VERSION 5.8 ;
BUSBITCHARS "[]" ;
DIVIDERCHAR "/" ;
UNITS
    DATABASE MICRONS 1000 ;
END UNITS

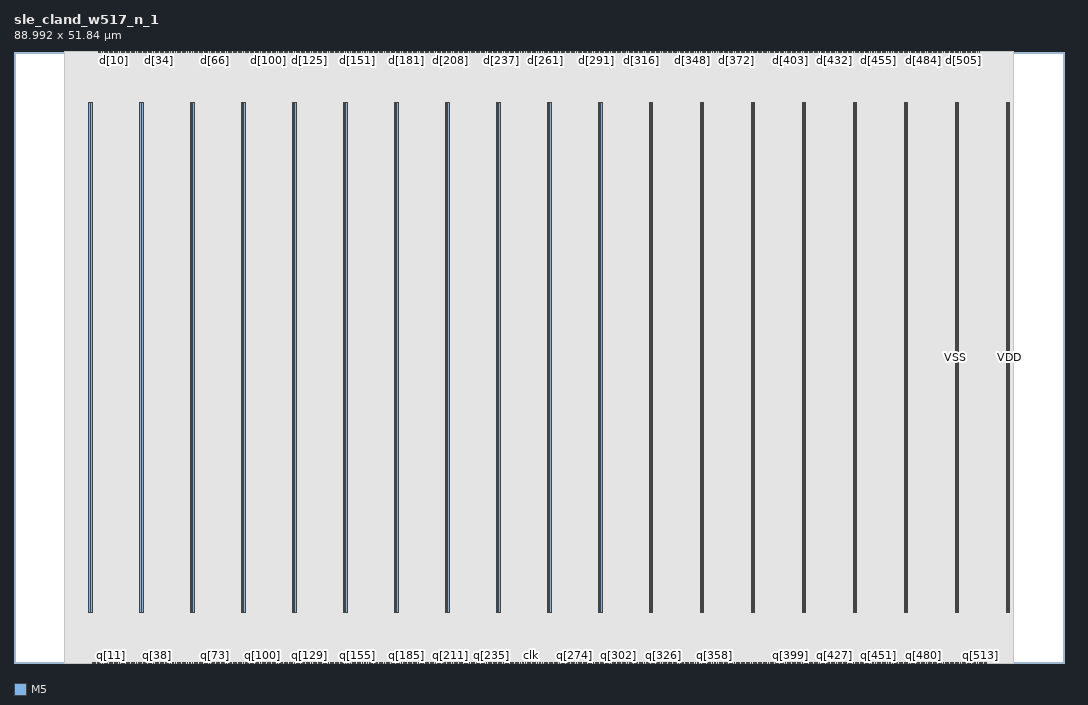
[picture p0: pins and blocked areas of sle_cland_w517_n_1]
MACRO sle_cland_w517_n_1
  FOREIGN sle_cland_w517_n_1 0 0 ;
  CLASS BLOCK ;
  SIZE 88.992 BY 51.84 ;
  PIN clk
    DIRECTION INPUT ;
    USE SIGNAL ;
    PORT
      LAYER M5 ;
        RECT  43.776 0 43.8 0.084 ;
    END
  END clk
  PIN d[0]
    DIRECTION INPUT ;
    USE SIGNAL ;
    PORT
      LAYER M5 ;
        RECT  7.2 51.756 7.224 51.84 ;
    END
  END d[0]
  PIN d[100]
    DIRECTION INPUT ;
    USE SIGNAL ;
    PORT
      LAYER M5 ;
        RECT  21.6 51.756 21.624 51.84 ;
    END
  END d[100]
  PIN d[101]
    DIRECTION INPUT ;
    USE SIGNAL ;
    PORT
      LAYER M5 ;
        RECT  21.888 51.756 21.912 51.84 ;
    END
  END d[101]
  PIN d[102]
    DIRECTION INPUT ;
    USE SIGNAL ;
    PORT
      LAYER M5 ;
        RECT  21.744 51.756 21.768 51.84 ;
    END
  END d[102]
  PIN d[103]
    DIRECTION INPUT ;
    USE SIGNAL ;
    PORT
      LAYER M5 ;
        RECT  22.176 51.756 22.2 51.84 ;
    END
  END d[103]
  PIN d[104]
    DIRECTION INPUT ;
    USE SIGNAL ;
    PORT
      LAYER M5 ;
        RECT  22.032 51.756 22.056 51.84 ;
    END
  END d[104]
  PIN d[105]
    DIRECTION INPUT ;
    USE SIGNAL ;
    PORT
      LAYER M5 ;
        RECT  22.464 51.756 22.488 51.84 ;
    END
  END d[105]
  PIN d[106]
    DIRECTION INPUT ;
    USE SIGNAL ;
    PORT
      LAYER M5 ;
        RECT  22.32 51.756 22.344 51.84 ;
    END
  END d[106]
  PIN d[107]
    DIRECTION INPUT ;
    USE SIGNAL ;
    PORT
      LAYER M5 ;
        RECT  22.752 51.756 22.776 51.84 ;
    END
  END d[107]
  PIN d[108]
    DIRECTION INPUT ;
    USE SIGNAL ;
    PORT
      LAYER M5 ;
        RECT  22.608 51.756 22.632 51.84 ;
    END
  END d[108]
  PIN d[109]
    DIRECTION INPUT ;
    USE SIGNAL ;
    PORT
      LAYER M5 ;
        RECT  23.04 51.756 23.064 51.84 ;
    END
  END d[109]
  PIN d[10]
    DIRECTION INPUT ;
    USE SIGNAL ;
    PORT
      LAYER M5 ;
        RECT  8.496 51.756 8.52 51.84 ;
    END
  END d[10]
  PIN d[110]
    DIRECTION INPUT ;
    USE SIGNAL ;
    PORT
      LAYER M5 ;
        RECT  22.896 51.756 22.92 51.84 ;
    END
  END d[110]
  PIN d[111]
    DIRECTION INPUT ;
    USE SIGNAL ;
    PORT
      LAYER M5 ;
        RECT  23.184 51.756 23.208 51.84 ;
    END
  END d[111]
  PIN d[112]
    DIRECTION INPUT ;
    USE SIGNAL ;
    PORT
      LAYER M5 ;
        RECT  23.616 51.756 23.64 51.84 ;
    END
  END d[112]
  PIN d[113]
    DIRECTION INPUT ;
    USE SIGNAL ;
    PORT
      LAYER M5 ;
        RECT  23.328 51.756 23.352 51.84 ;
    END
  END d[113]
  PIN d[114]
    DIRECTION INPUT ;
    USE SIGNAL ;
    PORT
      LAYER M5 ;
        RECT  23.904 51.756 23.928 51.84 ;
    END
  END d[114]
  PIN d[115]
    DIRECTION INPUT ;
    USE SIGNAL ;
    PORT
      LAYER M5 ;
        RECT  23.472 51.756 23.496 51.84 ;
    END
  END d[115]
  PIN d[116]
    DIRECTION INPUT ;
    USE SIGNAL ;
    PORT
      LAYER M5 ;
        RECT  24.048 51.756 24.072 51.84 ;
    END
  END d[116]
  PIN d[117]
    DIRECTION INPUT ;
    USE SIGNAL ;
    PORT
      LAYER M5 ;
        RECT  23.76 51.756 23.784 51.84 ;
    END
  END d[117]
  PIN d[118]
    DIRECTION INPUT ;
    USE SIGNAL ;
    PORT
      LAYER M5 ;
        RECT  24.336 51.756 24.36 51.84 ;
    END
  END d[118]
  PIN d[119]
    DIRECTION INPUT ;
    USE SIGNAL ;
    PORT
      LAYER M5 ;
        RECT  24.192 51.756 24.216 51.84 ;
    END
  END d[119]
  PIN d[11]
    DIRECTION INPUT ;
    USE SIGNAL ;
    PORT
      LAYER M5 ;
        RECT  8.784 51.756 8.808 51.84 ;
    END
  END d[11]
  PIN d[120]
    DIRECTION INPUT ;
    USE SIGNAL ;
    PORT
      LAYER M5 ;
        RECT  24.624 51.756 24.648 51.84 ;
    END
  END d[120]
  PIN d[121]
    DIRECTION INPUT ;
    USE SIGNAL ;
    PORT
      LAYER M5 ;
        RECT  24.48 51.756 24.504 51.84 ;
    END
  END d[121]
  PIN d[122]
    DIRECTION INPUT ;
    USE SIGNAL ;
    PORT
      LAYER M5 ;
        RECT  24.912 51.756 24.936 51.84 ;
    END
  END d[122]
  PIN d[123]
    DIRECTION INPUT ;
    USE SIGNAL ;
    PORT
      LAYER M5 ;
        RECT  24.768 51.756 24.792 51.84 ;
    END
  END d[123]
  PIN d[124]
    DIRECTION INPUT ;
    USE SIGNAL ;
    PORT
      LAYER M5 ;
        RECT  25.2 51.756 25.224 51.84 ;
    END
  END d[124]
  PIN d[125]
    DIRECTION INPUT ;
    USE SIGNAL ;
    PORT
      LAYER M5 ;
        RECT  25.056 51.756 25.08 51.84 ;
    END
  END d[125]
  PIN d[126]
    DIRECTION INPUT ;
    USE SIGNAL ;
    PORT
      LAYER M5 ;
        RECT  25.488 51.756 25.512 51.84 ;
    END
  END d[126]
  PIN d[127]
    DIRECTION INPUT ;
    USE SIGNAL ;
    PORT
      LAYER M5 ;
        RECT  25.344 51.756 25.368 51.84 ;
    END
  END d[127]
  PIN d[128]
    DIRECTION INPUT ;
    USE SIGNAL ;
    PORT
      LAYER M5 ;
        RECT  25.776 51.756 25.8 51.84 ;
    END
  END d[128]
  PIN d[129]
    DIRECTION INPUT ;
    USE SIGNAL ;
    PORT
      LAYER M5 ;
        RECT  25.632 51.756 25.656 51.84 ;
    END
  END d[129]
  PIN d[12]
    DIRECTION INPUT ;
    USE SIGNAL ;
    PORT
      LAYER M5 ;
        RECT  9.216 51.756 9.24 51.84 ;
    END
  END d[12]
  PIN d[130]
    DIRECTION INPUT ;
    USE SIGNAL ;
    PORT
      LAYER M5 ;
        RECT  25.92 51.756 25.944 51.84 ;
    END
  END d[130]
  PIN d[131]
    DIRECTION INPUT ;
    USE SIGNAL ;
    PORT
      LAYER M5 ;
        RECT  26.064 51.756 26.088 51.84 ;
    END
  END d[131]
  PIN d[132]
    DIRECTION INPUT ;
    USE SIGNAL ;
    PORT
      LAYER M5 ;
        RECT  26.208 51.756 26.232 51.84 ;
    END
  END d[132]
  PIN d[133]
    DIRECTION INPUT ;
    USE SIGNAL ;
    PORT
      LAYER M5 ;
        RECT  26.352 51.756 26.376 51.84 ;
    END
  END d[133]
  PIN d[134]
    DIRECTION INPUT ;
    USE SIGNAL ;
    PORT
      LAYER M5 ;
        RECT  26.496 51.756 26.52 51.84 ;
    END
  END d[134]
  PIN d[135]
    DIRECTION INPUT ;
    USE SIGNAL ;
    PORT
      LAYER M5 ;
        RECT  26.64 51.756 26.664 51.84 ;
    END
  END d[135]
  PIN d[136]
    DIRECTION INPUT ;
    USE SIGNAL ;
    PORT
      LAYER M5 ;
        RECT  26.784 51.756 26.808 51.84 ;
    END
  END d[136]
  PIN d[137]
    DIRECTION INPUT ;
    USE SIGNAL ;
    PORT
      LAYER M5 ;
        RECT  26.928 51.756 26.952 51.84 ;
    END
  END d[137]
  PIN d[138]
    DIRECTION INPUT ;
    USE SIGNAL ;
    PORT
      LAYER M5 ;
        RECT  27.072 51.756 27.096 51.84 ;
    END
  END d[138]
  PIN d[139]
    DIRECTION INPUT ;
    USE SIGNAL ;
    PORT
      LAYER M5 ;
        RECT  27.216 51.756 27.24 51.84 ;
    END
  END d[139]
  PIN d[13]
    DIRECTION INPUT ;
    USE SIGNAL ;
    PORT
      LAYER M5 ;
        RECT  8.928 51.756 8.952 51.84 ;
    END
  END d[13]
  PIN d[140]
    DIRECTION INPUT ;
    USE SIGNAL ;
    PORT
      LAYER M5 ;
        RECT  27.36 51.756 27.384 51.84 ;
    END
  END d[140]
  PIN d[141]
    DIRECTION INPUT ;
    USE SIGNAL ;
    PORT
      LAYER M5 ;
        RECT  27.504 51.756 27.528 51.84 ;
    END
  END d[141]
  PIN d[142]
    DIRECTION INPUT ;
    USE SIGNAL ;
    PORT
      LAYER M5 ;
        RECT  27.648 51.756 27.672 51.84 ;
    END
  END d[142]
  PIN d[143]
    DIRECTION INPUT ;
    USE SIGNAL ;
    PORT
      LAYER M5 ;
        RECT  27.792 51.756 27.816 51.84 ;
    END
  END d[143]
  PIN d[144]
    DIRECTION INPUT ;
    USE SIGNAL ;
    PORT
      LAYER M5 ;
        RECT  27.936 51.756 27.96 51.84 ;
    END
  END d[144]
  PIN d[145]
    DIRECTION INPUT ;
    USE SIGNAL ;
    PORT
      LAYER M5 ;
        RECT  28.08 51.756 28.104 51.84 ;
    END
  END d[145]
  PIN d[146]
    DIRECTION INPUT ;
    USE SIGNAL ;
    PORT
      LAYER M5 ;
        RECT  28.224 51.756 28.248 51.84 ;
    END
  END d[146]
  PIN d[147]
    DIRECTION INPUT ;
    USE SIGNAL ;
    PORT
      LAYER M5 ;
        RECT  28.512 51.756 28.536 51.84 ;
    END
  END d[147]
  PIN d[148]
    DIRECTION INPUT ;
    USE SIGNAL ;
    PORT
      LAYER M5 ;
        RECT  28.368 51.756 28.392 51.84 ;
    END
  END d[148]
  PIN d[149]
    DIRECTION INPUT ;
    USE SIGNAL ;
    PORT
      LAYER M5 ;
        RECT  28.656 51.756 28.68 51.84 ;
    END
  END d[149]
  PIN d[14]
    DIRECTION INPUT ;
    USE SIGNAL ;
    PORT
      LAYER M5 ;
        RECT  9.504 51.756 9.528 51.84 ;
    END
  END d[14]
  PIN d[150]
    DIRECTION INPUT ;
    USE SIGNAL ;
    PORT
      LAYER M5 ;
        RECT  28.8 51.756 28.824 51.84 ;
    END
  END d[150]
  PIN d[151]
    DIRECTION INPUT ;
    USE SIGNAL ;
    PORT
      LAYER M5 ;
        RECT  29.088 51.756 29.112 51.84 ;
    END
  END d[151]
  PIN d[152]
    DIRECTION INPUT ;
    USE SIGNAL ;
    PORT
      LAYER M5 ;
        RECT  28.944 51.756 28.968 51.84 ;
    END
  END d[152]
  PIN d[153]
    DIRECTION INPUT ;
    USE SIGNAL ;
    PORT
      LAYER M5 ;
        RECT  29.376 51.756 29.4 51.84 ;
    END
  END d[153]
  PIN d[154]
    DIRECTION INPUT ;
    USE SIGNAL ;
    PORT
      LAYER M5 ;
        RECT  29.232 51.756 29.256 51.84 ;
    END
  END d[154]
  PIN d[155]
    DIRECTION INPUT ;
    USE SIGNAL ;
    PORT
      LAYER M5 ;
        RECT  29.664 51.756 29.688 51.84 ;
    END
  END d[155]
  PIN d[156]
    DIRECTION INPUT ;
    USE SIGNAL ;
    PORT
      LAYER M5 ;
        RECT  29.52 51.756 29.544 51.84 ;
    END
  END d[156]
  PIN d[157]
    DIRECTION INPUT ;
    USE SIGNAL ;
    PORT
      LAYER M5 ;
        RECT  29.952 51.756 29.976 51.84 ;
    END
  END d[157]
  PIN d[158]
    DIRECTION INPUT ;
    USE SIGNAL ;
    PORT
      LAYER M5 ;
        RECT  29.808 51.756 29.832 51.84 ;
    END
  END d[158]
  PIN d[159]
    DIRECTION INPUT ;
    USE SIGNAL ;
    PORT
      LAYER M5 ;
        RECT  30.24 51.756 30.264 51.84 ;
    END
  END d[159]
  PIN d[15]
    DIRECTION INPUT ;
    USE SIGNAL ;
    PORT
      LAYER M5 ;
        RECT  9.072 51.756 9.096 51.84 ;
    END
  END d[15]
  PIN d[160]
    DIRECTION INPUT ;
    USE SIGNAL ;
    PORT
      LAYER M5 ;
        RECT  30.096 51.756 30.12 51.84 ;
    END
  END d[160]
  PIN d[161]
    DIRECTION INPUT ;
    USE SIGNAL ;
    PORT
      LAYER M5 ;
        RECT  30.384 51.756 30.408 51.84 ;
    END
  END d[161]
  PIN d[162]
    DIRECTION INPUT ;
    USE SIGNAL ;
    PORT
      LAYER M5 ;
        RECT  30.672 51.756 30.696 51.84 ;
    END
  END d[162]
  PIN d[163]
    DIRECTION INPUT ;
    USE SIGNAL ;
    PORT
      LAYER M5 ;
        RECT  30.528 51.756 30.552 51.84 ;
    END
  END d[163]
  PIN d[164]
    DIRECTION INPUT ;
    USE SIGNAL ;
    PORT
      LAYER M5 ;
        RECT  30.96 51.756 30.984 51.84 ;
    END
  END d[164]
  PIN d[165]
    DIRECTION INPUT ;
    USE SIGNAL ;
    PORT
      LAYER M5 ;
        RECT  30.816 51.756 30.84 51.84 ;
    END
  END d[165]
  PIN d[166]
    DIRECTION INPUT ;
    USE SIGNAL ;
    PORT
      LAYER M5 ;
        RECT  31.248 51.756 31.272 51.84 ;
    END
  END d[166]
  PIN d[167]
    DIRECTION INPUT ;
    USE SIGNAL ;
    PORT
      LAYER M5 ;
        RECT  31.104 51.756 31.128 51.84 ;
    END
  END d[167]
  PIN d[168]
    DIRECTION INPUT ;
    USE SIGNAL ;
    PORT
      LAYER M5 ;
        RECT  31.536 51.756 31.56 51.84 ;
    END
  END d[168]
  PIN d[169]
    DIRECTION INPUT ;
    USE SIGNAL ;
    PORT
      LAYER M5 ;
        RECT  31.392 51.756 31.416 51.84 ;
    END
  END d[169]
  PIN d[16]
    DIRECTION INPUT ;
    USE SIGNAL ;
    PORT
      LAYER M5 ;
        RECT  9.792 51.756 9.816 51.84 ;
    END
  END d[16]
  PIN d[170]
    DIRECTION INPUT ;
    USE SIGNAL ;
    PORT
      LAYER M5 ;
        RECT  31.824 51.756 31.848 51.84 ;
    END
  END d[170]
  PIN d[171]
    DIRECTION INPUT ;
    USE SIGNAL ;
    PORT
      LAYER M5 ;
        RECT  31.68 51.756 31.704 51.84 ;
    END
  END d[171]
  PIN d[172]
    DIRECTION INPUT ;
    USE SIGNAL ;
    PORT
      LAYER M5 ;
        RECT  32.112 51.756 32.136 51.84 ;
    END
  END d[172]
  PIN d[173]
    DIRECTION INPUT ;
    USE SIGNAL ;
    PORT
      LAYER M5 ;
        RECT  31.968 51.756 31.992 51.84 ;
    END
  END d[173]
  PIN d[174]
    DIRECTION INPUT ;
    USE SIGNAL ;
    PORT
      LAYER M5 ;
        RECT  32.256 51.756 32.28 51.84 ;
    END
  END d[174]
  PIN d[175]
    DIRECTION INPUT ;
    USE SIGNAL ;
    PORT
      LAYER M5 ;
        RECT  32.4 51.756 32.424 51.84 ;
    END
  END d[175]
  PIN d[176]
    DIRECTION INPUT ;
    USE SIGNAL ;
    PORT
      LAYER M5 ;
        RECT  32.688 51.756 32.712 51.84 ;
    END
  END d[176]
  PIN d[177]
    DIRECTION INPUT ;
    USE SIGNAL ;
    PORT
      LAYER M5 ;
        RECT  32.544 51.756 32.568 51.84 ;
    END
  END d[177]
  PIN d[178]
    DIRECTION INPUT ;
    USE SIGNAL ;
    PORT
      LAYER M5 ;
        RECT  32.976 51.756 33 51.84 ;
    END
  END d[178]
  PIN d[179]
    DIRECTION INPUT ;
    USE SIGNAL ;
    PORT
      LAYER M5 ;
        RECT  32.832 51.756 32.856 51.84 ;
    END
  END d[179]
  PIN d[17]
    DIRECTION INPUT ;
    USE SIGNAL ;
    PORT
      LAYER M5 ;
        RECT  9.36 51.756 9.384 51.84 ;
    END
  END d[17]
  PIN d[180]
    DIRECTION INPUT ;
    USE SIGNAL ;
    PORT
      LAYER M5 ;
        RECT  33.12 51.756 33.144 51.84 ;
    END
  END d[180]
  PIN d[181]
    DIRECTION INPUT ;
    USE SIGNAL ;
    PORT
      LAYER M5 ;
        RECT  33.264 51.756 33.288 51.84 ;
    END
  END d[181]
  PIN d[182]
    DIRECTION INPUT ;
    USE SIGNAL ;
    PORT
      LAYER M5 ;
        RECT  33.408 51.756 33.432 51.84 ;
    END
  END d[182]
  PIN d[183]
    DIRECTION INPUT ;
    USE SIGNAL ;
    PORT
      LAYER M5 ;
        RECT  33.552 51.756 33.576 51.84 ;
    END
  END d[183]
  PIN d[184]
    DIRECTION INPUT ;
    USE SIGNAL ;
    PORT
      LAYER M5 ;
        RECT  33.696 51.756 33.72 51.84 ;
    END
  END d[184]
  PIN d[185]
    DIRECTION INPUT ;
    USE SIGNAL ;
    PORT
      LAYER M5 ;
        RECT  33.84 51.756 33.864 51.84 ;
    END
  END d[185]
  PIN d[186]
    DIRECTION INPUT ;
    USE SIGNAL ;
    PORT
      LAYER M5 ;
        RECT  33.984 51.756 34.008 51.84 ;
    END
  END d[186]
  PIN d[187]
    DIRECTION INPUT ;
    USE SIGNAL ;
    PORT
      LAYER M5 ;
        RECT  34.128 51.756 34.152 51.84 ;
    END
  END d[187]
  PIN d[188]
    DIRECTION INPUT ;
    USE SIGNAL ;
    PORT
      LAYER M5 ;
        RECT  34.272 51.756 34.296 51.84 ;
    END
  END d[188]
  PIN d[189]
    DIRECTION INPUT ;
    USE SIGNAL ;
    PORT
      LAYER M5 ;
        RECT  34.416 51.756 34.44 51.84 ;
    END
  END d[189]
  PIN d[18]
    DIRECTION INPUT ;
    USE SIGNAL ;
    PORT
      LAYER M5 ;
        RECT  10.08 51.756 10.104 51.84 ;
    END
  END d[18]
  PIN d[190]
    DIRECTION INPUT ;
    USE SIGNAL ;
    PORT
      LAYER M5 ;
        RECT  34.56 51.756 34.584 51.84 ;
    END
  END d[190]
  PIN d[191]
    DIRECTION INPUT ;
    USE SIGNAL ;
    PORT
      LAYER M5 ;
        RECT  34.704 51.756 34.728 51.84 ;
    END
  END d[191]
  PIN d[192]
    DIRECTION INPUT ;
    USE SIGNAL ;
    PORT
      LAYER M5 ;
        RECT  34.848 51.756 34.872 51.84 ;
    END
  END d[192]
  PIN d[193]
    DIRECTION INPUT ;
    USE SIGNAL ;
    PORT
      LAYER M5 ;
        RECT  35.136 51.756 35.16 51.84 ;
    END
  END d[193]
  PIN d[194]
    DIRECTION INPUT ;
    USE SIGNAL ;
    PORT
      LAYER M5 ;
        RECT  34.992 51.756 35.016 51.84 ;
    END
  END d[194]
  PIN d[195]
    DIRECTION INPUT ;
    USE SIGNAL ;
    PORT
      LAYER M5 ;
        RECT  35.424 51.756 35.448 51.84 ;
    END
  END d[195]
  PIN d[196]
    DIRECTION INPUT ;
    USE SIGNAL ;
    PORT
      LAYER M5 ;
        RECT  35.28 51.756 35.304 51.84 ;
    END
  END d[196]
  PIN d[197]
    DIRECTION INPUT ;
    USE SIGNAL ;
    PORT
      LAYER M5 ;
        RECT  35.712 51.756 35.736 51.84 ;
    END
  END d[197]
  PIN d[198]
    DIRECTION INPUT ;
    USE SIGNAL ;
    PORT
      LAYER M5 ;
        RECT  35.568 51.756 35.592 51.84 ;
    END
  END d[198]
  PIN d[199]
    DIRECTION INPUT ;
    USE SIGNAL ;
    PORT
      LAYER M5 ;
        RECT  35.856 51.756 35.88 51.84 ;
    END
  END d[199]
  PIN d[19]
    DIRECTION INPUT ;
    USE SIGNAL ;
    PORT
      LAYER M5 ;
        RECT  9.648 51.756 9.672 51.84 ;
    END
  END d[19]
  PIN d[1]
    DIRECTION INPUT ;
    USE SIGNAL ;
    PORT
      LAYER M5 ;
        RECT  7.344 51.756 7.368 51.84 ;
    END
  END d[1]
  PIN d[200]
    DIRECTION INPUT ;
    USE SIGNAL ;
    PORT
      LAYER M5 ;
        RECT  36 51.756 36.024 51.84 ;
    END
  END d[200]
  PIN d[201]
    DIRECTION INPUT ;
    USE SIGNAL ;
    PORT
      LAYER M5 ;
        RECT  36.288 51.756 36.312 51.84 ;
    END
  END d[201]
  PIN d[202]
    DIRECTION INPUT ;
    USE SIGNAL ;
    PORT
      LAYER M5 ;
        RECT  36.144 51.756 36.168 51.84 ;
    END
  END d[202]
  PIN d[203]
    DIRECTION INPUT ;
    USE SIGNAL ;
    PORT
      LAYER M5 ;
        RECT  36.576 51.756 36.6 51.84 ;
    END
  END d[203]
  PIN d[204]
    DIRECTION INPUT ;
    USE SIGNAL ;
    PORT
      LAYER M5 ;
        RECT  36.432 51.756 36.456 51.84 ;
    END
  END d[204]
  PIN d[205]
    DIRECTION INPUT ;
    USE SIGNAL ;
    PORT
      LAYER M5 ;
        RECT  36.864 51.756 36.888 51.84 ;
    END
  END d[205]
  PIN d[206]
    DIRECTION INPUT ;
    USE SIGNAL ;
    PORT
      LAYER M5 ;
        RECT  36.72 51.756 36.744 51.84 ;
    END
  END d[206]
  PIN d[207]
    DIRECTION INPUT ;
    USE SIGNAL ;
    PORT
      LAYER M5 ;
        RECT  37.152 51.756 37.176 51.84 ;
    END
  END d[207]
  PIN d[208]
    DIRECTION INPUT ;
    USE SIGNAL ;
    PORT
      LAYER M5 ;
        RECT  37.008 51.756 37.032 51.84 ;
    END
  END d[208]
  PIN d[209]
    DIRECTION INPUT ;
    USE SIGNAL ;
    PORT
      LAYER M5 ;
        RECT  37.44 51.756 37.464 51.84 ;
    END
  END d[209]
  PIN d[20]
    DIRECTION INPUT ;
    USE SIGNAL ;
    PORT
      LAYER M5 ;
        RECT  10.368 51.756 10.392 51.84 ;
    END
  END d[20]
  PIN d[210]
    DIRECTION INPUT ;
    USE SIGNAL ;
    PORT
      LAYER M5 ;
        RECT  37.296 51.756 37.32 51.84 ;
    END
  END d[210]
  PIN d[211]
    DIRECTION INPUT ;
    USE SIGNAL ;
    PORT
      LAYER M5 ;
        RECT  37.584 51.756 37.608 51.84 ;
    END
  END d[211]
  PIN d[212]
    DIRECTION INPUT ;
    USE SIGNAL ;
    PORT
      LAYER M5 ;
        RECT  37.872 51.756 37.896 51.84 ;
    END
  END d[212]
  PIN d[213]
    DIRECTION INPUT ;
    USE SIGNAL ;
    PORT
      LAYER M5 ;
        RECT  37.728 51.756 37.752 51.84 ;
    END
  END d[213]
  PIN d[214]
    DIRECTION INPUT ;
    USE SIGNAL ;
    PORT
      LAYER M5 ;
        RECT  38.16 51.756 38.184 51.84 ;
    END
  END d[214]
  PIN d[215]
    DIRECTION INPUT ;
    USE SIGNAL ;
    PORT
      LAYER M5 ;
        RECT  38.016 51.756 38.04 51.84 ;
    END
  END d[215]
  PIN d[216]
    DIRECTION INPUT ;
    USE SIGNAL ;
    PORT
      LAYER M5 ;
        RECT  38.448 51.756 38.472 51.84 ;
    END
  END d[216]
  PIN d[217]
    DIRECTION INPUT ;
    USE SIGNAL ;
    PORT
      LAYER M5 ;
        RECT  38.304 51.756 38.328 51.84 ;
    END
  END d[217]
  PIN d[218]
    DIRECTION INPUT ;
    USE SIGNAL ;
    PORT
      LAYER M5 ;
        RECT  38.736 51.756 38.76 51.84 ;
    END
  END d[218]
  PIN d[219]
    DIRECTION INPUT ;
    USE SIGNAL ;
    PORT
      LAYER M5 ;
        RECT  38.592 51.756 38.616 51.84 ;
    END
  END d[219]
  PIN d[21]
    DIRECTION INPUT ;
    USE SIGNAL ;
    PORT
      LAYER M5 ;
        RECT  9.936 51.756 9.96 51.84 ;
    END
  END d[21]
  PIN d[220]
    DIRECTION INPUT ;
    USE SIGNAL ;
    PORT
      LAYER M5 ;
        RECT  39.024 51.756 39.048 51.84 ;
    END
  END d[220]
  PIN d[221]
    DIRECTION INPUT ;
    USE SIGNAL ;
    PORT
      LAYER M5 ;
        RECT  38.88 51.756 38.904 51.84 ;
    END
  END d[221]
  PIN d[222]
    DIRECTION INPUT ;
    USE SIGNAL ;
    PORT
      LAYER M5 ;
        RECT  39.312 51.756 39.336 51.84 ;
    END
  END d[222]
  PIN d[223]
    DIRECTION INPUT ;
    USE SIGNAL ;
    PORT
      LAYER M5 ;
        RECT  39.168 51.756 39.192 51.84 ;
    END
  END d[223]
  PIN d[224]
    DIRECTION INPUT ;
    USE SIGNAL ;
    PORT
      LAYER M5 ;
        RECT  39.456 51.756 39.48 51.84 ;
    END
  END d[224]
  PIN d[225]
    DIRECTION INPUT ;
    USE SIGNAL ;
    PORT
      LAYER M5 ;
        RECT  39.6 51.756 39.624 51.84 ;
    END
  END d[225]
  PIN d[226]
    DIRECTION INPUT ;
    USE SIGNAL ;
    PORT
      LAYER M5 ;
        RECT  39.744 51.756 39.768 51.84 ;
    END
  END d[226]
  PIN d[227]
    DIRECTION INPUT ;
    USE SIGNAL ;
    PORT
      LAYER M5 ;
        RECT  39.888 51.756 39.912 51.84 ;
    END
  END d[227]
  PIN d[228]
    DIRECTION INPUT ;
    USE SIGNAL ;
    PORT
      LAYER M5 ;
        RECT  40.032 51.756 40.056 51.84 ;
    END
  END d[228]
  PIN d[229]
    DIRECTION INPUT ;
    USE SIGNAL ;
    PORT
      LAYER M5 ;
        RECT  40.176 51.756 40.2 51.84 ;
    END
  END d[229]
  PIN d[22]
    DIRECTION INPUT ;
    USE SIGNAL ;
    PORT
      LAYER M5 ;
        RECT  10.512 51.756 10.536 51.84 ;
    END
  END d[22]
  PIN d[230]
    DIRECTION INPUT ;
    USE SIGNAL ;
    PORT
      LAYER M5 ;
        RECT  40.32 51.756 40.344 51.84 ;
    END
  END d[230]
  PIN d[231]
    DIRECTION INPUT ;
    USE SIGNAL ;
    PORT
      LAYER M5 ;
        RECT  40.464 51.756 40.488 51.84 ;
    END
  END d[231]
  PIN d[232]
    DIRECTION INPUT ;
    USE SIGNAL ;
    PORT
      LAYER M5 ;
        RECT  40.608 51.756 40.632 51.84 ;
    END
  END d[232]
  PIN d[233]
    DIRECTION INPUT ;
    USE SIGNAL ;
    PORT
      LAYER M5 ;
        RECT  40.752 51.756 40.776 51.84 ;
    END
  END d[233]
  PIN d[234]
    DIRECTION INPUT ;
    USE SIGNAL ;
    PORT
      LAYER M5 ;
        RECT  40.896 51.756 40.92 51.84 ;
    END
  END d[234]
  PIN d[235]
    DIRECTION INPUT ;
    USE SIGNAL ;
    PORT
      LAYER M5 ;
        RECT  41.04 51.756 41.064 51.84 ;
    END
  END d[235]
  PIN d[236]
    DIRECTION INPUT ;
    USE SIGNAL ;
    PORT
      LAYER M5 ;
        RECT  41.184 51.756 41.208 51.84 ;
    END
  END d[236]
  PIN d[237]
    DIRECTION INPUT ;
    USE SIGNAL ;
    PORT
      LAYER M5 ;
        RECT  41.328 51.756 41.352 51.84 ;
    END
  END d[237]
  PIN d[238]
    DIRECTION INPUT ;
    USE SIGNAL ;
    PORT
      LAYER M5 ;
        RECT  41.472 51.756 41.496 51.84 ;
    END
  END d[238]
  PIN d[239]
    DIRECTION INPUT ;
    USE SIGNAL ;
    PORT
      LAYER M5 ;
        RECT  41.616 51.756 41.64 51.84 ;
    END
  END d[239]
  PIN d[23]
    DIRECTION INPUT ;
    USE SIGNAL ;
    PORT
      LAYER M5 ;
        RECT  10.224 51.756 10.248 51.84 ;
    END
  END d[23]
  PIN d[240]
    DIRECTION INPUT ;
    USE SIGNAL ;
    PORT
      LAYER M5 ;
        RECT  41.76 51.756 41.784 51.84 ;
    END
  END d[240]
  PIN d[241]
    DIRECTION INPUT ;
    USE SIGNAL ;
    PORT
      LAYER M5 ;
        RECT  42.048 51.756 42.072 51.84 ;
    END
  END d[241]
  PIN d[242]
    DIRECTION INPUT ;
    USE SIGNAL ;
    PORT
      LAYER M5 ;
        RECT  41.904 51.756 41.928 51.84 ;
    END
  END d[242]
  PIN d[243]
    DIRECTION INPUT ;
    USE SIGNAL ;
    PORT
      LAYER M5 ;
        RECT  42.336 51.756 42.36 51.84 ;
    END
  END d[243]
  PIN d[244]
    DIRECTION INPUT ;
    USE SIGNAL ;
    PORT
      LAYER M5 ;
        RECT  42.192 51.756 42.216 51.84 ;
    END
  END d[244]
  PIN d[245]
    DIRECTION INPUT ;
    USE SIGNAL ;
    PORT
      LAYER M5 ;
        RECT  42.624 51.756 42.648 51.84 ;
    END
  END d[245]
  PIN d[246]
    DIRECTION INPUT ;
    USE SIGNAL ;
    PORT
      LAYER M5 ;
        RECT  42.48 51.756 42.504 51.84 ;
    END
  END d[246]
  PIN d[247]
    DIRECTION INPUT ;
    USE SIGNAL ;
    PORT
      LAYER M5 ;
        RECT  42.912 51.756 42.936 51.84 ;
    END
  END d[247]
  PIN d[248]
    DIRECTION INPUT ;
    USE SIGNAL ;
    PORT
      LAYER M5 ;
        RECT  42.768 51.756 42.792 51.84 ;
    END
  END d[248]
  PIN d[249]
    DIRECTION INPUT ;
    USE SIGNAL ;
    PORT
      LAYER M5 ;
        RECT  43.344 51.756 43.368 51.84 ;
    END
  END d[249]
  PIN d[24]
    DIRECTION INPUT ;
    USE SIGNAL ;
    PORT
      LAYER M5 ;
        RECT  10.8 51.756 10.824 51.84 ;
    END
  END d[24]
  PIN d[250]
    DIRECTION INPUT ;
    USE SIGNAL ;
    PORT
      LAYER M5 ;
        RECT  43.056 51.756 43.08 51.84 ;
    END
  END d[250]
  PIN d[251]
    DIRECTION INPUT ;
    USE SIGNAL ;
    PORT
      LAYER M5 ;
        RECT  43.488 51.756 43.512 51.84 ;
    END
  END d[251]
  PIN d[252]
    DIRECTION INPUT ;
    USE SIGNAL ;
    PORT
      LAYER M5 ;
        RECT  43.2 51.756 43.224 51.84 ;
    END
  END d[252]
  PIN d[253]
    DIRECTION INPUT ;
    USE SIGNAL ;
    PORT
      LAYER M5 ;
        RECT  43.776 51.756 43.8 51.84 ;
    END
  END d[253]
  PIN d[254]
    DIRECTION INPUT ;
    USE SIGNAL ;
    PORT
      LAYER M5 ;
        RECT  43.632 51.756 43.656 51.84 ;
    END
  END d[254]
  PIN d[255]
    DIRECTION INPUT ;
    USE SIGNAL ;
    PORT
      LAYER M5 ;
        RECT  44.064 51.756 44.088 51.84 ;
    END
  END d[255]
  PIN d[256]
    DIRECTION INPUT ;
    USE SIGNAL ;
    PORT
      LAYER M5 ;
        RECT  43.92 51.756 43.944 51.84 ;
    END
  END d[256]
  PIN d[257]
    DIRECTION INPUT ;
    USE SIGNAL ;
    PORT
      LAYER M5 ;
        RECT  44.64 51.756 44.664 51.84 ;
    END
  END d[257]
  PIN d[258]
    DIRECTION INPUT ;
    USE SIGNAL ;
    PORT
      LAYER M5 ;
        RECT  44.208 51.756 44.232 51.84 ;
    END
  END d[258]
  PIN d[259]
    DIRECTION INPUT ;
    USE SIGNAL ;
    PORT
      LAYER M5 ;
        RECT  44.928 51.756 44.952 51.84 ;
    END
  END d[259]
  PIN d[25]
    DIRECTION INPUT ;
    USE SIGNAL ;
    PORT
      LAYER M5 ;
        RECT  10.656 51.756 10.68 51.84 ;
    END
  END d[25]
  PIN d[260]
    DIRECTION INPUT ;
    USE SIGNAL ;
    PORT
      LAYER M5 ;
        RECT  44.784 51.756 44.808 51.84 ;
    END
  END d[260]
  PIN d[261]
    DIRECTION INPUT ;
    USE SIGNAL ;
    PORT
      LAYER M5 ;
        RECT  45.072 51.756 45.096 51.84 ;
    END
  END d[261]
  PIN d[262]
    DIRECTION INPUT ;
    USE SIGNAL ;
    PORT
      LAYER M5 ;
        RECT  45.36 51.756 45.384 51.84 ;
    END
  END d[262]
  PIN d[263]
    DIRECTION INPUT ;
    USE SIGNAL ;
    PORT
      LAYER M5 ;
        RECT  45.216 51.756 45.24 51.84 ;
    END
  END d[263]
  PIN d[264]
    DIRECTION INPUT ;
    USE SIGNAL ;
    PORT
      LAYER M5 ;
        RECT  45.648 51.756 45.672 51.84 ;
    END
  END d[264]
  PIN d[265]
    DIRECTION INPUT ;
    USE SIGNAL ;
    PORT
      LAYER M5 ;
        RECT  45.504 51.756 45.528 51.84 ;
    END
  END d[265]
  PIN d[266]
    DIRECTION INPUT ;
    USE SIGNAL ;
    PORT
      LAYER M5 ;
        RECT  45.936 51.756 45.96 51.84 ;
    END
  END d[266]
  PIN d[267]
    DIRECTION INPUT ;
    USE SIGNAL ;
    PORT
      LAYER M5 ;
        RECT  45.792 51.756 45.816 51.84 ;
    END
  END d[267]
  PIN d[268]
    DIRECTION INPUT ;
    USE SIGNAL ;
    PORT
      LAYER M5 ;
        RECT  46.224 51.756 46.248 51.84 ;
    END
  END d[268]
  PIN d[269]
    DIRECTION INPUT ;
    USE SIGNAL ;
    PORT
      LAYER M5 ;
        RECT  46.08 51.756 46.104 51.84 ;
    END
  END d[269]
  PIN d[26]
    DIRECTION INPUT ;
    USE SIGNAL ;
    PORT
      LAYER M5 ;
        RECT  11.088 51.756 11.112 51.84 ;
    END
  END d[26]
  PIN d[270]
    DIRECTION INPUT ;
    USE SIGNAL ;
    PORT
      LAYER M5 ;
        RECT  46.512 51.756 46.536 51.84 ;
    END
  END d[270]
  PIN d[271]
    DIRECTION INPUT ;
    USE SIGNAL ;
    PORT
      LAYER M5 ;
        RECT  46.368 51.756 46.392 51.84 ;
    END
  END d[271]
  PIN d[272]
    DIRECTION INPUT ;
    USE SIGNAL ;
    PORT
      LAYER M5 ;
        RECT  46.8 51.756 46.824 51.84 ;
    END
  END d[272]
  PIN d[273]
    DIRECTION INPUT ;
    USE SIGNAL ;
    PORT
      LAYER M5 ;
        RECT  46.656 51.756 46.68 51.84 ;
    END
  END d[273]
  PIN d[274]
    DIRECTION INPUT ;
    USE SIGNAL ;
    PORT
      LAYER M5 ;
        RECT  46.944 51.756 46.968 51.84 ;
    END
  END d[274]
  PIN d[275]
    DIRECTION INPUT ;
    USE SIGNAL ;
    PORT
      LAYER M5 ;
        RECT  47.088 51.756 47.112 51.84 ;
    END
  END d[275]
  PIN d[276]
    DIRECTION INPUT ;
    USE SIGNAL ;
    PORT
      LAYER M5 ;
        RECT  47.232 51.756 47.256 51.84 ;
    END
  END d[276]
  PIN d[277]
    DIRECTION INPUT ;
    USE SIGNAL ;
    PORT
      LAYER M5 ;
        RECT  47.376 51.756 47.4 51.84 ;
    END
  END d[277]
  PIN d[278]
    DIRECTION INPUT ;
    USE SIGNAL ;
    PORT
      LAYER M5 ;
        RECT  47.52 51.756 47.544 51.84 ;
    END
  END d[278]
  PIN d[279]
    DIRECTION INPUT ;
    USE SIGNAL ;
    PORT
      LAYER M5 ;
        RECT  47.664 51.756 47.688 51.84 ;
    END
  END d[279]
  PIN d[27]
    DIRECTION INPUT ;
    USE SIGNAL ;
    PORT
      LAYER M5 ;
        RECT  10.944 51.756 10.968 51.84 ;
    END
  END d[27]
  PIN d[280]
    DIRECTION INPUT ;
    USE SIGNAL ;
    PORT
      LAYER M5 ;
        RECT  47.808 51.756 47.832 51.84 ;
    END
  END d[280]
  PIN d[281]
    DIRECTION INPUT ;
    USE SIGNAL ;
    PORT
      LAYER M5 ;
        RECT  47.952 51.756 47.976 51.84 ;
    END
  END d[281]
  PIN d[282]
    DIRECTION INPUT ;
    USE SIGNAL ;
    PORT
      LAYER M5 ;
        RECT  48.096 51.756 48.12 51.84 ;
    END
  END d[282]
  PIN d[283]
    DIRECTION INPUT ;
    USE SIGNAL ;
    PORT
      LAYER M5 ;
        RECT  48.24 51.756 48.264 51.84 ;
    END
  END d[283]
  PIN d[284]
    DIRECTION INPUT ;
    USE SIGNAL ;
    PORT
      LAYER M5 ;
        RECT  48.384 51.756 48.408 51.84 ;
    END
  END d[284]
  PIN d[285]
    DIRECTION INPUT ;
    USE SIGNAL ;
    PORT
      LAYER M5 ;
        RECT  48.528 51.756 48.552 51.84 ;
    END
  END d[285]
  PIN d[286]
    DIRECTION INPUT ;
    USE SIGNAL ;
    PORT
      LAYER M5 ;
        RECT  48.672 51.756 48.696 51.84 ;
    END
  END d[286]
  PIN d[287]
    DIRECTION INPUT ;
    USE SIGNAL ;
    PORT
      LAYER M5 ;
        RECT  48.816 51.756 48.84 51.84 ;
    END
  END d[287]
  PIN d[288]
    DIRECTION INPUT ;
    USE SIGNAL ;
    PORT
      LAYER M5 ;
        RECT  48.96 51.756 48.984 51.84 ;
    END
  END d[288]
  PIN d[289]
    DIRECTION INPUT ;
    USE SIGNAL ;
    PORT
      LAYER M5 ;
        RECT  49.104 51.756 49.128 51.84 ;
    END
  END d[289]
  PIN d[28]
    DIRECTION INPUT ;
    USE SIGNAL ;
    PORT
      LAYER M5 ;
        RECT  11.376 51.756 11.4 51.84 ;
    END
  END d[28]
  PIN d[290]
    DIRECTION INPUT ;
    USE SIGNAL ;
    PORT
      LAYER M5 ;
        RECT  49.248 51.756 49.272 51.84 ;
    END
  END d[290]
  PIN d[291]
    DIRECTION INPUT ;
    USE SIGNAL ;
    PORT
      LAYER M5 ;
        RECT  49.392 51.756 49.416 51.84 ;
    END
  END d[291]
  PIN d[292]
    DIRECTION INPUT ;
    USE SIGNAL ;
    PORT
      LAYER M5 ;
        RECT  49.536 51.756 49.56 51.84 ;
    END
  END d[292]
  PIN d[293]
    DIRECTION INPUT ;
    USE SIGNAL ;
    PORT
      LAYER M5 ;
        RECT  49.824 51.756 49.848 51.84 ;
    END
  END d[293]
  PIN d[294]
    DIRECTION INPUT ;
    USE SIGNAL ;
    PORT
      LAYER M5 ;
        RECT  49.68 51.756 49.704 51.84 ;
    END
  END d[294]
  PIN d[295]
    DIRECTION INPUT ;
    USE SIGNAL ;
    PORT
      LAYER M5 ;
        RECT  50.112 51.756 50.136 51.84 ;
    END
  END d[295]
  PIN d[296]
    DIRECTION INPUT ;
    USE SIGNAL ;
    PORT
      LAYER M5 ;
        RECT  49.968 51.756 49.992 51.84 ;
    END
  END d[296]
  PIN d[297]
    DIRECTION INPUT ;
    USE SIGNAL ;
    PORT
      LAYER M5 ;
        RECT  50.4 51.756 50.424 51.84 ;
    END
  END d[297]
  PIN d[298]
    DIRECTION INPUT ;
    USE SIGNAL ;
    PORT
      LAYER M5 ;
        RECT  50.256 51.756 50.28 51.84 ;
    END
  END d[298]
  PIN d[299]
    DIRECTION INPUT ;
    USE SIGNAL ;
    PORT
      LAYER M5 ;
        RECT  50.832 51.756 50.856 51.84 ;
    END
  END d[299]
  PIN d[29]
    DIRECTION INPUT ;
    USE SIGNAL ;
    PORT
      LAYER M5 ;
        RECT  11.232 51.756 11.256 51.84 ;
    END
  END d[29]
  PIN d[2]
    DIRECTION INPUT ;
    USE SIGNAL ;
    PORT
      LAYER M5 ;
        RECT  7.488 51.756 7.512 51.84 ;
    END
  END d[2]
  PIN d[300]
    DIRECTION INPUT ;
    USE SIGNAL ;
    PORT
      LAYER M5 ;
        RECT  50.544 51.756 50.568 51.84 ;
    END
  END d[300]
  PIN d[301]
    DIRECTION INPUT ;
    USE SIGNAL ;
    PORT
      LAYER M5 ;
        RECT  50.976 51.756 51 51.84 ;
    END
  END d[301]
  PIN d[302]
    DIRECTION INPUT ;
    USE SIGNAL ;
    PORT
      LAYER M5 ;
        RECT  50.688 51.756 50.712 51.84 ;
    END
  END d[302]
  PIN d[303]
    DIRECTION INPUT ;
    USE SIGNAL ;
    PORT
      LAYER M5 ;
        RECT  51.264 51.756 51.288 51.84 ;
    END
  END d[303]
  PIN d[304]
    DIRECTION INPUT ;
    USE SIGNAL ;
    PORT
      LAYER M5 ;
        RECT  51.12 51.756 51.144 51.84 ;
    END
  END d[304]
  PIN d[305]
    DIRECTION INPUT ;
    USE SIGNAL ;
    PORT
      LAYER M5 ;
        RECT  51.696 51.756 51.72 51.84 ;
    END
  END d[305]
  PIN d[306]
    DIRECTION INPUT ;
    USE SIGNAL ;
    PORT
      LAYER M5 ;
        RECT  51.408 51.756 51.432 51.84 ;
    END
  END d[306]
  PIN d[307]
    DIRECTION INPUT ;
    USE SIGNAL ;
    PORT
      LAYER M5 ;
        RECT  51.984 51.756 52.008 51.84 ;
    END
  END d[307]
  PIN d[308]
    DIRECTION INPUT ;
    USE SIGNAL ;
    PORT
      LAYER M5 ;
        RECT  51.552 51.756 51.576 51.84 ;
    END
  END d[308]
  PIN d[309]
    DIRECTION INPUT ;
    USE SIGNAL ;
    PORT
      LAYER M5 ;
        RECT  52.272 51.756 52.296 51.84 ;
    END
  END d[309]
  PIN d[30]
    DIRECTION INPUT ;
    USE SIGNAL ;
    PORT
      LAYER M5 ;
        RECT  11.664 51.756 11.688 51.84 ;
    END
  END d[30]
  PIN d[310]
    DIRECTION INPUT ;
    USE SIGNAL ;
    PORT
      LAYER M5 ;
        RECT  51.84 51.756 51.864 51.84 ;
    END
  END d[310]
  PIN d[311]
    DIRECTION INPUT ;
    USE SIGNAL ;
    PORT
      LAYER M5 ;
        RECT  52.416 51.756 52.44 51.84 ;
    END
  END d[311]
  PIN d[312]
    DIRECTION INPUT ;
    USE SIGNAL ;
    PORT
      LAYER M5 ;
        RECT  52.128 51.756 52.152 51.84 ;
    END
  END d[312]
  PIN d[313]
    DIRECTION INPUT ;
    USE SIGNAL ;
    PORT
      LAYER M5 ;
        RECT  52.56 51.756 52.584 51.84 ;
    END
  END d[313]
  PIN d[314]
    DIRECTION INPUT ;
    USE SIGNAL ;
    PORT
      LAYER M5 ;
        RECT  52.848 51.756 52.872 51.84 ;
    END
  END d[314]
  PIN d[315]
    DIRECTION INPUT ;
    USE SIGNAL ;
    PORT
      LAYER M5 ;
        RECT  52.704 51.756 52.728 51.84 ;
    END
  END d[315]
  PIN d[316]
    DIRECTION INPUT ;
    USE SIGNAL ;
    PORT
      LAYER M5 ;
        RECT  53.136 51.756 53.16 51.84 ;
    END
  END d[316]
  PIN d[317]
    DIRECTION INPUT ;
    USE SIGNAL ;
    PORT
      LAYER M5 ;
        RECT  52.992 51.756 53.016 51.84 ;
    END
  END d[317]
  PIN d[318]
    DIRECTION INPUT ;
    USE SIGNAL ;
    PORT
      LAYER M5 ;
        RECT  53.424 51.756 53.448 51.84 ;
    END
  END d[318]
  PIN d[319]
    DIRECTION INPUT ;
    USE SIGNAL ;
    PORT
      LAYER M5 ;
        RECT  53.28 51.756 53.304 51.84 ;
    END
  END d[319]
  PIN d[31]
    DIRECTION INPUT ;
    USE SIGNAL ;
    PORT
      LAYER M5 ;
        RECT  11.52 51.756 11.544 51.84 ;
    END
  END d[31]
  PIN d[320]
    DIRECTION INPUT ;
    USE SIGNAL ;
    PORT
      LAYER M5 ;
        RECT  53.712 51.756 53.736 51.84 ;
    END
  END d[320]
  PIN d[321]
    DIRECTION INPUT ;
    USE SIGNAL ;
    PORT
      LAYER M5 ;
        RECT  53.568 51.756 53.592 51.84 ;
    END
  END d[321]
  PIN d[322]
    DIRECTION INPUT ;
    USE SIGNAL ;
    PORT
      LAYER M5 ;
        RECT  54 51.756 54.024 51.84 ;
    END
  END d[322]
  PIN d[323]
    DIRECTION INPUT ;
    USE SIGNAL ;
    PORT
      LAYER M5 ;
        RECT  53.856 51.756 53.88 51.84 ;
    END
  END d[323]
  PIN d[324]
    DIRECTION INPUT ;
    USE SIGNAL ;
    PORT
      LAYER M5 ;
        RECT  54.144 51.756 54.168 51.84 ;
    END
  END d[324]
  PIN d[325]
    DIRECTION INPUT ;
    USE SIGNAL ;
    PORT
      LAYER M5 ;
        RECT  54.288 51.756 54.312 51.84 ;
    END
  END d[325]
  PIN d[326]
    DIRECTION INPUT ;
    USE SIGNAL ;
    PORT
      LAYER M5 ;
        RECT  54.432 51.756 54.456 51.84 ;
    END
  END d[326]
  PIN d[327]
    DIRECTION INPUT ;
    USE SIGNAL ;
    PORT
      LAYER M5 ;
        RECT  54.576 51.756 54.6 51.84 ;
    END
  END d[327]
  PIN d[328]
    DIRECTION INPUT ;
    USE SIGNAL ;
    PORT
      LAYER M5 ;
        RECT  54.72 51.756 54.744 51.84 ;
    END
  END d[328]
  PIN d[329]
    DIRECTION INPUT ;
    USE SIGNAL ;
    PORT
      LAYER M5 ;
        RECT  54.864 51.756 54.888 51.84 ;
    END
  END d[329]
  PIN d[32]
    DIRECTION INPUT ;
    USE SIGNAL ;
    PORT
      LAYER M5 ;
        RECT  11.952 51.756 11.976 51.84 ;
    END
  END d[32]
  PIN d[330]
    DIRECTION INPUT ;
    USE SIGNAL ;
    PORT
      LAYER M5 ;
        RECT  55.008 51.756 55.032 51.84 ;
    END
  END d[330]
  PIN d[331]
    DIRECTION INPUT ;
    USE SIGNAL ;
    PORT
      LAYER M5 ;
        RECT  55.152 51.756 55.176 51.84 ;
    END
  END d[331]
  PIN d[332]
    DIRECTION INPUT ;
    USE SIGNAL ;
    PORT
      LAYER M5 ;
        RECT  55.296 51.756 55.32 51.84 ;
    END
  END d[332]
  PIN d[333]
    DIRECTION INPUT ;
    USE SIGNAL ;
    PORT
      LAYER M5 ;
        RECT  55.44 51.756 55.464 51.84 ;
    END
  END d[333]
  PIN d[334]
    DIRECTION INPUT ;
    USE SIGNAL ;
    PORT
      LAYER M5 ;
        RECT  55.584 51.756 55.608 51.84 ;
    END
  END d[334]
  PIN d[335]
    DIRECTION INPUT ;
    USE SIGNAL ;
    PORT
      LAYER M5 ;
        RECT  55.872 51.756 55.896 51.84 ;
    END
  END d[335]
  PIN d[336]
    DIRECTION INPUT ;
    USE SIGNAL ;
    PORT
      LAYER M5 ;
        RECT  55.728 51.756 55.752 51.84 ;
    END
  END d[336]
  PIN d[337]
    DIRECTION INPUT ;
    USE SIGNAL ;
    PORT
      LAYER M5 ;
        RECT  56.16 51.756 56.184 51.84 ;
    END
  END d[337]
  PIN d[338]
    DIRECTION INPUT ;
    USE SIGNAL ;
    PORT
      LAYER M5 ;
        RECT  56.016 51.756 56.04 51.84 ;
    END
  END d[338]
  PIN d[339]
    DIRECTION INPUT ;
    USE SIGNAL ;
    PORT
      LAYER M5 ;
        RECT  56.448 51.756 56.472 51.84 ;
    END
  END d[339]
  PIN d[33]
    DIRECTION INPUT ;
    USE SIGNAL ;
    PORT
      LAYER M5 ;
        RECT  11.808 51.756 11.832 51.84 ;
    END
  END d[33]
  PIN d[340]
    DIRECTION INPUT ;
    USE SIGNAL ;
    PORT
      LAYER M5 ;
        RECT  56.304 51.756 56.328 51.84 ;
    END
  END d[340]
  PIN d[341]
    DIRECTION INPUT ;
    USE SIGNAL ;
    PORT
      LAYER M5 ;
        RECT  56.736 51.756 56.76 51.84 ;
    END
  END d[341]
  PIN d[342]
    DIRECTION INPUT ;
    USE SIGNAL ;
    PORT
      LAYER M5 ;
        RECT  56.592 51.756 56.616 51.84 ;
    END
  END d[342]
  PIN d[343]
    DIRECTION INPUT ;
    USE SIGNAL ;
    PORT
      LAYER M5 ;
        RECT  57.024 51.756 57.048 51.84 ;
    END
  END d[343]
  PIN d[344]
    DIRECTION INPUT ;
    USE SIGNAL ;
    PORT
      LAYER M5 ;
        RECT  56.88 51.756 56.904 51.84 ;
    END
  END d[344]
  PIN d[345]
    DIRECTION INPUT ;
    USE SIGNAL ;
    PORT
      LAYER M5 ;
        RECT  57.312 51.756 57.336 51.84 ;
    END
  END d[345]
  PIN d[346]
    DIRECTION INPUT ;
    USE SIGNAL ;
    PORT
      LAYER M5 ;
        RECT  57.168 51.756 57.192 51.84 ;
    END
  END d[346]
  PIN d[347]
    DIRECTION INPUT ;
    USE SIGNAL ;
    PORT
      LAYER M5 ;
        RECT  57.6 51.756 57.624 51.84 ;
    END
  END d[347]
  PIN d[348]
    DIRECTION INPUT ;
    USE SIGNAL ;
    PORT
      LAYER M5 ;
        RECT  57.456 51.756 57.48 51.84 ;
    END
  END d[348]
  PIN d[349]
    DIRECTION INPUT ;
    USE SIGNAL ;
    PORT
      LAYER M5 ;
        RECT  58.032 51.756 58.056 51.84 ;
    END
  END d[349]
  PIN d[34]
    DIRECTION INPUT ;
    USE SIGNAL ;
    PORT
      LAYER M5 ;
        RECT  12.24 51.756 12.264 51.84 ;
    END
  END d[34]
  PIN d[350]
    DIRECTION INPUT ;
    USE SIGNAL ;
    PORT
      LAYER M5 ;
        RECT  57.744 51.756 57.768 51.84 ;
    END
  END d[350]
  PIN d[351]
    DIRECTION INPUT ;
    USE SIGNAL ;
    PORT
      LAYER M5 ;
        RECT  58.176 51.756 58.2 51.84 ;
    END
  END d[351]
  PIN d[352]
    DIRECTION INPUT ;
    USE SIGNAL ;
    PORT
      LAYER M5 ;
        RECT  57.888 51.756 57.912 51.84 ;
    END
  END d[352]
  PIN d[353]
    DIRECTION INPUT ;
    USE SIGNAL ;
    PORT
      LAYER M5 ;
        RECT  58.608 51.756 58.632 51.84 ;
    END
  END d[353]
  PIN d[354]
    DIRECTION INPUT ;
    USE SIGNAL ;
    PORT
      LAYER M5 ;
        RECT  58.32 51.756 58.344 51.84 ;
    END
  END d[354]
  PIN d[355]
    DIRECTION INPUT ;
    USE SIGNAL ;
    PORT
      LAYER M5 ;
        RECT  58.896 51.756 58.92 51.84 ;
    END
  END d[355]
  PIN d[356]
    DIRECTION INPUT ;
    USE SIGNAL ;
    PORT
      LAYER M5 ;
        RECT  58.464 51.756 58.488 51.84 ;
    END
  END d[356]
  PIN d[357]
    DIRECTION INPUT ;
    USE SIGNAL ;
    PORT
      LAYER M5 ;
        RECT  59.184 51.756 59.208 51.84 ;
    END
  END d[357]
  PIN d[358]
    DIRECTION INPUT ;
    USE SIGNAL ;
    PORT
      LAYER M5 ;
        RECT  58.752 51.756 58.776 51.84 ;
    END
  END d[358]
  PIN d[359]
    DIRECTION INPUT ;
    USE SIGNAL ;
    PORT
      LAYER M5 ;
        RECT  59.472 51.756 59.496 51.84 ;
    END
  END d[359]
  PIN d[35]
    DIRECTION INPUT ;
    USE SIGNAL ;
    PORT
      LAYER M5 ;
        RECT  12.096 51.756 12.12 51.84 ;
    END
  END d[35]
  PIN d[360]
    DIRECTION INPUT ;
    USE SIGNAL ;
    PORT
      LAYER M5 ;
        RECT  59.04 51.756 59.064 51.84 ;
    END
  END d[360]
  PIN d[361]
    DIRECTION INPUT ;
    USE SIGNAL ;
    PORT
      LAYER M5 ;
        RECT  59.616 51.756 59.64 51.84 ;
    END
  END d[361]
  PIN d[362]
    DIRECTION INPUT ;
    USE SIGNAL ;
    PORT
      LAYER M5 ;
        RECT  59.328 51.756 59.352 51.84 ;
    END
  END d[362]
  PIN d[363]
    DIRECTION INPUT ;
    USE SIGNAL ;
    PORT
      LAYER M5 ;
        RECT  59.76 51.756 59.784 51.84 ;
    END
  END d[363]
  PIN d[364]
    DIRECTION INPUT ;
    USE SIGNAL ;
    PORT
      LAYER M5 ;
        RECT  60.048 51.756 60.072 51.84 ;
    END
  END d[364]
  PIN d[365]
    DIRECTION INPUT ;
    USE SIGNAL ;
    PORT
      LAYER M5 ;
        RECT  59.904 51.756 59.928 51.84 ;
    END
  END d[365]
  PIN d[366]
    DIRECTION INPUT ;
    USE SIGNAL ;
    PORT
      LAYER M5 ;
        RECT  60.336 51.756 60.36 51.84 ;
    END
  END d[366]
  PIN d[367]
    DIRECTION INPUT ;
    USE SIGNAL ;
    PORT
      LAYER M5 ;
        RECT  60.192 51.756 60.216 51.84 ;
    END
  END d[367]
  PIN d[368]
    DIRECTION INPUT ;
    USE SIGNAL ;
    PORT
      LAYER M5 ;
        RECT  60.624 51.756 60.648 51.84 ;
    END
  END d[368]
  PIN d[369]
    DIRECTION INPUT ;
    USE SIGNAL ;
    PORT
      LAYER M5 ;
        RECT  60.48 51.756 60.504 51.84 ;
    END
  END d[369]
  PIN d[36]
    DIRECTION INPUT ;
    USE SIGNAL ;
    PORT
      LAYER M5 ;
        RECT  12.528 51.756 12.552 51.84 ;
    END
  END d[36]
  PIN d[370]
    DIRECTION INPUT ;
    USE SIGNAL ;
    PORT
      LAYER M5 ;
        RECT  60.768 51.756 60.792 51.84 ;
    END
  END d[370]
  PIN d[371]
    DIRECTION INPUT ;
    USE SIGNAL ;
    PORT
      LAYER M5 ;
        RECT  60.912 51.756 60.936 51.84 ;
    END
  END d[371]
  PIN d[372]
    DIRECTION INPUT ;
    USE SIGNAL ;
    PORT
      LAYER M5 ;
        RECT  61.2 51.756 61.224 51.84 ;
    END
  END d[372]
  PIN d[373]
    DIRECTION INPUT ;
    USE SIGNAL ;
    PORT
      LAYER M5 ;
        RECT  61.056 51.756 61.08 51.84 ;
    END
  END d[373]
  PIN d[374]
    DIRECTION INPUT ;
    USE SIGNAL ;
    PORT
      LAYER M5 ;
        RECT  61.344 51.756 61.368 51.84 ;
    END
  END d[374]
  PIN d[375]
    DIRECTION INPUT ;
    USE SIGNAL ;
    PORT
      LAYER M5 ;
        RECT  61.488 51.756 61.512 51.84 ;
    END
  END d[375]
  PIN d[376]
    DIRECTION INPUT ;
    USE SIGNAL ;
    PORT
      LAYER M5 ;
        RECT  61.632 51.756 61.656 51.84 ;
    END
  END d[376]
  PIN d[377]
    DIRECTION INPUT ;
    USE SIGNAL ;
    PORT
      LAYER M5 ;
        RECT  61.776 51.756 61.8 51.84 ;
    END
  END d[377]
  PIN d[378]
    DIRECTION INPUT ;
    USE SIGNAL ;
    PORT
      LAYER M5 ;
        RECT  61.92 51.756 61.944 51.84 ;
    END
  END d[378]
  PIN d[379]
    DIRECTION INPUT ;
    USE SIGNAL ;
    PORT
      LAYER M5 ;
        RECT  62.064 51.756 62.088 51.84 ;
    END
  END d[379]
  PIN d[37]
    DIRECTION INPUT ;
    USE SIGNAL ;
    PORT
      LAYER M5 ;
        RECT  12.384 51.756 12.408 51.84 ;
    END
  END d[37]
  PIN d[380]
    DIRECTION INPUT ;
    USE SIGNAL ;
    PORT
      LAYER M5 ;
        RECT  62.208 51.756 62.232 51.84 ;
    END
  END d[380]
  PIN d[381]
    DIRECTION INPUT ;
    USE SIGNAL ;
    PORT
      LAYER M5 ;
        RECT  62.352 51.756 62.376 51.84 ;
    END
  END d[381]
  PIN d[382]
    DIRECTION INPUT ;
    USE SIGNAL ;
    PORT
      LAYER M5 ;
        RECT  62.496 51.756 62.52 51.84 ;
    END
  END d[382]
  PIN d[383]
    DIRECTION INPUT ;
    USE SIGNAL ;
    PORT
      LAYER M5 ;
        RECT  62.64 51.756 62.664 51.84 ;
    END
  END d[383]
  PIN d[384]
    DIRECTION INPUT ;
    USE SIGNAL ;
    PORT
      LAYER M5 ;
        RECT  62.784 51.756 62.808 51.84 ;
    END
  END d[384]
  PIN d[385]
    DIRECTION INPUT ;
    USE SIGNAL ;
    PORT
      LAYER M5 ;
        RECT  63.072 51.756 63.096 51.84 ;
    END
  END d[385]
  PIN d[386]
    DIRECTION INPUT ;
    USE SIGNAL ;
    PORT
      LAYER M5 ;
        RECT  62.928 51.756 62.952 51.84 ;
    END
  END d[386]
  PIN d[387]
    DIRECTION INPUT ;
    USE SIGNAL ;
    PORT
      LAYER M5 ;
        RECT  63.36 51.756 63.384 51.84 ;
    END
  END d[387]
  PIN d[388]
    DIRECTION INPUT ;
    USE SIGNAL ;
    PORT
      LAYER M5 ;
        RECT  63.216 51.756 63.24 51.84 ;
    END
  END d[388]
  PIN d[389]
    DIRECTION INPUT ;
    USE SIGNAL ;
    PORT
      LAYER M5 ;
        RECT  63.648 51.756 63.672 51.84 ;
    END
  END d[389]
  PIN d[38]
    DIRECTION INPUT ;
    USE SIGNAL ;
    PORT
      LAYER M5 ;
        RECT  12.672 51.756 12.696 51.84 ;
    END
  END d[38]
  PIN d[390]
    DIRECTION INPUT ;
    USE SIGNAL ;
    PORT
      LAYER M5 ;
        RECT  63.504 51.756 63.528 51.84 ;
    END
  END d[390]
  PIN d[391]
    DIRECTION INPUT ;
    USE SIGNAL ;
    PORT
      LAYER M5 ;
        RECT  63.936 51.756 63.96 51.84 ;
    END
  END d[391]
  PIN d[392]
    DIRECTION INPUT ;
    USE SIGNAL ;
    PORT
      LAYER M5 ;
        RECT  63.792 51.756 63.816 51.84 ;
    END
  END d[392]
  PIN d[393]
    DIRECTION INPUT ;
    USE SIGNAL ;
    PORT
      LAYER M5 ;
        RECT  64.224 51.756 64.248 51.84 ;
    END
  END d[393]
  PIN d[394]
    DIRECTION INPUT ;
    USE SIGNAL ;
    PORT
      LAYER M5 ;
        RECT  64.08 51.756 64.104 51.84 ;
    END
  END d[394]
  PIN d[395]
    DIRECTION INPUT ;
    USE SIGNAL ;
    PORT
      LAYER M5 ;
        RECT  64.512 51.756 64.536 51.84 ;
    END
  END d[395]
  PIN d[396]
    DIRECTION INPUT ;
    USE SIGNAL ;
    PORT
      LAYER M5 ;
        RECT  64.368 51.756 64.392 51.84 ;
    END
  END d[396]
  PIN d[397]
    DIRECTION INPUT ;
    USE SIGNAL ;
    PORT
      LAYER M5 ;
        RECT  64.8 51.756 64.824 51.84 ;
    END
  END d[397]
  PIN d[398]
    DIRECTION INPUT ;
    USE SIGNAL ;
    PORT
      LAYER M5 ;
        RECT  64.656 51.756 64.68 51.84 ;
    END
  END d[398]
  PIN d[399]
    DIRECTION INPUT ;
    USE SIGNAL ;
    PORT
      LAYER M5 ;
        RECT  65.232 51.756 65.256 51.84 ;
    END
  END d[399]
  PIN d[39]
    DIRECTION INPUT ;
    USE SIGNAL ;
    PORT
      LAYER M5 ;
        RECT  12.816 51.756 12.84 51.84 ;
    END
  END d[39]
  PIN d[3]
    DIRECTION INPUT ;
    USE SIGNAL ;
    PORT
      LAYER M5 ;
        RECT  7.632 51.756 7.656 51.84 ;
    END
  END d[3]
  PIN d[400]
    DIRECTION INPUT ;
    USE SIGNAL ;
    PORT
      LAYER M5 ;
        RECT  64.944 51.756 64.968 51.84 ;
    END
  END d[400]
  PIN d[401]
    DIRECTION INPUT ;
    USE SIGNAL ;
    PORT
      LAYER M5 ;
        RECT  65.52 51.756 65.544 51.84 ;
    END
  END d[401]
  PIN d[402]
    DIRECTION INPUT ;
    USE SIGNAL ;
    PORT
      LAYER M5 ;
        RECT  65.088 51.756 65.112 51.84 ;
    END
  END d[402]
  PIN d[403]
    DIRECTION INPUT ;
    USE SIGNAL ;
    PORT
      LAYER M5 ;
        RECT  65.808 51.756 65.832 51.84 ;
    END
  END d[403]
  PIN d[404]
    DIRECTION INPUT ;
    USE SIGNAL ;
    PORT
      LAYER M5 ;
        RECT  65.376 51.756 65.4 51.84 ;
    END
  END d[404]
  PIN d[405]
    DIRECTION INPUT ;
    USE SIGNAL ;
    PORT
      LAYER M5 ;
        RECT  66.096 51.756 66.12 51.84 ;
    END
  END d[405]
  PIN d[406]
    DIRECTION INPUT ;
    USE SIGNAL ;
    PORT
      LAYER M5 ;
        RECT  65.664 51.756 65.688 51.84 ;
    END
  END d[406]
  PIN d[407]
    DIRECTION INPUT ;
    USE SIGNAL ;
    PORT
      LAYER M5 ;
        RECT  66.384 51.756 66.408 51.84 ;
    END
  END d[407]
  PIN d[408]
    DIRECTION INPUT ;
    USE SIGNAL ;
    PORT
      LAYER M5 ;
        RECT  65.952 51.756 65.976 51.84 ;
    END
  END d[408]
  PIN d[409]
    DIRECTION INPUT ;
    USE SIGNAL ;
    PORT
      LAYER M5 ;
        RECT  66.672 51.756 66.696 51.84 ;
    END
  END d[409]
  PIN d[40]
    DIRECTION INPUT ;
    USE SIGNAL ;
    PORT
      LAYER M5 ;
        RECT  12.96 51.756 12.984 51.84 ;
    END
  END d[40]
  PIN d[410]
    DIRECTION INPUT ;
    USE SIGNAL ;
    PORT
      LAYER M5 ;
        RECT  66.24 51.756 66.264 51.84 ;
    END
  END d[410]
  PIN d[411]
    DIRECTION INPUT ;
    USE SIGNAL ;
    PORT
      LAYER M5 ;
        RECT  66.816 51.756 66.84 51.84 ;
    END
  END d[411]
  PIN d[412]
    DIRECTION INPUT ;
    USE SIGNAL ;
    PORT
      LAYER M5 ;
        RECT  66.528 51.756 66.552 51.84 ;
    END
  END d[412]
  PIN d[413]
    DIRECTION INPUT ;
    USE SIGNAL ;
    PORT
      LAYER M5 ;
        RECT  66.96 51.756 66.984 51.84 ;
    END
  END d[413]
  PIN d[414]
    DIRECTION INPUT ;
    USE SIGNAL ;
    PORT
      LAYER M5 ;
        RECT  67.104 51.756 67.128 51.84 ;
    END
  END d[414]
  PIN d[415]
    DIRECTION INPUT ;
    USE SIGNAL ;
    PORT
      LAYER M5 ;
        RECT  67.248 51.756 67.272 51.84 ;
    END
  END d[415]
  PIN d[416]
    DIRECTION INPUT ;
    USE SIGNAL ;
    PORT
      LAYER M5 ;
        RECT  67.392 51.756 67.416 51.84 ;
    END
  END d[416]
  PIN d[417]
    DIRECTION INPUT ;
    USE SIGNAL ;
    PORT
      LAYER M5 ;
        RECT  67.536 51.756 67.56 51.84 ;
    END
  END d[417]
  PIN d[418]
    DIRECTION INPUT ;
    USE SIGNAL ;
    PORT
      LAYER M5 ;
        RECT  67.68 51.756 67.704 51.84 ;
    END
  END d[418]
  PIN d[419]
    DIRECTION INPUT ;
    USE SIGNAL ;
    PORT
      LAYER M5 ;
        RECT  67.824 51.756 67.848 51.84 ;
    END
  END d[419]
  PIN d[41]
    DIRECTION INPUT ;
    USE SIGNAL ;
    PORT
      LAYER M5 ;
        RECT  13.104 51.756 13.128 51.84 ;
    END
  END d[41]
  PIN d[420]
    DIRECTION INPUT ;
    USE SIGNAL ;
    PORT
      LAYER M5 ;
        RECT  67.968 51.756 67.992 51.84 ;
    END
  END d[420]
  PIN d[421]
    DIRECTION INPUT ;
    USE SIGNAL ;
    PORT
      LAYER M5 ;
        RECT  68.112 51.756 68.136 51.84 ;
    END
  END d[421]
  PIN d[422]
    DIRECTION INPUT ;
    USE SIGNAL ;
    PORT
      LAYER M5 ;
        RECT  68.256 51.756 68.28 51.84 ;
    END
  END d[422]
  PIN d[423]
    DIRECTION INPUT ;
    USE SIGNAL ;
    PORT
      LAYER M5 ;
        RECT  68.4 51.756 68.424 51.84 ;
    END
  END d[423]
  PIN d[424]
    DIRECTION INPUT ;
    USE SIGNAL ;
    PORT
      LAYER M5 ;
        RECT  68.544 51.756 68.568 51.84 ;
    END
  END d[424]
  PIN d[425]
    DIRECTION INPUT ;
    USE SIGNAL ;
    PORT
      LAYER M5 ;
        RECT  68.688 51.756 68.712 51.84 ;
    END
  END d[425]
  PIN d[426]
    DIRECTION INPUT ;
    USE SIGNAL ;
    PORT
      LAYER M5 ;
        RECT  68.832 51.756 68.856 51.84 ;
    END
  END d[426]
  PIN d[427]
    DIRECTION INPUT ;
    USE SIGNAL ;
    PORT
      LAYER M5 ;
        RECT  68.976 51.756 69 51.84 ;
    END
  END d[427]
  PIN d[428]
    DIRECTION INPUT ;
    USE SIGNAL ;
    PORT
      LAYER M5 ;
        RECT  69.12 51.756 69.144 51.84 ;
    END
  END d[428]
  PIN d[429]
    DIRECTION INPUT ;
    USE SIGNAL ;
    PORT
      LAYER M5 ;
        RECT  69.408 51.756 69.432 51.84 ;
    END
  END d[429]
  PIN d[42]
    DIRECTION INPUT ;
    USE SIGNAL ;
    PORT
      LAYER M5 ;
        RECT  13.248 51.756 13.272 51.84 ;
    END
  END d[42]
  PIN d[430]
    DIRECTION INPUT ;
    USE SIGNAL ;
    PORT
      LAYER M5 ;
        RECT  69.264 51.756 69.288 51.84 ;
    END
  END d[430]
  PIN d[431]
    DIRECTION INPUT ;
    USE SIGNAL ;
    PORT
      LAYER M5 ;
        RECT  69.696 51.756 69.72 51.84 ;
    END
  END d[431]
  PIN d[432]
    DIRECTION INPUT ;
    USE SIGNAL ;
    PORT
      LAYER M5 ;
        RECT  69.552 51.756 69.576 51.84 ;
    END
  END d[432]
  PIN d[433]
    DIRECTION INPUT ;
    USE SIGNAL ;
    PORT
      LAYER M5 ;
        RECT  69.984 51.756 70.008 51.84 ;
    END
  END d[433]
  PIN d[434]
    DIRECTION INPUT ;
    USE SIGNAL ;
    PORT
      LAYER M5 ;
        RECT  69.84 51.756 69.864 51.84 ;
    END
  END d[434]
  PIN d[435]
    DIRECTION INPUT ;
    USE SIGNAL ;
    PORT
      LAYER M5 ;
        RECT  70.272 51.756 70.296 51.84 ;
    END
  END d[435]
  PIN d[436]
    DIRECTION INPUT ;
    USE SIGNAL ;
    PORT
      LAYER M5 ;
        RECT  70.128 51.756 70.152 51.84 ;
    END
  END d[436]
  PIN d[437]
    DIRECTION INPUT ;
    USE SIGNAL ;
    PORT
      LAYER M5 ;
        RECT  70.56 51.756 70.584 51.84 ;
    END
  END d[437]
  PIN d[438]
    DIRECTION INPUT ;
    USE SIGNAL ;
    PORT
      LAYER M5 ;
        RECT  70.416 51.756 70.44 51.84 ;
    END
  END d[438]
  PIN d[439]
    DIRECTION INPUT ;
    USE SIGNAL ;
    PORT
      LAYER M5 ;
        RECT  70.848 51.756 70.872 51.84 ;
    END
  END d[439]
  PIN d[43]
    DIRECTION INPUT ;
    USE SIGNAL ;
    PORT
      LAYER M5 ;
        RECT  13.392 51.756 13.416 51.84 ;
    END
  END d[43]
  PIN d[440]
    DIRECTION INPUT ;
    USE SIGNAL ;
    PORT
      LAYER M5 ;
        RECT  70.704 51.756 70.728 51.84 ;
    END
  END d[440]
  PIN d[441]
    DIRECTION INPUT ;
    USE SIGNAL ;
    PORT
      LAYER M5 ;
        RECT  71.136 51.756 71.16 51.84 ;
    END
  END d[441]
  PIN d[442]
    DIRECTION INPUT ;
    USE SIGNAL ;
    PORT
      LAYER M5 ;
        RECT  70.992 51.756 71.016 51.84 ;
    END
  END d[442]
  PIN d[443]
    DIRECTION INPUT ;
    USE SIGNAL ;
    PORT
      LAYER M5 ;
        RECT  71.424 51.756 71.448 51.84 ;
    END
  END d[443]
  PIN d[444]
    DIRECTION INPUT ;
    USE SIGNAL ;
    PORT
      LAYER M5 ;
        RECT  71.28 51.756 71.304 51.84 ;
    END
  END d[444]
  PIN d[445]
    DIRECTION INPUT ;
    USE SIGNAL ;
    PORT
      LAYER M5 ;
        RECT  71.856 51.756 71.88 51.84 ;
    END
  END d[445]
  PIN d[446]
    DIRECTION INPUT ;
    USE SIGNAL ;
    PORT
      LAYER M5 ;
        RECT  71.568 51.756 71.592 51.84 ;
    END
  END d[446]
  PIN d[447]
    DIRECTION INPUT ;
    USE SIGNAL ;
    PORT
      LAYER M5 ;
        RECT  72.144 51.756 72.168 51.84 ;
    END
  END d[447]
  PIN d[448]
    DIRECTION INPUT ;
    USE SIGNAL ;
    PORT
      LAYER M5 ;
        RECT  71.712 51.756 71.736 51.84 ;
    END
  END d[448]
  PIN d[449]
    DIRECTION INPUT ;
    USE SIGNAL ;
    PORT
      LAYER M5 ;
        RECT  72.432 51.756 72.456 51.84 ;
    END
  END d[449]
  PIN d[44]
    DIRECTION INPUT ;
    USE SIGNAL ;
    PORT
      LAYER M5 ;
        RECT  13.536 51.756 13.56 51.84 ;
    END
  END d[44]
  PIN d[450]
    DIRECTION INPUT ;
    USE SIGNAL ;
    PORT
      LAYER M5 ;
        RECT  72 51.756 72.024 51.84 ;
    END
  END d[450]
  PIN d[451]
    DIRECTION INPUT ;
    USE SIGNAL ;
    PORT
      LAYER M5 ;
        RECT  72.72 51.756 72.744 51.84 ;
    END
  END d[451]
  PIN d[452]
    DIRECTION INPUT ;
    USE SIGNAL ;
    PORT
      LAYER M5 ;
        RECT  72.288 51.756 72.312 51.84 ;
    END
  END d[452]
  PIN d[453]
    DIRECTION INPUT ;
    USE SIGNAL ;
    PORT
      LAYER M5 ;
        RECT  73.008 51.756 73.032 51.84 ;
    END
  END d[453]
  PIN d[454]
    DIRECTION INPUT ;
    USE SIGNAL ;
    PORT
      LAYER M5 ;
        RECT  72.576 51.756 72.6 51.84 ;
    END
  END d[454]
  PIN d[455]
    DIRECTION INPUT ;
    USE SIGNAL ;
    PORT
      LAYER M5 ;
        RECT  73.296 51.756 73.32 51.84 ;
    END
  END d[455]
  PIN d[456]
    DIRECTION INPUT ;
    USE SIGNAL ;
    PORT
      LAYER M5 ;
        RECT  72.864 51.756 72.888 51.84 ;
    END
  END d[456]
  PIN d[457]
    DIRECTION INPUT ;
    USE SIGNAL ;
    PORT
      LAYER M5 ;
        RECT  73.584 51.756 73.608 51.84 ;
    END
  END d[457]
  PIN d[458]
    DIRECTION INPUT ;
    USE SIGNAL ;
    PORT
      LAYER M5 ;
        RECT  73.152 51.756 73.176 51.84 ;
    END
  END d[458]
  PIN d[459]
    DIRECTION INPUT ;
    USE SIGNAL ;
    PORT
      LAYER M5 ;
        RECT  73.872 51.756 73.896 51.84 ;
    END
  END d[459]
  PIN d[45]
    DIRECTION INPUT ;
    USE SIGNAL ;
    PORT
      LAYER M5 ;
        RECT  13.68 51.756 13.704 51.84 ;
    END
  END d[45]
  PIN d[460]
    DIRECTION INPUT ;
    USE SIGNAL ;
    PORT
      LAYER M5 ;
        RECT  73.44 51.756 73.464 51.84 ;
    END
  END d[460]
  PIN d[461]
    DIRECTION INPUT ;
    USE SIGNAL ;
    PORT
      LAYER M5 ;
        RECT  74.016 51.756 74.04 51.84 ;
    END
  END d[461]
  PIN d[462]
    DIRECTION INPUT ;
    USE SIGNAL ;
    PORT
      LAYER M5 ;
        RECT  73.728 51.756 73.752 51.84 ;
    END
  END d[462]
  PIN d[463]
    DIRECTION INPUT ;
    USE SIGNAL ;
    PORT
      LAYER M5 ;
        RECT  74.16 51.756 74.184 51.84 ;
    END
  END d[463]
  PIN d[464]
    DIRECTION INPUT ;
    USE SIGNAL ;
    PORT
      LAYER M5 ;
        RECT  74.304 51.756 74.328 51.84 ;
    END
  END d[464]
  PIN d[465]
    DIRECTION INPUT ;
    USE SIGNAL ;
    PORT
      LAYER M5 ;
        RECT  74.448 51.756 74.472 51.84 ;
    END
  END d[465]
  PIN d[466]
    DIRECTION INPUT ;
    USE SIGNAL ;
    PORT
      LAYER M5 ;
        RECT  74.592 51.756 74.616 51.84 ;
    END
  END d[466]
  PIN d[467]
    DIRECTION INPUT ;
    USE SIGNAL ;
    PORT
      LAYER M5 ;
        RECT  74.736 51.756 74.76 51.84 ;
    END
  END d[467]
  PIN d[468]
    DIRECTION INPUT ;
    USE SIGNAL ;
    PORT
      LAYER M5 ;
        RECT  74.88 51.756 74.904 51.84 ;
    END
  END d[468]
  PIN d[469]
    DIRECTION INPUT ;
    USE SIGNAL ;
    PORT
      LAYER M5 ;
        RECT  75.024 51.756 75.048 51.84 ;
    END
  END d[469]
  PIN d[46]
    DIRECTION INPUT ;
    USE SIGNAL ;
    PORT
      LAYER M5 ;
        RECT  13.824 51.756 13.848 51.84 ;
    END
  END d[46]
  PIN d[470]
    DIRECTION INPUT ;
    USE SIGNAL ;
    PORT
      LAYER M5 ;
        RECT  75.168 51.756 75.192 51.84 ;
    END
  END d[470]
  PIN d[471]
    DIRECTION INPUT ;
    USE SIGNAL ;
    PORT
      LAYER M5 ;
        RECT  75.312 51.756 75.336 51.84 ;
    END
  END d[471]
  PIN d[472]
    DIRECTION INPUT ;
    USE SIGNAL ;
    PORT
      LAYER M5 ;
        RECT  75.456 51.756 75.48 51.84 ;
    END
  END d[472]
  PIN d[473]
    DIRECTION INPUT ;
    USE SIGNAL ;
    PORT
      LAYER M5 ;
        RECT  75.6 51.756 75.624 51.84 ;
    END
  END d[473]
  PIN d[474]
    DIRECTION INPUT ;
    USE SIGNAL ;
    PORT
      LAYER M5 ;
        RECT  75.744 51.756 75.768 51.84 ;
    END
  END d[474]
  PIN d[475]
    DIRECTION INPUT ;
    USE SIGNAL ;
    PORT
      LAYER M5 ;
        RECT  75.888 51.756 75.912 51.84 ;
    END
  END d[475]
  PIN d[476]
    DIRECTION INPUT ;
    USE SIGNAL ;
    PORT
      LAYER M5 ;
        RECT  76.032 51.756 76.056 51.84 ;
    END
  END d[476]
  PIN d[477]
    DIRECTION INPUT ;
    USE SIGNAL ;
    PORT
      LAYER M5 ;
        RECT  76.32 51.756 76.344 51.84 ;
    END
  END d[477]
  PIN d[478]
    DIRECTION INPUT ;
    USE SIGNAL ;
    PORT
      LAYER M5 ;
        RECT  76.176 51.756 76.2 51.84 ;
    END
  END d[478]
  PIN d[479]
    DIRECTION INPUT ;
    USE SIGNAL ;
    PORT
      LAYER M5 ;
        RECT  76.608 51.756 76.632 51.84 ;
    END
  END d[479]
  PIN d[47]
    DIRECTION INPUT ;
    USE SIGNAL ;
    PORT
      LAYER M5 ;
        RECT  13.968 51.756 13.992 51.84 ;
    END
  END d[47]
  PIN d[480]
    DIRECTION INPUT ;
    USE SIGNAL ;
    PORT
      LAYER M5 ;
        RECT  76.464 51.756 76.488 51.84 ;
    END
  END d[480]
  PIN d[481]
    DIRECTION INPUT ;
    USE SIGNAL ;
    PORT
      LAYER M5 ;
        RECT  76.896 51.756 76.92 51.84 ;
    END
  END d[481]
  PIN d[482]
    DIRECTION INPUT ;
    USE SIGNAL ;
    PORT
      LAYER M5 ;
        RECT  76.752 51.756 76.776 51.84 ;
    END
  END d[482]
  PIN d[483]
    DIRECTION INPUT ;
    USE SIGNAL ;
    PORT
      LAYER M5 ;
        RECT  77.184 51.756 77.208 51.84 ;
    END
  END d[483]
  PIN d[484]
    DIRECTION INPUT ;
    USE SIGNAL ;
    PORT
      LAYER M5 ;
        RECT  77.04 51.756 77.064 51.84 ;
    END
  END d[484]
  PIN d[485]
    DIRECTION INPUT ;
    USE SIGNAL ;
    PORT
      LAYER M5 ;
        RECT  77.472 51.756 77.496 51.84 ;
    END
  END d[485]
  PIN d[486]
    DIRECTION INPUT ;
    USE SIGNAL ;
    PORT
      LAYER M5 ;
        RECT  77.328 51.756 77.352 51.84 ;
    END
  END d[486]
  PIN d[487]
    DIRECTION INPUT ;
    USE SIGNAL ;
    PORT
      LAYER M5 ;
        RECT  77.76 51.756 77.784 51.84 ;
    END
  END d[487]
  PIN d[488]
    DIRECTION INPUT ;
    USE SIGNAL ;
    PORT
      LAYER M5 ;
        RECT  77.616 51.756 77.64 51.84 ;
    END
  END d[488]
  PIN d[489]
    DIRECTION INPUT ;
    USE SIGNAL ;
    PORT
      LAYER M5 ;
        RECT  78.048 51.756 78.072 51.84 ;
    END
  END d[489]
  PIN d[48]
    DIRECTION INPUT ;
    USE SIGNAL ;
    PORT
      LAYER M5 ;
        RECT  14.112 51.756 14.136 51.84 ;
    END
  END d[48]
  PIN d[490]
    DIRECTION INPUT ;
    USE SIGNAL ;
    PORT
      LAYER M5 ;
        RECT  77.904 51.756 77.928 51.84 ;
    END
  END d[490]
  PIN d[491]
    DIRECTION INPUT ;
    USE SIGNAL ;
    PORT
      LAYER M5 ;
        RECT  78.336 51.756 78.36 51.84 ;
    END
  END d[491]
  PIN d[492]
    DIRECTION INPUT ;
    USE SIGNAL ;
    PORT
      LAYER M5 ;
        RECT  78.192 51.756 78.216 51.84 ;
    END
  END d[492]
  PIN d[493]
    DIRECTION INPUT ;
    USE SIGNAL ;
    PORT
      LAYER M5 ;
        RECT  78.768 51.756 78.792 51.84 ;
    END
  END d[493]
  PIN d[494]
    DIRECTION INPUT ;
    USE SIGNAL ;
    PORT
      LAYER M5 ;
        RECT  78.48 51.756 78.504 51.84 ;
    END
  END d[494]
  PIN d[495]
    DIRECTION INPUT ;
    USE SIGNAL ;
    PORT
      LAYER M5 ;
        RECT  79.056 51.756 79.08 51.84 ;
    END
  END d[495]
  PIN d[496]
    DIRECTION INPUT ;
    USE SIGNAL ;
    PORT
      LAYER M5 ;
        RECT  78.624 51.756 78.648 51.84 ;
    END
  END d[496]
  PIN d[497]
    DIRECTION INPUT ;
    USE SIGNAL ;
    PORT
      LAYER M5 ;
        RECT  79.344 51.756 79.368 51.84 ;
    END
  END d[497]
  PIN d[498]
    DIRECTION INPUT ;
    USE SIGNAL ;
    PORT
      LAYER M5 ;
        RECT  78.912 51.756 78.936 51.84 ;
    END
  END d[498]
  PIN d[499]
    DIRECTION INPUT ;
    USE SIGNAL ;
    PORT
      LAYER M5 ;
        RECT  79.776 51.756 79.8 51.84 ;
    END
  END d[499]
  PIN d[49]
    DIRECTION INPUT ;
    USE SIGNAL ;
    PORT
      LAYER M5 ;
        RECT  14.256 51.756 14.28 51.84 ;
    END
  END d[49]
  PIN d[4]
    DIRECTION INPUT ;
    USE SIGNAL ;
    PORT
      LAYER M5 ;
        RECT  7.776 51.756 7.8 51.84 ;
    END
  END d[4]
  PIN d[500]
    DIRECTION INPUT ;
    USE SIGNAL ;
    PORT
      LAYER M5 ;
        RECT  79.2 51.756 79.224 51.84 ;
    END
  END d[500]
  PIN d[501]
    DIRECTION INPUT ;
    USE SIGNAL ;
    PORT
      LAYER M5 ;
        RECT  79.92 51.756 79.944 51.84 ;
    END
  END d[501]
  PIN d[502]
    DIRECTION INPUT ;
    USE SIGNAL ;
    PORT
      LAYER M5 ;
        RECT  79.488 51.756 79.512 51.84 ;
    END
  END d[502]
  PIN d[503]
    DIRECTION INPUT ;
    USE SIGNAL ;
    PORT
      LAYER M5 ;
        RECT  80.208 51.756 80.232 51.84 ;
    END
  END d[503]
  PIN d[504]
    DIRECTION INPUT ;
    USE SIGNAL ;
    PORT
      LAYER M5 ;
        RECT  79.632 51.756 79.656 51.84 ;
    END
  END d[504]
  PIN d[505]
    DIRECTION INPUT ;
    USE SIGNAL ;
    PORT
      LAYER M5 ;
        RECT  80.496 51.756 80.52 51.84 ;
    END
  END d[505]
  PIN d[506]
    DIRECTION INPUT ;
    USE SIGNAL ;
    PORT
      LAYER M5 ;
        RECT  80.064 51.756 80.088 51.84 ;
    END
  END d[506]
  PIN d[507]
    DIRECTION INPUT ;
    USE SIGNAL ;
    PORT
      LAYER M5 ;
        RECT  80.928 51.756 80.952 51.84 ;
    END
  END d[507]
  PIN d[508]
    DIRECTION INPUT ;
    USE SIGNAL ;
    PORT
      LAYER M5 ;
        RECT  80.352 51.756 80.376 51.84 ;
    END
  END d[508]
  PIN d[509]
    DIRECTION INPUT ;
    USE SIGNAL ;
    PORT
      LAYER M5 ;
        RECT  81.072 51.756 81.096 51.84 ;
    END
  END d[509]
  PIN d[50]
    DIRECTION INPUT ;
    USE SIGNAL ;
    PORT
      LAYER M5 ;
        RECT  14.4 51.756 14.424 51.84 ;
    END
  END d[50]
  PIN d[510]
    DIRECTION INPUT ;
    USE SIGNAL ;
    PORT
      LAYER M5 ;
        RECT  80.64 51.756 80.664 51.84 ;
    END
  END d[510]
  PIN d[511]
    DIRECTION INPUT ;
    USE SIGNAL ;
    PORT
      LAYER M5 ;
        RECT  81.216 51.756 81.24 51.84 ;
    END
  END d[511]
  PIN d[512]
    DIRECTION INPUT ;
    USE SIGNAL ;
    PORT
      LAYER M5 ;
        RECT  80.784 51.756 80.808 51.84 ;
    END
  END d[512]
  PIN d[513]
    DIRECTION INPUT ;
    USE SIGNAL ;
    PORT
      LAYER M5 ;
        RECT  81.36 51.756 81.384 51.84 ;
    END
  END d[513]
  PIN d[514]
    DIRECTION INPUT ;
    USE SIGNAL ;
    PORT
      LAYER M5 ;
        RECT  81.504 51.756 81.528 51.84 ;
    END
  END d[514]
  PIN d[515]
    DIRECTION INPUT ;
    USE SIGNAL ;
    PORT
      LAYER M5 ;
        RECT  81.648 51.756 81.672 51.84 ;
    END
  END d[515]
  PIN d[516]
    DIRECTION INPUT ;
    USE SIGNAL ;
    PORT
      LAYER M5 ;
        RECT  81.792 51.756 81.816 51.84 ;
    END
  END d[516]
  PIN d[51]
    DIRECTION INPUT ;
    USE SIGNAL ;
    PORT
      LAYER M5 ;
        RECT  14.544 51.756 14.568 51.84 ;
    END
  END d[51]
  PIN d[52]
    DIRECTION INPUT ;
    USE SIGNAL ;
    PORT
      LAYER M5 ;
        RECT  14.688 51.756 14.712 51.84 ;
    END
  END d[52]
  PIN d[53]
    DIRECTION INPUT ;
    USE SIGNAL ;
    PORT
      LAYER M5 ;
        RECT  14.976 51.756 15 51.84 ;
    END
  END d[53]
  PIN d[54]
    DIRECTION INPUT ;
    USE SIGNAL ;
    PORT
      LAYER M5 ;
        RECT  14.832 51.756 14.856 51.84 ;
    END
  END d[54]
  PIN d[55]
    DIRECTION INPUT ;
    USE SIGNAL ;
    PORT
      LAYER M5 ;
        RECT  15.264 51.756 15.288 51.84 ;
    END
  END d[55]
  PIN d[56]
    DIRECTION INPUT ;
    USE SIGNAL ;
    PORT
      LAYER M5 ;
        RECT  15.12 51.756 15.144 51.84 ;
    END
  END d[56]
  PIN d[57]
    DIRECTION INPUT ;
    USE SIGNAL ;
    PORT
      LAYER M5 ;
        RECT  15.552 51.756 15.576 51.84 ;
    END
  END d[57]
  PIN d[58]
    DIRECTION INPUT ;
    USE SIGNAL ;
    PORT
      LAYER M5 ;
        RECT  15.408 51.756 15.432 51.84 ;
    END
  END d[58]
  PIN d[59]
    DIRECTION INPUT ;
    USE SIGNAL ;
    PORT
      LAYER M5 ;
        RECT  15.84 51.756 15.864 51.84 ;
    END
  END d[59]
  PIN d[5]
    DIRECTION INPUT ;
    USE SIGNAL ;
    PORT
      LAYER M5 ;
        RECT  7.92 51.756 7.944 51.84 ;
    END
  END d[5]
  PIN d[60]
    DIRECTION INPUT ;
    USE SIGNAL ;
    PORT
      LAYER M5 ;
        RECT  15.696 51.756 15.72 51.84 ;
    END
  END d[60]
  PIN d[61]
    DIRECTION INPUT ;
    USE SIGNAL ;
    PORT
      LAYER M5 ;
        RECT  15.984 51.756 16.008 51.84 ;
    END
  END d[61]
  PIN d[62]
    DIRECTION INPUT ;
    USE SIGNAL ;
    PORT
      LAYER M5 ;
        RECT  16.416 51.756 16.44 51.84 ;
    END
  END d[62]
  PIN d[63]
    DIRECTION INPUT ;
    USE SIGNAL ;
    PORT
      LAYER M5 ;
        RECT  16.128 51.756 16.152 51.84 ;
    END
  END d[63]
  PIN d[64]
    DIRECTION INPUT ;
    USE SIGNAL ;
    PORT
      LAYER M5 ;
        RECT  16.704 51.756 16.728 51.84 ;
    END
  END d[64]
  PIN d[65]
    DIRECTION INPUT ;
    USE SIGNAL ;
    PORT
      LAYER M5 ;
        RECT  16.272 51.756 16.296 51.84 ;
    END
  END d[65]
  PIN d[66]
    DIRECTION INPUT ;
    USE SIGNAL ;
    PORT
      LAYER M5 ;
        RECT  16.992 51.756 17.016 51.84 ;
    END
  END d[66]
  PIN d[67]
    DIRECTION INPUT ;
    USE SIGNAL ;
    PORT
      LAYER M5 ;
        RECT  16.56 51.756 16.584 51.84 ;
    END
  END d[67]
  PIN d[68]
    DIRECTION INPUT ;
    USE SIGNAL ;
    PORT
      LAYER M5 ;
        RECT  17.136 51.756 17.16 51.84 ;
    END
  END d[68]
  PIN d[69]
    DIRECTION INPUT ;
    USE SIGNAL ;
    PORT
      LAYER M5 ;
        RECT  16.848 51.756 16.872 51.84 ;
    END
  END d[69]
  PIN d[6]
    DIRECTION INPUT ;
    USE SIGNAL ;
    PORT
      LAYER M5 ;
        RECT  8.064 51.756 8.088 51.84 ;
    END
  END d[6]
  PIN d[70]
    DIRECTION INPUT ;
    USE SIGNAL ;
    PORT
      LAYER M5 ;
        RECT  17.424 51.756 17.448 51.84 ;
    END
  END d[70]
  PIN d[71]
    DIRECTION INPUT ;
    USE SIGNAL ;
    PORT
      LAYER M5 ;
        RECT  17.28 51.756 17.304 51.84 ;
    END
  END d[71]
  PIN d[72]
    DIRECTION INPUT ;
    USE SIGNAL ;
    PORT
      LAYER M5 ;
        RECT  17.712 51.756 17.736 51.84 ;
    END
  END d[72]
  PIN d[73]
    DIRECTION INPUT ;
    USE SIGNAL ;
    PORT
      LAYER M5 ;
        RECT  17.568 51.756 17.592 51.84 ;
    END
  END d[73]
  PIN d[74]
    DIRECTION INPUT ;
    USE SIGNAL ;
    PORT
      LAYER M5 ;
        RECT  18 51.756 18.024 51.84 ;
    END
  END d[74]
  PIN d[75]
    DIRECTION INPUT ;
    USE SIGNAL ;
    PORT
      LAYER M5 ;
        RECT  17.856 51.756 17.88 51.84 ;
    END
  END d[75]
  PIN d[76]
    DIRECTION INPUT ;
    USE SIGNAL ;
    PORT
      LAYER M5 ;
        RECT  18.288 51.756 18.312 51.84 ;
    END
  END d[76]
  PIN d[77]
    DIRECTION INPUT ;
    USE SIGNAL ;
    PORT
      LAYER M5 ;
        RECT  18.144 51.756 18.168 51.84 ;
    END
  END d[77]
  PIN d[78]
    DIRECTION INPUT ;
    USE SIGNAL ;
    PORT
      LAYER M5 ;
        RECT  18.576 51.756 18.6 51.84 ;
    END
  END d[78]
  PIN d[79]
    DIRECTION INPUT ;
    USE SIGNAL ;
    PORT
      LAYER M5 ;
        RECT  18.432 51.756 18.456 51.84 ;
    END
  END d[79]
  PIN d[7]
    DIRECTION INPUT ;
    USE SIGNAL ;
    PORT
      LAYER M5 ;
        RECT  8.208 51.756 8.232 51.84 ;
    END
  END d[7]
  PIN d[80]
    DIRECTION INPUT ;
    USE SIGNAL ;
    PORT
      LAYER M5 ;
        RECT  18.864 51.756 18.888 51.84 ;
    END
  END d[80]
  PIN d[81]
    DIRECTION INPUT ;
    USE SIGNAL ;
    PORT
      LAYER M5 ;
        RECT  18.72 51.756 18.744 51.84 ;
    END
  END d[81]
  PIN d[82]
    DIRECTION INPUT ;
    USE SIGNAL ;
    PORT
      LAYER M5 ;
        RECT  19.152 51.756 19.176 51.84 ;
    END
  END d[82]
  PIN d[83]
    DIRECTION INPUT ;
    USE SIGNAL ;
    PORT
      LAYER M5 ;
        RECT  19.008 51.756 19.032 51.84 ;
    END
  END d[83]
  PIN d[84]
    DIRECTION INPUT ;
    USE SIGNAL ;
    PORT
      LAYER M5 ;
        RECT  19.44 51.756 19.464 51.84 ;
    END
  END d[84]
  PIN d[85]
    DIRECTION INPUT ;
    USE SIGNAL ;
    PORT
      LAYER M5 ;
        RECT  19.296 51.756 19.32 51.84 ;
    END
  END d[85]
  PIN d[86]
    DIRECTION INPUT ;
    USE SIGNAL ;
    PORT
      LAYER M5 ;
        RECT  19.728 51.756 19.752 51.84 ;
    END
  END d[86]
  PIN d[87]
    DIRECTION INPUT ;
    USE SIGNAL ;
    PORT
      LAYER M5 ;
        RECT  19.584 51.756 19.608 51.84 ;
    END
  END d[87]
  PIN d[88]
    DIRECTION INPUT ;
    USE SIGNAL ;
    PORT
      LAYER M5 ;
        RECT  19.872 51.756 19.896 51.84 ;
    END
  END d[88]
  PIN d[89]
    DIRECTION INPUT ;
    USE SIGNAL ;
    PORT
      LAYER M5 ;
        RECT  20.016 51.756 20.04 51.84 ;
    END
  END d[89]
  PIN d[8]
    DIRECTION INPUT ;
    USE SIGNAL ;
    PORT
      LAYER M5 ;
        RECT  8.352 51.756 8.376 51.84 ;
    END
  END d[8]
  PIN d[90]
    DIRECTION INPUT ;
    USE SIGNAL ;
    PORT
      LAYER M5 ;
        RECT  20.16 51.756 20.184 51.84 ;
    END
  END d[90]
  PIN d[91]
    DIRECTION INPUT ;
    USE SIGNAL ;
    PORT
      LAYER M5 ;
        RECT  20.304 51.756 20.328 51.84 ;
    END
  END d[91]
  PIN d[92]
    DIRECTION INPUT ;
    USE SIGNAL ;
    PORT
      LAYER M5 ;
        RECT  20.448 51.756 20.472 51.84 ;
    END
  END d[92]
  PIN d[93]
    DIRECTION INPUT ;
    USE SIGNAL ;
    PORT
      LAYER M5 ;
        RECT  20.592 51.756 20.616 51.84 ;
    END
  END d[93]
  PIN d[94]
    DIRECTION INPUT ;
    USE SIGNAL ;
    PORT
      LAYER M5 ;
        RECT  20.736 51.756 20.76 51.84 ;
    END
  END d[94]
  PIN d[95]
    DIRECTION INPUT ;
    USE SIGNAL ;
    PORT
      LAYER M5 ;
        RECT  20.88 51.756 20.904 51.84 ;
    END
  END d[95]
  PIN d[96]
    DIRECTION INPUT ;
    USE SIGNAL ;
    PORT
      LAYER M5 ;
        RECT  21.024 51.756 21.048 51.84 ;
    END
  END d[96]
  PIN d[97]
    DIRECTION INPUT ;
    USE SIGNAL ;
    PORT
      LAYER M5 ;
        RECT  21.168 51.756 21.192 51.84 ;
    END
  END d[97]
  PIN d[98]
    DIRECTION INPUT ;
    USE SIGNAL ;
    PORT
      LAYER M5 ;
        RECT  21.312 51.756 21.336 51.84 ;
    END
  END d[98]
  PIN d[99]
    DIRECTION INPUT ;
    USE SIGNAL ;
    PORT
      LAYER M5 ;
        RECT  21.456 51.756 21.48 51.84 ;
    END
  END d[99]
  PIN d[9]
    DIRECTION INPUT ;
    USE SIGNAL ;
    PORT
      LAYER M5 ;
        RECT  8.64 51.756 8.664 51.84 ;
    END
  END d[9]
  PIN fault
    DIRECTION OUTPUT ;
    USE SIGNAL ;
    PORT
      LAYER M5 ;
        RECT  44.208 0 44.232 0.084 ;
    END
  END fault
  PIN fclk
    DIRECTION INPUT ;
    USE SIGNAL ;
    PORT
      LAYER M5 ;
        RECT  44.352 51.756 44.376 51.84 ;
    END
  END fclk
  PIN q[0]
    DIRECTION OUTPUT ;
    USE SIGNAL ;
    PORT
      LAYER M5 ;
        RECT  6.624 0 6.648 0.084 ;
    END
  END q[0]
  PIN q[100]
    DIRECTION OUTPUT ;
    USE SIGNAL ;
    PORT
      LAYER M5 ;
        RECT  21.024 0 21.048 0.084 ;
    END
  END q[100]
  PIN q[101]
    DIRECTION OUTPUT ;
    USE SIGNAL ;
    PORT
      LAYER M5 ;
        RECT  21.312 0 21.336 0.084 ;
    END
  END q[101]
  PIN q[102]
    DIRECTION OUTPUT ;
    USE SIGNAL ;
    PORT
      LAYER M5 ;
        RECT  21.168 0 21.192 0.084 ;
    END
  END q[102]
  PIN q[103]
    DIRECTION OUTPUT ;
    USE SIGNAL ;
    PORT
      LAYER M5 ;
        RECT  21.6 0 21.624 0.084 ;
    END
  END q[103]
  PIN q[104]
    DIRECTION OUTPUT ;
    USE SIGNAL ;
    PORT
      LAYER M5 ;
        RECT  21.456 0 21.48 0.084 ;
    END
  END q[104]
  PIN q[105]
    DIRECTION OUTPUT ;
    USE SIGNAL ;
    PORT
      LAYER M5 ;
        RECT  21.888 0 21.912 0.084 ;
    END
  END q[105]
  PIN q[106]
    DIRECTION OUTPUT ;
    USE SIGNAL ;
    PORT
      LAYER M5 ;
        RECT  21.744 0 21.768 0.084 ;
    END
  END q[106]
  PIN q[107]
    DIRECTION OUTPUT ;
    USE SIGNAL ;
    PORT
      LAYER M5 ;
        RECT  22.176 0 22.2 0.084 ;
    END
  END q[107]
  PIN q[108]
    DIRECTION OUTPUT ;
    USE SIGNAL ;
    PORT
      LAYER M5 ;
        RECT  22.032 0 22.056 0.084 ;
    END
  END q[108]
  PIN q[109]
    DIRECTION OUTPUT ;
    USE SIGNAL ;
    PORT
      LAYER M5 ;
        RECT  22.464 0 22.488 0.084 ;
    END
  END q[109]
  PIN q[10]
    DIRECTION OUTPUT ;
    USE SIGNAL ;
    PORT
      LAYER M5 ;
        RECT  7.92 0 7.944 0.084 ;
    END
  END q[10]
  PIN q[110]
    DIRECTION OUTPUT ;
    USE SIGNAL ;
    PORT
      LAYER M5 ;
        RECT  22.32 0 22.344 0.084 ;
    END
  END q[110]
  PIN q[111]
    DIRECTION OUTPUT ;
    USE SIGNAL ;
    PORT
      LAYER M5 ;
        RECT  22.608 0 22.632 0.084 ;
    END
  END q[111]
  PIN q[112]
    DIRECTION OUTPUT ;
    USE SIGNAL ;
    PORT
      LAYER M5 ;
        RECT  23.04 0 23.064 0.084 ;
    END
  END q[112]
  PIN q[113]
    DIRECTION OUTPUT ;
    USE SIGNAL ;
    PORT
      LAYER M5 ;
        RECT  22.752 0 22.776 0.084 ;
    END
  END q[113]
  PIN q[114]
    DIRECTION OUTPUT ;
    USE SIGNAL ;
    PORT
      LAYER M5 ;
        RECT  23.328 0 23.352 0.084 ;
    END
  END q[114]
  PIN q[115]
    DIRECTION OUTPUT ;
    USE SIGNAL ;
    PORT
      LAYER M5 ;
        RECT  22.896 0 22.92 0.084 ;
    END
  END q[115]
  PIN q[116]
    DIRECTION OUTPUT ;
    USE SIGNAL ;
    PORT
      LAYER M5 ;
        RECT  23.472 0 23.496 0.084 ;
    END
  END q[116]
  PIN q[117]
    DIRECTION OUTPUT ;
    USE SIGNAL ;
    PORT
      LAYER M5 ;
        RECT  23.184 0 23.208 0.084 ;
    END
  END q[117]
  PIN q[118]
    DIRECTION OUTPUT ;
    USE SIGNAL ;
    PORT
      LAYER M5 ;
        RECT  23.76 0 23.784 0.084 ;
    END
  END q[118]
  PIN q[119]
    DIRECTION OUTPUT ;
    USE SIGNAL ;
    PORT
      LAYER M5 ;
        RECT  23.616 0 23.64 0.084 ;
    END
  END q[119]
  PIN q[11]
    DIRECTION OUTPUT ;
    USE SIGNAL ;
    PORT
      LAYER M5 ;
        RECT  8.208 0 8.232 0.084 ;
    END
  END q[11]
  PIN q[120]
    DIRECTION OUTPUT ;
    USE SIGNAL ;
    PORT
      LAYER M5 ;
        RECT  24.048 0 24.072 0.084 ;
    END
  END q[120]
  PIN q[121]
    DIRECTION OUTPUT ;
    USE SIGNAL ;
    PORT
      LAYER M5 ;
        RECT  23.904 0 23.928 0.084 ;
    END
  END q[121]
  PIN q[122]
    DIRECTION OUTPUT ;
    USE SIGNAL ;
    PORT
      LAYER M5 ;
        RECT  24.336 0 24.36 0.084 ;
    END
  END q[122]
  PIN q[123]
    DIRECTION OUTPUT ;
    USE SIGNAL ;
    PORT
      LAYER M5 ;
        RECT  24.192 0 24.216 0.084 ;
    END
  END q[123]
  PIN q[124]
    DIRECTION OUTPUT ;
    USE SIGNAL ;
    PORT
      LAYER M5 ;
        RECT  24.624 0 24.648 0.084 ;
    END
  END q[124]
  PIN q[125]
    DIRECTION OUTPUT ;
    USE SIGNAL ;
    PORT
      LAYER M5 ;
        RECT  24.48 0 24.504 0.084 ;
    END
  END q[125]
  PIN q[126]
    DIRECTION OUTPUT ;
    USE SIGNAL ;
    PORT
      LAYER M5 ;
        RECT  24.912 0 24.936 0.084 ;
    END
  END q[126]
  PIN q[127]
    DIRECTION OUTPUT ;
    USE SIGNAL ;
    PORT
      LAYER M5 ;
        RECT  24.768 0 24.792 0.084 ;
    END
  END q[127]
  PIN q[128]
    DIRECTION OUTPUT ;
    USE SIGNAL ;
    PORT
      LAYER M5 ;
        RECT  25.2 0 25.224 0.084 ;
    END
  END q[128]
  PIN q[129]
    DIRECTION OUTPUT ;
    USE SIGNAL ;
    PORT
      LAYER M5 ;
        RECT  25.056 0 25.08 0.084 ;
    END
  END q[129]
  PIN q[12]
    DIRECTION OUTPUT ;
    USE SIGNAL ;
    PORT
      LAYER M5 ;
        RECT  8.64 0 8.664 0.084 ;
    END
  END q[12]
  PIN q[130]
    DIRECTION OUTPUT ;
    USE SIGNAL ;
    PORT
      LAYER M5 ;
        RECT  25.344 0 25.368 0.084 ;
    END
  END q[130]
  PIN q[131]
    DIRECTION OUTPUT ;
    USE SIGNAL ;
    PORT
      LAYER M5 ;
        RECT  25.488 0 25.512 0.084 ;
    END
  END q[131]
  PIN q[132]
    DIRECTION OUTPUT ;
    USE SIGNAL ;
    PORT
      LAYER M5 ;
        RECT  25.632 0 25.656 0.084 ;
    END
  END q[132]
  PIN q[133]
    DIRECTION OUTPUT ;
    USE SIGNAL ;
    PORT
      LAYER M5 ;
        RECT  25.776 0 25.8 0.084 ;
    END
  END q[133]
  PIN q[134]
    DIRECTION OUTPUT ;
    USE SIGNAL ;
    PORT
      LAYER M5 ;
        RECT  25.92 0 25.944 0.084 ;
    END
  END q[134]
  PIN q[135]
    DIRECTION OUTPUT ;
    USE SIGNAL ;
    PORT
      LAYER M5 ;
        RECT  26.064 0 26.088 0.084 ;
    END
  END q[135]
  PIN q[136]
    DIRECTION OUTPUT ;
    USE SIGNAL ;
    PORT
      LAYER M5 ;
        RECT  26.208 0 26.232 0.084 ;
    END
  END q[136]
  PIN q[137]
    DIRECTION OUTPUT ;
    USE SIGNAL ;
    PORT
      LAYER M5 ;
        RECT  26.352 0 26.376 0.084 ;
    END
  END q[137]
  PIN q[138]
    DIRECTION OUTPUT ;
    USE SIGNAL ;
    PORT
      LAYER M5 ;
        RECT  26.496 0 26.52 0.084 ;
    END
  END q[138]
  PIN q[139]
    DIRECTION OUTPUT ;
    USE SIGNAL ;
    PORT
      LAYER M5 ;
        RECT  26.64 0 26.664 0.084 ;
    END
  END q[139]
  PIN q[13]
    DIRECTION OUTPUT ;
    USE SIGNAL ;
    PORT
      LAYER M5 ;
        RECT  8.352 0 8.376 0.084 ;
    END
  END q[13]
  PIN q[140]
    DIRECTION OUTPUT ;
    USE SIGNAL ;
    PORT
      LAYER M5 ;
        RECT  26.784 0 26.808 0.084 ;
    END
  END q[140]
  PIN q[141]
    DIRECTION OUTPUT ;
    USE SIGNAL ;
    PORT
      LAYER M5 ;
        RECT  26.928 0 26.952 0.084 ;
    END
  END q[141]
  PIN q[142]
    DIRECTION OUTPUT ;
    USE SIGNAL ;
    PORT
      LAYER M5 ;
        RECT  27.072 0 27.096 0.084 ;
    END
  END q[142]
  PIN q[143]
    DIRECTION OUTPUT ;
    USE SIGNAL ;
    PORT
      LAYER M5 ;
        RECT  27.216 0 27.24 0.084 ;
    END
  END q[143]
  PIN q[144]
    DIRECTION OUTPUT ;
    USE SIGNAL ;
    PORT
      LAYER M5 ;
        RECT  27.36 0 27.384 0.084 ;
    END
  END q[144]
  PIN q[145]
    DIRECTION OUTPUT ;
    USE SIGNAL ;
    PORT
      LAYER M5 ;
        RECT  27.504 0 27.528 0.084 ;
    END
  END q[145]
  PIN q[146]
    DIRECTION OUTPUT ;
    USE SIGNAL ;
    PORT
      LAYER M5 ;
        RECT  27.648 0 27.672 0.084 ;
    END
  END q[146]
  PIN q[147]
    DIRECTION OUTPUT ;
    USE SIGNAL ;
    PORT
      LAYER M5 ;
        RECT  27.936 0 27.96 0.084 ;
    END
  END q[147]
  PIN q[148]
    DIRECTION OUTPUT ;
    USE SIGNAL ;
    PORT
      LAYER M5 ;
        RECT  27.792 0 27.816 0.084 ;
    END
  END q[148]
  PIN q[149]
    DIRECTION OUTPUT ;
    USE SIGNAL ;
    PORT
      LAYER M5 ;
        RECT  28.08 0 28.104 0.084 ;
    END
  END q[149]
  PIN q[14]
    DIRECTION OUTPUT ;
    USE SIGNAL ;
    PORT
      LAYER M5 ;
        RECT  8.928 0 8.952 0.084 ;
    END
  END q[14]
  PIN q[150]
    DIRECTION OUTPUT ;
    USE SIGNAL ;
    PORT
      LAYER M5 ;
        RECT  28.224 0 28.248 0.084 ;
    END
  END q[150]
  PIN q[151]
    DIRECTION OUTPUT ;
    USE SIGNAL ;
    PORT
      LAYER M5 ;
        RECT  28.512 0 28.536 0.084 ;
    END
  END q[151]
  PIN q[152]
    DIRECTION OUTPUT ;
    USE SIGNAL ;
    PORT
      LAYER M5 ;
        RECT  28.368 0 28.392 0.084 ;
    END
  END q[152]
  PIN q[153]
    DIRECTION OUTPUT ;
    USE SIGNAL ;
    PORT
      LAYER M5 ;
        RECT  28.8 0 28.824 0.084 ;
    END
  END q[153]
  PIN q[154]
    DIRECTION OUTPUT ;
    USE SIGNAL ;
    PORT
      LAYER M5 ;
        RECT  28.656 0 28.68 0.084 ;
    END
  END q[154]
  PIN q[155]
    DIRECTION OUTPUT ;
    USE SIGNAL ;
    PORT
      LAYER M5 ;
        RECT  29.088 0 29.112 0.084 ;
    END
  END q[155]
  PIN q[156]
    DIRECTION OUTPUT ;
    USE SIGNAL ;
    PORT
      LAYER M5 ;
        RECT  28.944 0 28.968 0.084 ;
    END
  END q[156]
  PIN q[157]
    DIRECTION OUTPUT ;
    USE SIGNAL ;
    PORT
      LAYER M5 ;
        RECT  29.376 0 29.4 0.084 ;
    END
  END q[157]
  PIN q[158]
    DIRECTION OUTPUT ;
    USE SIGNAL ;
    PORT
      LAYER M5 ;
        RECT  29.232 0 29.256 0.084 ;
    END
  END q[158]
  PIN q[159]
    DIRECTION OUTPUT ;
    USE SIGNAL ;
    PORT
      LAYER M5 ;
        RECT  29.664 0 29.688 0.084 ;
    END
  END q[159]
  PIN q[15]
    DIRECTION OUTPUT ;
    USE SIGNAL ;
    PORT
      LAYER M5 ;
        RECT  8.496 0 8.52 0.084 ;
    END
  END q[15]
  PIN q[160]
    DIRECTION OUTPUT ;
    USE SIGNAL ;
    PORT
      LAYER M5 ;
        RECT  29.52 0 29.544 0.084 ;
    END
  END q[160]
  PIN q[161]
    DIRECTION OUTPUT ;
    USE SIGNAL ;
    PORT
      LAYER M5 ;
        RECT  29.808 0 29.832 0.084 ;
    END
  END q[161]
  PIN q[162]
    DIRECTION OUTPUT ;
    USE SIGNAL ;
    PORT
      LAYER M5 ;
        RECT  30.096 0 30.12 0.084 ;
    END
  END q[162]
  PIN q[163]
    DIRECTION OUTPUT ;
    USE SIGNAL ;
    PORT
      LAYER M5 ;
        RECT  29.952 0 29.976 0.084 ;
    END
  END q[163]
  PIN q[164]
    DIRECTION OUTPUT ;
    USE SIGNAL ;
    PORT
      LAYER M5 ;
        RECT  30.384 0 30.408 0.084 ;
    END
  END q[164]
  PIN q[165]
    DIRECTION OUTPUT ;
    USE SIGNAL ;
    PORT
      LAYER M5 ;
        RECT  30.24 0 30.264 0.084 ;
    END
  END q[165]
  PIN q[166]
    DIRECTION OUTPUT ;
    USE SIGNAL ;
    PORT
      LAYER M5 ;
        RECT  30.672 0 30.696 0.084 ;
    END
  END q[166]
  PIN q[167]
    DIRECTION OUTPUT ;
    USE SIGNAL ;
    PORT
      LAYER M5 ;
        RECT  30.528 0 30.552 0.084 ;
    END
  END q[167]
  PIN q[168]
    DIRECTION OUTPUT ;
    USE SIGNAL ;
    PORT
      LAYER M5 ;
        RECT  30.96 0 30.984 0.084 ;
    END
  END q[168]
  PIN q[169]
    DIRECTION OUTPUT ;
    USE SIGNAL ;
    PORT
      LAYER M5 ;
        RECT  30.816 0 30.84 0.084 ;
    END
  END q[169]
  PIN q[16]
    DIRECTION OUTPUT ;
    USE SIGNAL ;
    PORT
      LAYER M5 ;
        RECT  9.216 0 9.24 0.084 ;
    END
  END q[16]
  PIN q[170]
    DIRECTION OUTPUT ;
    USE SIGNAL ;
    PORT
      LAYER M5 ;
        RECT  31.248 0 31.272 0.084 ;
    END
  END q[170]
  PIN q[171]
    DIRECTION OUTPUT ;
    USE SIGNAL ;
    PORT
      LAYER M5 ;
        RECT  31.104 0 31.128 0.084 ;
    END
  END q[171]
  PIN q[172]
    DIRECTION OUTPUT ;
    USE SIGNAL ;
    PORT
      LAYER M5 ;
        RECT  31.536 0 31.56 0.084 ;
    END
  END q[172]
  PIN q[173]
    DIRECTION OUTPUT ;
    USE SIGNAL ;
    PORT
      LAYER M5 ;
        RECT  31.392 0 31.416 0.084 ;
    END
  END q[173]
  PIN q[174]
    DIRECTION OUTPUT ;
    USE SIGNAL ;
    PORT
      LAYER M5 ;
        RECT  31.68 0 31.704 0.084 ;
    END
  END q[174]
  PIN q[175]
    DIRECTION OUTPUT ;
    USE SIGNAL ;
    PORT
      LAYER M5 ;
        RECT  31.824 0 31.848 0.084 ;
    END
  END q[175]
  PIN q[176]
    DIRECTION OUTPUT ;
    USE SIGNAL ;
    PORT
      LAYER M5 ;
        RECT  32.112 0 32.136 0.084 ;
    END
  END q[176]
  PIN q[177]
    DIRECTION OUTPUT ;
    USE SIGNAL ;
    PORT
      LAYER M5 ;
        RECT  31.968 0 31.992 0.084 ;
    END
  END q[177]
  PIN q[178]
    DIRECTION OUTPUT ;
    USE SIGNAL ;
    PORT
      LAYER M5 ;
        RECT  32.4 0 32.424 0.084 ;
    END
  END q[178]
  PIN q[179]
    DIRECTION OUTPUT ;
    USE SIGNAL ;
    PORT
      LAYER M5 ;
        RECT  32.256 0 32.28 0.084 ;
    END
  END q[179]
  PIN q[17]
    DIRECTION OUTPUT ;
    USE SIGNAL ;
    PORT
      LAYER M5 ;
        RECT  8.784 0 8.808 0.084 ;
    END
  END q[17]
  PIN q[180]
    DIRECTION OUTPUT ;
    USE SIGNAL ;
    PORT
      LAYER M5 ;
        RECT  32.544 0 32.568 0.084 ;
    END
  END q[180]
  PIN q[181]
    DIRECTION OUTPUT ;
    USE SIGNAL ;
    PORT
      LAYER M5 ;
        RECT  32.688 0 32.712 0.084 ;
    END
  END q[181]
  PIN q[182]
    DIRECTION OUTPUT ;
    USE SIGNAL ;
    PORT
      LAYER M5 ;
        RECT  32.832 0 32.856 0.084 ;
    END
  END q[182]
  PIN q[183]
    DIRECTION OUTPUT ;
    USE SIGNAL ;
    PORT
      LAYER M5 ;
        RECT  32.976 0 33 0.084 ;
    END
  END q[183]
  PIN q[184]
    DIRECTION OUTPUT ;
    USE SIGNAL ;
    PORT
      LAYER M5 ;
        RECT  33.12 0 33.144 0.084 ;
    END
  END q[184]
  PIN q[185]
    DIRECTION OUTPUT ;
    USE SIGNAL ;
    PORT
      LAYER M5 ;
        RECT  33.264 0 33.288 0.084 ;
    END
  END q[185]
  PIN q[186]
    DIRECTION OUTPUT ;
    USE SIGNAL ;
    PORT
      LAYER M5 ;
        RECT  33.408 0 33.432 0.084 ;
    END
  END q[186]
  PIN q[187]
    DIRECTION OUTPUT ;
    USE SIGNAL ;
    PORT
      LAYER M5 ;
        RECT  33.552 0 33.576 0.084 ;
    END
  END q[187]
  PIN q[188]
    DIRECTION OUTPUT ;
    USE SIGNAL ;
    PORT
      LAYER M5 ;
        RECT  33.696 0 33.72 0.084 ;
    END
  END q[188]
  PIN q[189]
    DIRECTION OUTPUT ;
    USE SIGNAL ;
    PORT
      LAYER M5 ;
        RECT  33.84 0 33.864 0.084 ;
    END
  END q[189]
  PIN q[18]
    DIRECTION OUTPUT ;
    USE SIGNAL ;
    PORT
      LAYER M5 ;
        RECT  9.504 0 9.528 0.084 ;
    END
  END q[18]
  PIN q[190]
    DIRECTION OUTPUT ;
    USE SIGNAL ;
    PORT
      LAYER M5 ;
        RECT  33.984 0 34.008 0.084 ;
    END
  END q[190]
  PIN q[191]
    DIRECTION OUTPUT ;
    USE SIGNAL ;
    PORT
      LAYER M5 ;
        RECT  34.128 0 34.152 0.084 ;
    END
  END q[191]
  PIN q[192]
    DIRECTION OUTPUT ;
    USE SIGNAL ;
    PORT
      LAYER M5 ;
        RECT  34.272 0 34.296 0.084 ;
    END
  END q[192]
  PIN q[193]
    DIRECTION OUTPUT ;
    USE SIGNAL ;
    PORT
      LAYER M5 ;
        RECT  34.56 0 34.584 0.084 ;
    END
  END q[193]
  PIN q[194]
    DIRECTION OUTPUT ;
    USE SIGNAL ;
    PORT
      LAYER M5 ;
        RECT  34.416 0 34.44 0.084 ;
    END
  END q[194]
  PIN q[195]
    DIRECTION OUTPUT ;
    USE SIGNAL ;
    PORT
      LAYER M5 ;
        RECT  34.848 0 34.872 0.084 ;
    END
  END q[195]
  PIN q[196]
    DIRECTION OUTPUT ;
    USE SIGNAL ;
    PORT
      LAYER M5 ;
        RECT  34.704 0 34.728 0.084 ;
    END
  END q[196]
  PIN q[197]
    DIRECTION OUTPUT ;
    USE SIGNAL ;
    PORT
      LAYER M5 ;
        RECT  35.136 0 35.16 0.084 ;
    END
  END q[197]
  PIN q[198]
    DIRECTION OUTPUT ;
    USE SIGNAL ;
    PORT
      LAYER M5 ;
        RECT  34.992 0 35.016 0.084 ;
    END
  END q[198]
  PIN q[199]
    DIRECTION OUTPUT ;
    USE SIGNAL ;
    PORT
      LAYER M5 ;
        RECT  35.28 0 35.304 0.084 ;
    END
  END q[199]
  PIN q[19]
    DIRECTION OUTPUT ;
    USE SIGNAL ;
    PORT
      LAYER M5 ;
        RECT  9.072 0 9.096 0.084 ;
    END
  END q[19]
  PIN q[1]
    DIRECTION OUTPUT ;
    USE SIGNAL ;
    PORT
      LAYER M5 ;
        RECT  6.768 0 6.792 0.084 ;
    END
  END q[1]
  PIN q[200]
    DIRECTION OUTPUT ;
    USE SIGNAL ;
    PORT
      LAYER M5 ;
        RECT  35.424 0 35.448 0.084 ;
    END
  END q[200]
  PIN q[201]
    DIRECTION OUTPUT ;
    USE SIGNAL ;
    PORT
      LAYER M5 ;
        RECT  35.712 0 35.736 0.084 ;
    END
  END q[201]
  PIN q[202]
    DIRECTION OUTPUT ;
    USE SIGNAL ;
    PORT
      LAYER M5 ;
        RECT  35.568 0 35.592 0.084 ;
    END
  END q[202]
  PIN q[203]
    DIRECTION OUTPUT ;
    USE SIGNAL ;
    PORT
      LAYER M5 ;
        RECT  36 0 36.024 0.084 ;
    END
  END q[203]
  PIN q[204]
    DIRECTION OUTPUT ;
    USE SIGNAL ;
    PORT
      LAYER M5 ;
        RECT  35.856 0 35.88 0.084 ;
    END
  END q[204]
  PIN q[205]
    DIRECTION OUTPUT ;
    USE SIGNAL ;
    PORT
      LAYER M5 ;
        RECT  36.288 0 36.312 0.084 ;
    END
  END q[205]
  PIN q[206]
    DIRECTION OUTPUT ;
    USE SIGNAL ;
    PORT
      LAYER M5 ;
        RECT  36.144 0 36.168 0.084 ;
    END
  END q[206]
  PIN q[207]
    DIRECTION OUTPUT ;
    USE SIGNAL ;
    PORT
      LAYER M5 ;
        RECT  36.576 0 36.6 0.084 ;
    END
  END q[207]
  PIN q[208]
    DIRECTION OUTPUT ;
    USE SIGNAL ;
    PORT
      LAYER M5 ;
        RECT  36.432 0 36.456 0.084 ;
    END
  END q[208]
  PIN q[209]
    DIRECTION OUTPUT ;
    USE SIGNAL ;
    PORT
      LAYER M5 ;
        RECT  36.864 0 36.888 0.084 ;
    END
  END q[209]
  PIN q[20]
    DIRECTION OUTPUT ;
    USE SIGNAL ;
    PORT
      LAYER M5 ;
        RECT  9.792 0 9.816 0.084 ;
    END
  END q[20]
  PIN q[210]
    DIRECTION OUTPUT ;
    USE SIGNAL ;
    PORT
      LAYER M5 ;
        RECT  36.72 0 36.744 0.084 ;
    END
  END q[210]
  PIN q[211]
    DIRECTION OUTPUT ;
    USE SIGNAL ;
    PORT
      LAYER M5 ;
        RECT  37.008 0 37.032 0.084 ;
    END
  END q[211]
  PIN q[212]
    DIRECTION OUTPUT ;
    USE SIGNAL ;
    PORT
      LAYER M5 ;
        RECT  37.296 0 37.32 0.084 ;
    END
  END q[212]
  PIN q[213]
    DIRECTION OUTPUT ;
    USE SIGNAL ;
    PORT
      LAYER M5 ;
        RECT  37.152 0 37.176 0.084 ;
    END
  END q[213]
  PIN q[214]
    DIRECTION OUTPUT ;
    USE SIGNAL ;
    PORT
      LAYER M5 ;
        RECT  37.584 0 37.608 0.084 ;
    END
  END q[214]
  PIN q[215]
    DIRECTION OUTPUT ;
    USE SIGNAL ;
    PORT
      LAYER M5 ;
        RECT  37.44 0 37.464 0.084 ;
    END
  END q[215]
  PIN q[216]
    DIRECTION OUTPUT ;
    USE SIGNAL ;
    PORT
      LAYER M5 ;
        RECT  37.872 0 37.896 0.084 ;
    END
  END q[216]
  PIN q[217]
    DIRECTION OUTPUT ;
    USE SIGNAL ;
    PORT
      LAYER M5 ;
        RECT  37.728 0 37.752 0.084 ;
    END
  END q[217]
  PIN q[218]
    DIRECTION OUTPUT ;
    USE SIGNAL ;
    PORT
      LAYER M5 ;
        RECT  38.16 0 38.184 0.084 ;
    END
  END q[218]
  PIN q[219]
    DIRECTION OUTPUT ;
    USE SIGNAL ;
    PORT
      LAYER M5 ;
        RECT  38.016 0 38.04 0.084 ;
    END
  END q[219]
  PIN q[21]
    DIRECTION OUTPUT ;
    USE SIGNAL ;
    PORT
      LAYER M5 ;
        RECT  9.36 0 9.384 0.084 ;
    END
  END q[21]
  PIN q[220]
    DIRECTION OUTPUT ;
    USE SIGNAL ;
    PORT
      LAYER M5 ;
        RECT  38.448 0 38.472 0.084 ;
    END
  END q[220]
  PIN q[221]
    DIRECTION OUTPUT ;
    USE SIGNAL ;
    PORT
      LAYER M5 ;
        RECT  38.304 0 38.328 0.084 ;
    END
  END q[221]
  PIN q[222]
    DIRECTION OUTPUT ;
    USE SIGNAL ;
    PORT
      LAYER M5 ;
        RECT  38.736 0 38.76 0.084 ;
    END
  END q[222]
  PIN q[223]
    DIRECTION OUTPUT ;
    USE SIGNAL ;
    PORT
      LAYER M5 ;
        RECT  38.592 0 38.616 0.084 ;
    END
  END q[223]
  PIN q[224]
    DIRECTION OUTPUT ;
    USE SIGNAL ;
    PORT
      LAYER M5 ;
        RECT  38.88 0 38.904 0.084 ;
    END
  END q[224]
  PIN q[225]
    DIRECTION OUTPUT ;
    USE SIGNAL ;
    PORT
      LAYER M5 ;
        RECT  39.024 0 39.048 0.084 ;
    END
  END q[225]
  PIN q[226]
    DIRECTION OUTPUT ;
    USE SIGNAL ;
    PORT
      LAYER M5 ;
        RECT  39.168 0 39.192 0.084 ;
    END
  END q[226]
  PIN q[227]
    DIRECTION OUTPUT ;
    USE SIGNAL ;
    PORT
      LAYER M5 ;
        RECT  39.312 0 39.336 0.084 ;
    END
  END q[227]
  PIN q[228]
    DIRECTION OUTPUT ;
    USE SIGNAL ;
    PORT
      LAYER M5 ;
        RECT  39.456 0 39.48 0.084 ;
    END
  END q[228]
  PIN q[229]
    DIRECTION OUTPUT ;
    USE SIGNAL ;
    PORT
      LAYER M5 ;
        RECT  39.6 0 39.624 0.084 ;
    END
  END q[229]
  PIN q[22]
    DIRECTION OUTPUT ;
    USE SIGNAL ;
    PORT
      LAYER M5 ;
        RECT  9.936 0 9.96 0.084 ;
    END
  END q[22]
  PIN q[230]
    DIRECTION OUTPUT ;
    USE SIGNAL ;
    PORT
      LAYER M5 ;
        RECT  39.744 0 39.768 0.084 ;
    END
  END q[230]
  PIN q[231]
    DIRECTION OUTPUT ;
    USE SIGNAL ;
    PORT
      LAYER M5 ;
        RECT  39.888 0 39.912 0.084 ;
    END
  END q[231]
  PIN q[232]
    DIRECTION OUTPUT ;
    USE SIGNAL ;
    PORT
      LAYER M5 ;
        RECT  40.032 0 40.056 0.084 ;
    END
  END q[232]
  PIN q[233]
    DIRECTION OUTPUT ;
    USE SIGNAL ;
    PORT
      LAYER M5 ;
        RECT  40.176 0 40.2 0.084 ;
    END
  END q[233]
  PIN q[234]
    DIRECTION OUTPUT ;
    USE SIGNAL ;
    PORT
      LAYER M5 ;
        RECT  40.32 0 40.344 0.084 ;
    END
  END q[234]
  PIN q[235]
    DIRECTION OUTPUT ;
    USE SIGNAL ;
    PORT
      LAYER M5 ;
        RECT  40.464 0 40.488 0.084 ;
    END
  END q[235]
  PIN q[236]
    DIRECTION OUTPUT ;
    USE SIGNAL ;
    PORT
      LAYER M5 ;
        RECT  40.608 0 40.632 0.084 ;
    END
  END q[236]
  PIN q[237]
    DIRECTION OUTPUT ;
    USE SIGNAL ;
    PORT
      LAYER M5 ;
        RECT  40.752 0 40.776 0.084 ;
    END
  END q[237]
  PIN q[238]
    DIRECTION OUTPUT ;
    USE SIGNAL ;
    PORT
      LAYER M5 ;
        RECT  40.896 0 40.92 0.084 ;
    END
  END q[238]
  PIN q[239]
    DIRECTION OUTPUT ;
    USE SIGNAL ;
    PORT
      LAYER M5 ;
        RECT  41.04 0 41.064 0.084 ;
    END
  END q[239]
  PIN q[23]
    DIRECTION OUTPUT ;
    USE SIGNAL ;
    PORT
      LAYER M5 ;
        RECT  9.648 0 9.672 0.084 ;
    END
  END q[23]
  PIN q[240]
    DIRECTION OUTPUT ;
    USE SIGNAL ;
    PORT
      LAYER M5 ;
        RECT  41.184 0 41.208 0.084 ;
    END
  END q[240]
  PIN q[241]
    DIRECTION OUTPUT ;
    USE SIGNAL ;
    PORT
      LAYER M5 ;
        RECT  41.472 0 41.496 0.084 ;
    END
  END q[241]
  PIN q[242]
    DIRECTION OUTPUT ;
    USE SIGNAL ;
    PORT
      LAYER M5 ;
        RECT  41.328 0 41.352 0.084 ;
    END
  END q[242]
  PIN q[243]
    DIRECTION OUTPUT ;
    USE SIGNAL ;
    PORT
      LAYER M5 ;
        RECT  41.76 0 41.784 0.084 ;
    END
  END q[243]
  PIN q[244]
    DIRECTION OUTPUT ;
    USE SIGNAL ;
    PORT
      LAYER M5 ;
        RECT  41.616 0 41.64 0.084 ;
    END
  END q[244]
  PIN q[245]
    DIRECTION OUTPUT ;
    USE SIGNAL ;
    PORT
      LAYER M5 ;
        RECT  42.048 0 42.072 0.084 ;
    END
  END q[245]
  PIN q[246]
    DIRECTION OUTPUT ;
    USE SIGNAL ;
    PORT
      LAYER M5 ;
        RECT  41.904 0 41.928 0.084 ;
    END
  END q[246]
  PIN q[247]
    DIRECTION OUTPUT ;
    USE SIGNAL ;
    PORT
      LAYER M5 ;
        RECT  42.336 0 42.36 0.084 ;
    END
  END q[247]
  PIN q[248]
    DIRECTION OUTPUT ;
    USE SIGNAL ;
    PORT
      LAYER M5 ;
        RECT  42.192 0 42.216 0.084 ;
    END
  END q[248]
  PIN q[249]
    DIRECTION OUTPUT ;
    USE SIGNAL ;
    PORT
      LAYER M5 ;
        RECT  42.768 0 42.792 0.084 ;
    END
  END q[249]
  PIN q[24]
    DIRECTION OUTPUT ;
    USE SIGNAL ;
    PORT
      LAYER M5 ;
        RECT  10.224 0 10.248 0.084 ;
    END
  END q[24]
  PIN q[250]
    DIRECTION OUTPUT ;
    USE SIGNAL ;
    PORT
      LAYER M5 ;
        RECT  42.48 0 42.504 0.084 ;
    END
  END q[250]
  PIN q[251]
    DIRECTION OUTPUT ;
    USE SIGNAL ;
    PORT
      LAYER M5 ;
        RECT  42.912 0 42.936 0.084 ;
    END
  END q[251]
  PIN q[252]
    DIRECTION OUTPUT ;
    USE SIGNAL ;
    PORT
      LAYER M5 ;
        RECT  42.624 0 42.648 0.084 ;
    END
  END q[252]
  PIN q[253]
    DIRECTION OUTPUT ;
    USE SIGNAL ;
    PORT
      LAYER M5 ;
        RECT  43.2 0 43.224 0.084 ;
    END
  END q[253]
  PIN q[254]
    DIRECTION OUTPUT ;
    USE SIGNAL ;
    PORT
      LAYER M5 ;
        RECT  43.056 0 43.08 0.084 ;
    END
  END q[254]
  PIN q[255]
    DIRECTION OUTPUT ;
    USE SIGNAL ;
    PORT
      LAYER M5 ;
        RECT  43.488 0 43.512 0.084 ;
    END
  END q[255]
  PIN q[256]
    DIRECTION OUTPUT ;
    USE SIGNAL ;
    PORT
      LAYER M5 ;
        RECT  43.344 0 43.368 0.084 ;
    END
  END q[256]
  PIN q[257]
    DIRECTION OUTPUT ;
    USE SIGNAL ;
    PORT
      LAYER M5 ;
        RECT  45.216 0 45.24 0.084 ;
    END
  END q[257]
  PIN q[258]
    DIRECTION OUTPUT ;
    USE SIGNAL ;
    PORT
      LAYER M5 ;
        RECT  43.632 0 43.656 0.084 ;
    END
  END q[258]
  PIN q[259]
    DIRECTION OUTPUT ;
    USE SIGNAL ;
    PORT
      LAYER M5 ;
        RECT  45.504 0 45.528 0.084 ;
    END
  END q[259]
  PIN q[25]
    DIRECTION OUTPUT ;
    USE SIGNAL ;
    PORT
      LAYER M5 ;
        RECT  10.08 0 10.104 0.084 ;
    END
  END q[25]
  PIN q[260]
    DIRECTION OUTPUT ;
    USE SIGNAL ;
    PORT
      LAYER M5 ;
        RECT  45.36 0 45.384 0.084 ;
    END
  END q[260]
  PIN q[261]
    DIRECTION OUTPUT ;
    USE SIGNAL ;
    PORT
      LAYER M5 ;
        RECT  45.648 0 45.672 0.084 ;
    END
  END q[261]
  PIN q[262]
    DIRECTION OUTPUT ;
    USE SIGNAL ;
    PORT
      LAYER M5 ;
        RECT  45.936 0 45.96 0.084 ;
    END
  END q[262]
  PIN q[263]
    DIRECTION OUTPUT ;
    USE SIGNAL ;
    PORT
      LAYER M5 ;
        RECT  45.792 0 45.816 0.084 ;
    END
  END q[263]
  PIN q[264]
    DIRECTION OUTPUT ;
    USE SIGNAL ;
    PORT
      LAYER M5 ;
        RECT  46.224 0 46.248 0.084 ;
    END
  END q[264]
  PIN q[265]
    DIRECTION OUTPUT ;
    USE SIGNAL ;
    PORT
      LAYER M5 ;
        RECT  46.08 0 46.104 0.084 ;
    END
  END q[265]
  PIN q[266]
    DIRECTION OUTPUT ;
    USE SIGNAL ;
    PORT
      LAYER M5 ;
        RECT  46.512 0 46.536 0.084 ;
    END
  END q[266]
  PIN q[267]
    DIRECTION OUTPUT ;
    USE SIGNAL ;
    PORT
      LAYER M5 ;
        RECT  46.368 0 46.392 0.084 ;
    END
  END q[267]
  PIN q[268]
    DIRECTION OUTPUT ;
    USE SIGNAL ;
    PORT
      LAYER M5 ;
        RECT  46.8 0 46.824 0.084 ;
    END
  END q[268]
  PIN q[269]
    DIRECTION OUTPUT ;
    USE SIGNAL ;
    PORT
      LAYER M5 ;
        RECT  46.656 0 46.68 0.084 ;
    END
  END q[269]
  PIN q[26]
    DIRECTION OUTPUT ;
    USE SIGNAL ;
    PORT
      LAYER M5 ;
        RECT  10.512 0 10.536 0.084 ;
    END
  END q[26]
  PIN q[270]
    DIRECTION OUTPUT ;
    USE SIGNAL ;
    PORT
      LAYER M5 ;
        RECT  47.088 0 47.112 0.084 ;
    END
  END q[270]
  PIN q[271]
    DIRECTION OUTPUT ;
    USE SIGNAL ;
    PORT
      LAYER M5 ;
        RECT  46.944 0 46.968 0.084 ;
    END
  END q[271]
  PIN q[272]
    DIRECTION OUTPUT ;
    USE SIGNAL ;
    PORT
      LAYER M5 ;
        RECT  47.376 0 47.4 0.084 ;
    END
  END q[272]
  PIN q[273]
    DIRECTION OUTPUT ;
    USE SIGNAL ;
    PORT
      LAYER M5 ;
        RECT  47.232 0 47.256 0.084 ;
    END
  END q[273]
  PIN q[274]
    DIRECTION OUTPUT ;
    USE SIGNAL ;
    PORT
      LAYER M5 ;
        RECT  47.52 0 47.544 0.084 ;
    END
  END q[274]
  PIN q[275]
    DIRECTION OUTPUT ;
    USE SIGNAL ;
    PORT
      LAYER M5 ;
        RECT  47.664 0 47.688 0.084 ;
    END
  END q[275]
  PIN q[276]
    DIRECTION OUTPUT ;
    USE SIGNAL ;
    PORT
      LAYER M5 ;
        RECT  47.808 0 47.832 0.084 ;
    END
  END q[276]
  PIN q[277]
    DIRECTION OUTPUT ;
    USE SIGNAL ;
    PORT
      LAYER M5 ;
        RECT  47.952 0 47.976 0.084 ;
    END
  END q[277]
  PIN q[278]
    DIRECTION OUTPUT ;
    USE SIGNAL ;
    PORT
      LAYER M5 ;
        RECT  48.096 0 48.12 0.084 ;
    END
  END q[278]
  PIN q[279]
    DIRECTION OUTPUT ;
    USE SIGNAL ;
    PORT
      LAYER M5 ;
        RECT  48.24 0 48.264 0.084 ;
    END
  END q[279]
  PIN q[27]
    DIRECTION OUTPUT ;
    USE SIGNAL ;
    PORT
      LAYER M5 ;
        RECT  10.368 0 10.392 0.084 ;
    END
  END q[27]
  PIN q[280]
    DIRECTION OUTPUT ;
    USE SIGNAL ;
    PORT
      LAYER M5 ;
        RECT  48.384 0 48.408 0.084 ;
    END
  END q[280]
  PIN q[281]
    DIRECTION OUTPUT ;
    USE SIGNAL ;
    PORT
      LAYER M5 ;
        RECT  48.528 0 48.552 0.084 ;
    END
  END q[281]
  PIN q[282]
    DIRECTION OUTPUT ;
    USE SIGNAL ;
    PORT
      LAYER M5 ;
        RECT  48.672 0 48.696 0.084 ;
    END
  END q[282]
  PIN q[283]
    DIRECTION OUTPUT ;
    USE SIGNAL ;
    PORT
      LAYER M5 ;
        RECT  48.816 0 48.84 0.084 ;
    END
  END q[283]
  PIN q[284]
    DIRECTION OUTPUT ;
    USE SIGNAL ;
    PORT
      LAYER M5 ;
        RECT  48.96 0 48.984 0.084 ;
    END
  END q[284]
  PIN q[285]
    DIRECTION OUTPUT ;
    USE SIGNAL ;
    PORT
      LAYER M5 ;
        RECT  49.104 0 49.128 0.084 ;
    END
  END q[285]
  PIN q[286]
    DIRECTION OUTPUT ;
    USE SIGNAL ;
    PORT
      LAYER M5 ;
        RECT  49.248 0 49.272 0.084 ;
    END
  END q[286]
  PIN q[287]
    DIRECTION OUTPUT ;
    USE SIGNAL ;
    PORT
      LAYER M5 ;
        RECT  49.392 0 49.416 0.084 ;
    END
  END q[287]
  PIN q[288]
    DIRECTION OUTPUT ;
    USE SIGNAL ;
    PORT
      LAYER M5 ;
        RECT  49.536 0 49.56 0.084 ;
    END
  END q[288]
  PIN q[289]
    DIRECTION OUTPUT ;
    USE SIGNAL ;
    PORT
      LAYER M5 ;
        RECT  49.68 0 49.704 0.084 ;
    END
  END q[289]
  PIN q[28]
    DIRECTION OUTPUT ;
    USE SIGNAL ;
    PORT
      LAYER M5 ;
        RECT  10.8 0 10.824 0.084 ;
    END
  END q[28]
  PIN q[290]
    DIRECTION OUTPUT ;
    USE SIGNAL ;
    PORT
      LAYER M5 ;
        RECT  49.824 0 49.848 0.084 ;
    END
  END q[290]
  PIN q[291]
    DIRECTION OUTPUT ;
    USE SIGNAL ;
    PORT
      LAYER M5 ;
        RECT  49.968 0 49.992 0.084 ;
    END
  END q[291]
  PIN q[292]
    DIRECTION OUTPUT ;
    USE SIGNAL ;
    PORT
      LAYER M5 ;
        RECT  50.112 0 50.136 0.084 ;
    END
  END q[292]
  PIN q[293]
    DIRECTION OUTPUT ;
    USE SIGNAL ;
    PORT
      LAYER M5 ;
        RECT  50.4 0 50.424 0.084 ;
    END
  END q[293]
  PIN q[294]
    DIRECTION OUTPUT ;
    USE SIGNAL ;
    PORT
      LAYER M5 ;
        RECT  50.256 0 50.28 0.084 ;
    END
  END q[294]
  PIN q[295]
    DIRECTION OUTPUT ;
    USE SIGNAL ;
    PORT
      LAYER M5 ;
        RECT  50.688 0 50.712 0.084 ;
    END
  END q[295]
  PIN q[296]
    DIRECTION OUTPUT ;
    USE SIGNAL ;
    PORT
      LAYER M5 ;
        RECT  50.544 0 50.568 0.084 ;
    END
  END q[296]
  PIN q[297]
    DIRECTION OUTPUT ;
    USE SIGNAL ;
    PORT
      LAYER M5 ;
        RECT  50.976 0 51 0.084 ;
    END
  END q[297]
  PIN q[298]
    DIRECTION OUTPUT ;
    USE SIGNAL ;
    PORT
      LAYER M5 ;
        RECT  50.832 0 50.856 0.084 ;
    END
  END q[298]
  PIN q[299]
    DIRECTION OUTPUT ;
    USE SIGNAL ;
    PORT
      LAYER M5 ;
        RECT  51.408 0 51.432 0.084 ;
    END
  END q[299]
  PIN q[29]
    DIRECTION OUTPUT ;
    USE SIGNAL ;
    PORT
      LAYER M5 ;
        RECT  10.656 0 10.68 0.084 ;
    END
  END q[29]
  PIN q[2]
    DIRECTION OUTPUT ;
    USE SIGNAL ;
    PORT
      LAYER M5 ;
        RECT  6.912 0 6.936 0.084 ;
    END
  END q[2]
  PIN q[300]
    DIRECTION OUTPUT ;
    USE SIGNAL ;
    PORT
      LAYER M5 ;
        RECT  51.12 0 51.144 0.084 ;
    END
  END q[300]
  PIN q[301]
    DIRECTION OUTPUT ;
    USE SIGNAL ;
    PORT
      LAYER M5 ;
        RECT  51.552 0 51.576 0.084 ;
    END
  END q[301]
  PIN q[302]
    DIRECTION OUTPUT ;
    USE SIGNAL ;
    PORT
      LAYER M5 ;
        RECT  51.264 0 51.288 0.084 ;
    END
  END q[302]
  PIN q[303]
    DIRECTION OUTPUT ;
    USE SIGNAL ;
    PORT
      LAYER M5 ;
        RECT  51.84 0 51.864 0.084 ;
    END
  END q[303]
  PIN q[304]
    DIRECTION OUTPUT ;
    USE SIGNAL ;
    PORT
      LAYER M5 ;
        RECT  51.696 0 51.72 0.084 ;
    END
  END q[304]
  PIN q[305]
    DIRECTION OUTPUT ;
    USE SIGNAL ;
    PORT
      LAYER M5 ;
        RECT  52.272 0 52.296 0.084 ;
    END
  END q[305]
  PIN q[306]
    DIRECTION OUTPUT ;
    USE SIGNAL ;
    PORT
      LAYER M5 ;
        RECT  51.984 0 52.008 0.084 ;
    END
  END q[306]
  PIN q[307]
    DIRECTION OUTPUT ;
    USE SIGNAL ;
    PORT
      LAYER M5 ;
        RECT  52.56 0 52.584 0.084 ;
    END
  END q[307]
  PIN q[308]
    DIRECTION OUTPUT ;
    USE SIGNAL ;
    PORT
      LAYER M5 ;
        RECT  52.128 0 52.152 0.084 ;
    END
  END q[308]
  PIN q[309]
    DIRECTION OUTPUT ;
    USE SIGNAL ;
    PORT
      LAYER M5 ;
        RECT  52.848 0 52.872 0.084 ;
    END
  END q[309]
  PIN q[30]
    DIRECTION OUTPUT ;
    USE SIGNAL ;
    PORT
      LAYER M5 ;
        RECT  11.088 0 11.112 0.084 ;
    END
  END q[30]
  PIN q[310]
    DIRECTION OUTPUT ;
    USE SIGNAL ;
    PORT
      LAYER M5 ;
        RECT  52.416 0 52.44 0.084 ;
    END
  END q[310]
  PIN q[311]
    DIRECTION OUTPUT ;
    USE SIGNAL ;
    PORT
      LAYER M5 ;
        RECT  52.992 0 53.016 0.084 ;
    END
  END q[311]
  PIN q[312]
    DIRECTION OUTPUT ;
    USE SIGNAL ;
    PORT
      LAYER M5 ;
        RECT  52.704 0 52.728 0.084 ;
    END
  END q[312]
  PIN q[313]
    DIRECTION OUTPUT ;
    USE SIGNAL ;
    PORT
      LAYER M5 ;
        RECT  53.136 0 53.16 0.084 ;
    END
  END q[313]
  PIN q[314]
    DIRECTION OUTPUT ;
    USE SIGNAL ;
    PORT
      LAYER M5 ;
        RECT  53.424 0 53.448 0.084 ;
    END
  END q[314]
  PIN q[315]
    DIRECTION OUTPUT ;
    USE SIGNAL ;
    PORT
      LAYER M5 ;
        RECT  53.28 0 53.304 0.084 ;
    END
  END q[315]
  PIN q[316]
    DIRECTION OUTPUT ;
    USE SIGNAL ;
    PORT
      LAYER M5 ;
        RECT  53.712 0 53.736 0.084 ;
    END
  END q[316]
  PIN q[317]
    DIRECTION OUTPUT ;
    USE SIGNAL ;
    PORT
      LAYER M5 ;
        RECT  53.568 0 53.592 0.084 ;
    END
  END q[317]
  PIN q[318]
    DIRECTION OUTPUT ;
    USE SIGNAL ;
    PORT
      LAYER M5 ;
        RECT  54 0 54.024 0.084 ;
    END
  END q[318]
  PIN q[319]
    DIRECTION OUTPUT ;
    USE SIGNAL ;
    PORT
      LAYER M5 ;
        RECT  53.856 0 53.88 0.084 ;
    END
  END q[319]
  PIN q[31]
    DIRECTION OUTPUT ;
    USE SIGNAL ;
    PORT
      LAYER M5 ;
        RECT  10.944 0 10.968 0.084 ;
    END
  END q[31]
  PIN q[320]
    DIRECTION OUTPUT ;
    USE SIGNAL ;
    PORT
      LAYER M5 ;
        RECT  54.288 0 54.312 0.084 ;
    END
  END q[320]
  PIN q[321]
    DIRECTION OUTPUT ;
    USE SIGNAL ;
    PORT
      LAYER M5 ;
        RECT  54.144 0 54.168 0.084 ;
    END
  END q[321]
  PIN q[322]
    DIRECTION OUTPUT ;
    USE SIGNAL ;
    PORT
      LAYER M5 ;
        RECT  54.576 0 54.6 0.084 ;
    END
  END q[322]
  PIN q[323]
    DIRECTION OUTPUT ;
    USE SIGNAL ;
    PORT
      LAYER M5 ;
        RECT  54.432 0 54.456 0.084 ;
    END
  END q[323]
  PIN q[324]
    DIRECTION OUTPUT ;
    USE SIGNAL ;
    PORT
      LAYER M5 ;
        RECT  54.72 0 54.744 0.084 ;
    END
  END q[324]
  PIN q[325]
    DIRECTION OUTPUT ;
    USE SIGNAL ;
    PORT
      LAYER M5 ;
        RECT  54.864 0 54.888 0.084 ;
    END
  END q[325]
  PIN q[326]
    DIRECTION OUTPUT ;
    USE SIGNAL ;
    PORT
      LAYER M5 ;
        RECT  55.008 0 55.032 0.084 ;
    END
  END q[326]
  PIN q[327]
    DIRECTION OUTPUT ;
    USE SIGNAL ;
    PORT
      LAYER M5 ;
        RECT  55.152 0 55.176 0.084 ;
    END
  END q[327]
  PIN q[328]
    DIRECTION OUTPUT ;
    USE SIGNAL ;
    PORT
      LAYER M5 ;
        RECT  55.296 0 55.32 0.084 ;
    END
  END q[328]
  PIN q[329]
    DIRECTION OUTPUT ;
    USE SIGNAL ;
    PORT
      LAYER M5 ;
        RECT  55.44 0 55.464 0.084 ;
    END
  END q[329]
  PIN q[32]
    DIRECTION OUTPUT ;
    USE SIGNAL ;
    PORT
      LAYER M5 ;
        RECT  11.376 0 11.4 0.084 ;
    END
  END q[32]
  PIN q[330]
    DIRECTION OUTPUT ;
    USE SIGNAL ;
    PORT
      LAYER M5 ;
        RECT  55.584 0 55.608 0.084 ;
    END
  END q[330]
  PIN q[331]
    DIRECTION OUTPUT ;
    USE SIGNAL ;
    PORT
      LAYER M5 ;
        RECT  55.728 0 55.752 0.084 ;
    END
  END q[331]
  PIN q[332]
    DIRECTION OUTPUT ;
    USE SIGNAL ;
    PORT
      LAYER M5 ;
        RECT  55.872 0 55.896 0.084 ;
    END
  END q[332]
  PIN q[333]
    DIRECTION OUTPUT ;
    USE SIGNAL ;
    PORT
      LAYER M5 ;
        RECT  56.016 0 56.04 0.084 ;
    END
  END q[333]
  PIN q[334]
    DIRECTION OUTPUT ;
    USE SIGNAL ;
    PORT
      LAYER M5 ;
        RECT  56.16 0 56.184 0.084 ;
    END
  END q[334]
  PIN q[335]
    DIRECTION OUTPUT ;
    USE SIGNAL ;
    PORT
      LAYER M5 ;
        RECT  56.448 0 56.472 0.084 ;
    END
  END q[335]
  PIN q[336]
    DIRECTION OUTPUT ;
    USE SIGNAL ;
    PORT
      LAYER M5 ;
        RECT  56.304 0 56.328 0.084 ;
    END
  END q[336]
  PIN q[337]
    DIRECTION OUTPUT ;
    USE SIGNAL ;
    PORT
      LAYER M5 ;
        RECT  56.736 0 56.76 0.084 ;
    END
  END q[337]
  PIN q[338]
    DIRECTION OUTPUT ;
    USE SIGNAL ;
    PORT
      LAYER M5 ;
        RECT  56.592 0 56.616 0.084 ;
    END
  END q[338]
  PIN q[339]
    DIRECTION OUTPUT ;
    USE SIGNAL ;
    PORT
      LAYER M5 ;
        RECT  57.024 0 57.048 0.084 ;
    END
  END q[339]
  PIN q[33]
    DIRECTION OUTPUT ;
    USE SIGNAL ;
    PORT
      LAYER M5 ;
        RECT  11.232 0 11.256 0.084 ;
    END
  END q[33]
  PIN q[340]
    DIRECTION OUTPUT ;
    USE SIGNAL ;
    PORT
      LAYER M5 ;
        RECT  56.88 0 56.904 0.084 ;
    END
  END q[340]
  PIN q[341]
    DIRECTION OUTPUT ;
    USE SIGNAL ;
    PORT
      LAYER M5 ;
        RECT  57.312 0 57.336 0.084 ;
    END
  END q[341]
  PIN q[342]
    DIRECTION OUTPUT ;
    USE SIGNAL ;
    PORT
      LAYER M5 ;
        RECT  57.168 0 57.192 0.084 ;
    END
  END q[342]
  PIN q[343]
    DIRECTION OUTPUT ;
    USE SIGNAL ;
    PORT
      LAYER M5 ;
        RECT  57.6 0 57.624 0.084 ;
    END
  END q[343]
  PIN q[344]
    DIRECTION OUTPUT ;
    USE SIGNAL ;
    PORT
      LAYER M5 ;
        RECT  57.456 0 57.48 0.084 ;
    END
  END q[344]
  PIN q[345]
    DIRECTION OUTPUT ;
    USE SIGNAL ;
    PORT
      LAYER M5 ;
        RECT  57.888 0 57.912 0.084 ;
    END
  END q[345]
  PIN q[346]
    DIRECTION OUTPUT ;
    USE SIGNAL ;
    PORT
      LAYER M5 ;
        RECT  57.744 0 57.768 0.084 ;
    END
  END q[346]
  PIN q[347]
    DIRECTION OUTPUT ;
    USE SIGNAL ;
    PORT
      LAYER M5 ;
        RECT  58.176 0 58.2 0.084 ;
    END
  END q[347]
  PIN q[348]
    DIRECTION OUTPUT ;
    USE SIGNAL ;
    PORT
      LAYER M5 ;
        RECT  58.032 0 58.056 0.084 ;
    END
  END q[348]
  PIN q[349]
    DIRECTION OUTPUT ;
    USE SIGNAL ;
    PORT
      LAYER M5 ;
        RECT  58.608 0 58.632 0.084 ;
    END
  END q[349]
  PIN q[34]
    DIRECTION OUTPUT ;
    USE SIGNAL ;
    PORT
      LAYER M5 ;
        RECT  11.664 0 11.688 0.084 ;
    END
  END q[34]
  PIN q[350]
    DIRECTION OUTPUT ;
    USE SIGNAL ;
    PORT
      LAYER M5 ;
        RECT  58.32 0 58.344 0.084 ;
    END
  END q[350]
  PIN q[351]
    DIRECTION OUTPUT ;
    USE SIGNAL ;
    PORT
      LAYER M5 ;
        RECT  58.752 0 58.776 0.084 ;
    END
  END q[351]
  PIN q[352]
    DIRECTION OUTPUT ;
    USE SIGNAL ;
    PORT
      LAYER M5 ;
        RECT  58.464 0 58.488 0.084 ;
    END
  END q[352]
  PIN q[353]
    DIRECTION OUTPUT ;
    USE SIGNAL ;
    PORT
      LAYER M5 ;
        RECT  59.184 0 59.208 0.084 ;
    END
  END q[353]
  PIN q[354]
    DIRECTION OUTPUT ;
    USE SIGNAL ;
    PORT
      LAYER M5 ;
        RECT  58.896 0 58.92 0.084 ;
    END
  END q[354]
  PIN q[355]
    DIRECTION OUTPUT ;
    USE SIGNAL ;
    PORT
      LAYER M5 ;
        RECT  59.472 0 59.496 0.084 ;
    END
  END q[355]
  PIN q[356]
    DIRECTION OUTPUT ;
    USE SIGNAL ;
    PORT
      LAYER M5 ;
        RECT  59.04 0 59.064 0.084 ;
    END
  END q[356]
  PIN q[357]
    DIRECTION OUTPUT ;
    USE SIGNAL ;
    PORT
      LAYER M5 ;
        RECT  59.76 0 59.784 0.084 ;
    END
  END q[357]
  PIN q[358]
    DIRECTION OUTPUT ;
    USE SIGNAL ;
    PORT
      LAYER M5 ;
        RECT  59.328 0 59.352 0.084 ;
    END
  END q[358]
  PIN q[359]
    DIRECTION OUTPUT ;
    USE SIGNAL ;
    PORT
      LAYER M5 ;
        RECT  60.048 0 60.072 0.084 ;
    END
  END q[359]
  PIN q[35]
    DIRECTION OUTPUT ;
    USE SIGNAL ;
    PORT
      LAYER M5 ;
        RECT  11.52 0 11.544 0.084 ;
    END
  END q[35]
  PIN q[360]
    DIRECTION OUTPUT ;
    USE SIGNAL ;
    PORT
      LAYER M5 ;
        RECT  59.616 0 59.64 0.084 ;
    END
  END q[360]
  PIN q[361]
    DIRECTION OUTPUT ;
    USE SIGNAL ;
    PORT
      LAYER M5 ;
        RECT  60.192 0 60.216 0.084 ;
    END
  END q[361]
  PIN q[362]
    DIRECTION OUTPUT ;
    USE SIGNAL ;
    PORT
      LAYER M5 ;
        RECT  59.904 0 59.928 0.084 ;
    END
  END q[362]
  PIN q[363]
    DIRECTION OUTPUT ;
    USE SIGNAL ;
    PORT
      LAYER M5 ;
        RECT  60.336 0 60.36 0.084 ;
    END
  END q[363]
  PIN q[364]
    DIRECTION OUTPUT ;
    USE SIGNAL ;
    PORT
      LAYER M5 ;
        RECT  60.624 0 60.648 0.084 ;
    END
  END q[364]
  PIN q[365]
    DIRECTION OUTPUT ;
    USE SIGNAL ;
    PORT
      LAYER M5 ;
        RECT  60.48 0 60.504 0.084 ;
    END
  END q[365]
  PIN q[366]
    DIRECTION OUTPUT ;
    USE SIGNAL ;
    PORT
      LAYER M5 ;
        RECT  60.912 0 60.936 0.084 ;
    END
  END q[366]
  PIN q[367]
    DIRECTION OUTPUT ;
    USE SIGNAL ;
    PORT
      LAYER M5 ;
        RECT  60.768 0 60.792 0.084 ;
    END
  END q[367]
  PIN q[368]
    DIRECTION OUTPUT ;
    USE SIGNAL ;
    PORT
      LAYER M5 ;
        RECT  61.2 0 61.224 0.084 ;
    END
  END q[368]
  PIN q[369]
    DIRECTION OUTPUT ;
    USE SIGNAL ;
    PORT
      LAYER M5 ;
        RECT  61.056 0 61.08 0.084 ;
    END
  END q[369]
  PIN q[36]
    DIRECTION OUTPUT ;
    USE SIGNAL ;
    PORT
      LAYER M5 ;
        RECT  11.952 0 11.976 0.084 ;
    END
  END q[36]
  PIN q[370]
    DIRECTION OUTPUT ;
    USE SIGNAL ;
    PORT
      LAYER M5 ;
        RECT  61.344 0 61.368 0.084 ;
    END
  END q[370]
  PIN q[371]
    DIRECTION OUTPUT ;
    USE SIGNAL ;
    PORT
      LAYER M5 ;
        RECT  61.488 0 61.512 0.084 ;
    END
  END q[371]
  PIN q[372]
    DIRECTION OUTPUT ;
    USE SIGNAL ;
    PORT
      LAYER M5 ;
        RECT  61.776 0 61.8 0.084 ;
    END
  END q[372]
  PIN q[373]
    DIRECTION OUTPUT ;
    USE SIGNAL ;
    PORT
      LAYER M5 ;
        RECT  61.632 0 61.656 0.084 ;
    END
  END q[373]
  PIN q[374]
    DIRECTION OUTPUT ;
    USE SIGNAL ;
    PORT
      LAYER M5 ;
        RECT  61.92 0 61.944 0.084 ;
    END
  END q[374]
  PIN q[375]
    DIRECTION OUTPUT ;
    USE SIGNAL ;
    PORT
      LAYER M5 ;
        RECT  62.064 0 62.088 0.084 ;
    END
  END q[375]
  PIN q[376]
    DIRECTION OUTPUT ;
    USE SIGNAL ;
    PORT
      LAYER M5 ;
        RECT  62.208 0 62.232 0.084 ;
    END
  END q[376]
  PIN q[377]
    DIRECTION OUTPUT ;
    USE SIGNAL ;
    PORT
      LAYER M5 ;
        RECT  62.352 0 62.376 0.084 ;
    END
  END q[377]
  PIN q[378]
    DIRECTION OUTPUT ;
    USE SIGNAL ;
    PORT
      LAYER M5 ;
        RECT  62.496 0 62.52 0.084 ;
    END
  END q[378]
  PIN q[379]
    DIRECTION OUTPUT ;
    USE SIGNAL ;
    PORT
      LAYER M5 ;
        RECT  62.64 0 62.664 0.084 ;
    END
  END q[379]
  PIN q[37]
    DIRECTION OUTPUT ;
    USE SIGNAL ;
    PORT
      LAYER M5 ;
        RECT  11.808 0 11.832 0.084 ;
    END
  END q[37]
  PIN q[380]
    DIRECTION OUTPUT ;
    USE SIGNAL ;
    PORT
      LAYER M5 ;
        RECT  62.784 0 62.808 0.084 ;
    END
  END q[380]
  PIN q[381]
    DIRECTION OUTPUT ;
    USE SIGNAL ;
    PORT
      LAYER M5 ;
        RECT  62.928 0 62.952 0.084 ;
    END
  END q[381]
  PIN q[382]
    DIRECTION OUTPUT ;
    USE SIGNAL ;
    PORT
      LAYER M5 ;
        RECT  63.072 0 63.096 0.084 ;
    END
  END q[382]
  PIN q[383]
    DIRECTION OUTPUT ;
    USE SIGNAL ;
    PORT
      LAYER M5 ;
        RECT  63.216 0 63.24 0.084 ;
    END
  END q[383]
  PIN q[384]
    DIRECTION OUTPUT ;
    USE SIGNAL ;
    PORT
      LAYER M5 ;
        RECT  63.36 0 63.384 0.084 ;
    END
  END q[384]
  PIN q[385]
    DIRECTION OUTPUT ;
    USE SIGNAL ;
    PORT
      LAYER M5 ;
        RECT  63.648 0 63.672 0.084 ;
    END
  END q[385]
  PIN q[386]
    DIRECTION OUTPUT ;
    USE SIGNAL ;
    PORT
      LAYER M5 ;
        RECT  63.504 0 63.528 0.084 ;
    END
  END q[386]
  PIN q[387]
    DIRECTION OUTPUT ;
    USE SIGNAL ;
    PORT
      LAYER M5 ;
        RECT  63.936 0 63.96 0.084 ;
    END
  END q[387]
  PIN q[388]
    DIRECTION OUTPUT ;
    USE SIGNAL ;
    PORT
      LAYER M5 ;
        RECT  63.792 0 63.816 0.084 ;
    END
  END q[388]
  PIN q[389]
    DIRECTION OUTPUT ;
    USE SIGNAL ;
    PORT
      LAYER M5 ;
        RECT  64.224 0 64.248 0.084 ;
    END
  END q[389]
  PIN q[38]
    DIRECTION OUTPUT ;
    USE SIGNAL ;
    PORT
      LAYER M5 ;
        RECT  12.096 0 12.12 0.084 ;
    END
  END q[38]
  PIN q[390]
    DIRECTION OUTPUT ;
    USE SIGNAL ;
    PORT
      LAYER M5 ;
        RECT  64.08 0 64.104 0.084 ;
    END
  END q[390]
  PIN q[391]
    DIRECTION OUTPUT ;
    USE SIGNAL ;
    PORT
      LAYER M5 ;
        RECT  64.512 0 64.536 0.084 ;
    END
  END q[391]
  PIN q[392]
    DIRECTION OUTPUT ;
    USE SIGNAL ;
    PORT
      LAYER M5 ;
        RECT  64.368 0 64.392 0.084 ;
    END
  END q[392]
  PIN q[393]
    DIRECTION OUTPUT ;
    USE SIGNAL ;
    PORT
      LAYER M5 ;
        RECT  64.8 0 64.824 0.084 ;
    END
  END q[393]
  PIN q[394]
    DIRECTION OUTPUT ;
    USE SIGNAL ;
    PORT
      LAYER M5 ;
        RECT  64.656 0 64.68 0.084 ;
    END
  END q[394]
  PIN q[395]
    DIRECTION OUTPUT ;
    USE SIGNAL ;
    PORT
      LAYER M5 ;
        RECT  65.088 0 65.112 0.084 ;
    END
  END q[395]
  PIN q[396]
    DIRECTION OUTPUT ;
    USE SIGNAL ;
    PORT
      LAYER M5 ;
        RECT  64.944 0 64.968 0.084 ;
    END
  END q[396]
  PIN q[397]
    DIRECTION OUTPUT ;
    USE SIGNAL ;
    PORT
      LAYER M5 ;
        RECT  65.376 0 65.4 0.084 ;
    END
  END q[397]
  PIN q[398]
    DIRECTION OUTPUT ;
    USE SIGNAL ;
    PORT
      LAYER M5 ;
        RECT  65.232 0 65.256 0.084 ;
    END
  END q[398]
  PIN q[399]
    DIRECTION OUTPUT ;
    USE SIGNAL ;
    PORT
      LAYER M5 ;
        RECT  65.808 0 65.832 0.084 ;
    END
  END q[399]
  PIN q[39]
    DIRECTION OUTPUT ;
    USE SIGNAL ;
    PORT
      LAYER M5 ;
        RECT  12.24 0 12.264 0.084 ;
    END
  END q[39]
  PIN q[3]
    DIRECTION OUTPUT ;
    USE SIGNAL ;
    PORT
      LAYER M5 ;
        RECT  7.056 0 7.08 0.084 ;
    END
  END q[3]
  PIN q[400]
    DIRECTION OUTPUT ;
    USE SIGNAL ;
    PORT
      LAYER M5 ;
        RECT  65.52 0 65.544 0.084 ;
    END
  END q[400]
  PIN q[401]
    DIRECTION OUTPUT ;
    USE SIGNAL ;
    PORT
      LAYER M5 ;
        RECT  66.096 0 66.12 0.084 ;
    END
  END q[401]
  PIN q[402]
    DIRECTION OUTPUT ;
    USE SIGNAL ;
    PORT
      LAYER M5 ;
        RECT  65.664 0 65.688 0.084 ;
    END
  END q[402]
  PIN q[403]
    DIRECTION OUTPUT ;
    USE SIGNAL ;
    PORT
      LAYER M5 ;
        RECT  66.384 0 66.408 0.084 ;
    END
  END q[403]
  PIN q[404]
    DIRECTION OUTPUT ;
    USE SIGNAL ;
    PORT
      LAYER M5 ;
        RECT  65.952 0 65.976 0.084 ;
    END
  END q[404]
  PIN q[405]
    DIRECTION OUTPUT ;
    USE SIGNAL ;
    PORT
      LAYER M5 ;
        RECT  66.672 0 66.696 0.084 ;
    END
  END q[405]
  PIN q[406]
    DIRECTION OUTPUT ;
    USE SIGNAL ;
    PORT
      LAYER M5 ;
        RECT  66.24 0 66.264 0.084 ;
    END
  END q[406]
  PIN q[407]
    DIRECTION OUTPUT ;
    USE SIGNAL ;
    PORT
      LAYER M5 ;
        RECT  66.96 0 66.984 0.084 ;
    END
  END q[407]
  PIN q[408]
    DIRECTION OUTPUT ;
    USE SIGNAL ;
    PORT
      LAYER M5 ;
        RECT  66.528 0 66.552 0.084 ;
    END
  END q[408]
  PIN q[409]
    DIRECTION OUTPUT ;
    USE SIGNAL ;
    PORT
      LAYER M5 ;
        RECT  67.248 0 67.272 0.084 ;
    END
  END q[409]
  PIN q[40]
    DIRECTION OUTPUT ;
    USE SIGNAL ;
    PORT
      LAYER M5 ;
        RECT  12.384 0 12.408 0.084 ;
    END
  END q[40]
  PIN q[410]
    DIRECTION OUTPUT ;
    USE SIGNAL ;
    PORT
      LAYER M5 ;
        RECT  66.816 0 66.84 0.084 ;
    END
  END q[410]
  PIN q[411]
    DIRECTION OUTPUT ;
    USE SIGNAL ;
    PORT
      LAYER M5 ;
        RECT  67.392 0 67.416 0.084 ;
    END
  END q[411]
  PIN q[412]
    DIRECTION OUTPUT ;
    USE SIGNAL ;
    PORT
      LAYER M5 ;
        RECT  67.104 0 67.128 0.084 ;
    END
  END q[412]
  PIN q[413]
    DIRECTION OUTPUT ;
    USE SIGNAL ;
    PORT
      LAYER M5 ;
        RECT  67.536 0 67.56 0.084 ;
    END
  END q[413]
  PIN q[414]
    DIRECTION OUTPUT ;
    USE SIGNAL ;
    PORT
      LAYER M5 ;
        RECT  67.68 0 67.704 0.084 ;
    END
  END q[414]
  PIN q[415]
    DIRECTION OUTPUT ;
    USE SIGNAL ;
    PORT
      LAYER M5 ;
        RECT  67.824 0 67.848 0.084 ;
    END
  END q[415]
  PIN q[416]
    DIRECTION OUTPUT ;
    USE SIGNAL ;
    PORT
      LAYER M5 ;
        RECT  67.968 0 67.992 0.084 ;
    END
  END q[416]
  PIN q[417]
    DIRECTION OUTPUT ;
    USE SIGNAL ;
    PORT
      LAYER M5 ;
        RECT  68.112 0 68.136 0.084 ;
    END
  END q[417]
  PIN q[418]
    DIRECTION OUTPUT ;
    USE SIGNAL ;
    PORT
      LAYER M5 ;
        RECT  68.256 0 68.28 0.084 ;
    END
  END q[418]
  PIN q[419]
    DIRECTION OUTPUT ;
    USE SIGNAL ;
    PORT
      LAYER M5 ;
        RECT  68.4 0 68.424 0.084 ;
    END
  END q[419]
  PIN q[41]
    DIRECTION OUTPUT ;
    USE SIGNAL ;
    PORT
      LAYER M5 ;
        RECT  12.528 0 12.552 0.084 ;
    END
  END q[41]
  PIN q[420]
    DIRECTION OUTPUT ;
    USE SIGNAL ;
    PORT
      LAYER M5 ;
        RECT  68.544 0 68.568 0.084 ;
    END
  END q[420]
  PIN q[421]
    DIRECTION OUTPUT ;
    USE SIGNAL ;
    PORT
      LAYER M5 ;
        RECT  68.688 0 68.712 0.084 ;
    END
  END q[421]
  PIN q[422]
    DIRECTION OUTPUT ;
    USE SIGNAL ;
    PORT
      LAYER M5 ;
        RECT  68.832 0 68.856 0.084 ;
    END
  END q[422]
  PIN q[423]
    DIRECTION OUTPUT ;
    USE SIGNAL ;
    PORT
      LAYER M5 ;
        RECT  68.976 0 69 0.084 ;
    END
  END q[423]
  PIN q[424]
    DIRECTION OUTPUT ;
    USE SIGNAL ;
    PORT
      LAYER M5 ;
        RECT  69.12 0 69.144 0.084 ;
    END
  END q[424]
  PIN q[425]
    DIRECTION OUTPUT ;
    USE SIGNAL ;
    PORT
      LAYER M5 ;
        RECT  69.264 0 69.288 0.084 ;
    END
  END q[425]
  PIN q[426]
    DIRECTION OUTPUT ;
    USE SIGNAL ;
    PORT
      LAYER M5 ;
        RECT  69.408 0 69.432 0.084 ;
    END
  END q[426]
  PIN q[427]
    DIRECTION OUTPUT ;
    USE SIGNAL ;
    PORT
      LAYER M5 ;
        RECT  69.552 0 69.576 0.084 ;
    END
  END q[427]
  PIN q[428]
    DIRECTION OUTPUT ;
    USE SIGNAL ;
    PORT
      LAYER M5 ;
        RECT  69.696 0 69.72 0.084 ;
    END
  END q[428]
  PIN q[429]
    DIRECTION OUTPUT ;
    USE SIGNAL ;
    PORT
      LAYER M5 ;
        RECT  69.984 0 70.008 0.084 ;
    END
  END q[429]
  PIN q[42]
    DIRECTION OUTPUT ;
    USE SIGNAL ;
    PORT
      LAYER M5 ;
        RECT  12.672 0 12.696 0.084 ;
    END
  END q[42]
  PIN q[430]
    DIRECTION OUTPUT ;
    USE SIGNAL ;
    PORT
      LAYER M5 ;
        RECT  69.84 0 69.864 0.084 ;
    END
  END q[430]
  PIN q[431]
    DIRECTION OUTPUT ;
    USE SIGNAL ;
    PORT
      LAYER M5 ;
        RECT  70.272 0 70.296 0.084 ;
    END
  END q[431]
  PIN q[432]
    DIRECTION OUTPUT ;
    USE SIGNAL ;
    PORT
      LAYER M5 ;
        RECT  70.128 0 70.152 0.084 ;
    END
  END q[432]
  PIN q[433]
    DIRECTION OUTPUT ;
    USE SIGNAL ;
    PORT
      LAYER M5 ;
        RECT  70.56 0 70.584 0.084 ;
    END
  END q[433]
  PIN q[434]
    DIRECTION OUTPUT ;
    USE SIGNAL ;
    PORT
      LAYER M5 ;
        RECT  70.416 0 70.44 0.084 ;
    END
  END q[434]
  PIN q[435]
    DIRECTION OUTPUT ;
    USE SIGNAL ;
    PORT
      LAYER M5 ;
        RECT  70.848 0 70.872 0.084 ;
    END
  END q[435]
  PIN q[436]
    DIRECTION OUTPUT ;
    USE SIGNAL ;
    PORT
      LAYER M5 ;
        RECT  70.704 0 70.728 0.084 ;
    END
  END q[436]
  PIN q[437]
    DIRECTION OUTPUT ;
    USE SIGNAL ;
    PORT
      LAYER M5 ;
        RECT  71.136 0 71.16 0.084 ;
    END
  END q[437]
  PIN q[438]
    DIRECTION OUTPUT ;
    USE SIGNAL ;
    PORT
      LAYER M5 ;
        RECT  70.992 0 71.016 0.084 ;
    END
  END q[438]
  PIN q[439]
    DIRECTION OUTPUT ;
    USE SIGNAL ;
    PORT
      LAYER M5 ;
        RECT  71.424 0 71.448 0.084 ;
    END
  END q[439]
  PIN q[43]
    DIRECTION OUTPUT ;
    USE SIGNAL ;
    PORT
      LAYER M5 ;
        RECT  12.816 0 12.84 0.084 ;
    END
  END q[43]
  PIN q[440]
    DIRECTION OUTPUT ;
    USE SIGNAL ;
    PORT
      LAYER M5 ;
        RECT  71.28 0 71.304 0.084 ;
    END
  END q[440]
  PIN q[441]
    DIRECTION OUTPUT ;
    USE SIGNAL ;
    PORT
      LAYER M5 ;
        RECT  71.712 0 71.736 0.084 ;
    END
  END q[441]
  PIN q[442]
    DIRECTION OUTPUT ;
    USE SIGNAL ;
    PORT
      LAYER M5 ;
        RECT  71.568 0 71.592 0.084 ;
    END
  END q[442]
  PIN q[443]
    DIRECTION OUTPUT ;
    USE SIGNAL ;
    PORT
      LAYER M5 ;
        RECT  72 0 72.024 0.084 ;
    END
  END q[443]
  PIN q[444]
    DIRECTION OUTPUT ;
    USE SIGNAL ;
    PORT
      LAYER M5 ;
        RECT  71.856 0 71.88 0.084 ;
    END
  END q[444]
  PIN q[445]
    DIRECTION OUTPUT ;
    USE SIGNAL ;
    PORT
      LAYER M5 ;
        RECT  72.432 0 72.456 0.084 ;
    END
  END q[445]
  PIN q[446]
    DIRECTION OUTPUT ;
    USE SIGNAL ;
    PORT
      LAYER M5 ;
        RECT  72.144 0 72.168 0.084 ;
    END
  END q[446]
  PIN q[447]
    DIRECTION OUTPUT ;
    USE SIGNAL ;
    PORT
      LAYER M5 ;
        RECT  72.72 0 72.744 0.084 ;
    END
  END q[447]
  PIN q[448]
    DIRECTION OUTPUT ;
    USE SIGNAL ;
    PORT
      LAYER M5 ;
        RECT  72.288 0 72.312 0.084 ;
    END
  END q[448]
  PIN q[449]
    DIRECTION OUTPUT ;
    USE SIGNAL ;
    PORT
      LAYER M5 ;
        RECT  73.008 0 73.032 0.084 ;
    END
  END q[449]
  PIN q[44]
    DIRECTION OUTPUT ;
    USE SIGNAL ;
    PORT
      LAYER M5 ;
        RECT  12.96 0 12.984 0.084 ;
    END
  END q[44]
  PIN q[450]
    DIRECTION OUTPUT ;
    USE SIGNAL ;
    PORT
      LAYER M5 ;
        RECT  72.576 0 72.6 0.084 ;
    END
  END q[450]
  PIN q[451]
    DIRECTION OUTPUT ;
    USE SIGNAL ;
    PORT
      LAYER M5 ;
        RECT  73.296 0 73.32 0.084 ;
    END
  END q[451]
  PIN q[452]
    DIRECTION OUTPUT ;
    USE SIGNAL ;
    PORT
      LAYER M5 ;
        RECT  72.864 0 72.888 0.084 ;
    END
  END q[452]
  PIN q[453]
    DIRECTION OUTPUT ;
    USE SIGNAL ;
    PORT
      LAYER M5 ;
        RECT  73.584 0 73.608 0.084 ;
    END
  END q[453]
  PIN q[454]
    DIRECTION OUTPUT ;
    USE SIGNAL ;
    PORT
      LAYER M5 ;
        RECT  73.152 0 73.176 0.084 ;
    END
  END q[454]
  PIN q[455]
    DIRECTION OUTPUT ;
    USE SIGNAL ;
    PORT
      LAYER M5 ;
        RECT  73.872 0 73.896 0.084 ;
    END
  END q[455]
  PIN q[456]
    DIRECTION OUTPUT ;
    USE SIGNAL ;
    PORT
      LAYER M5 ;
        RECT  73.44 0 73.464 0.084 ;
    END
  END q[456]
  PIN q[457]
    DIRECTION OUTPUT ;
    USE SIGNAL ;
    PORT
      LAYER M5 ;
        RECT  74.16 0 74.184 0.084 ;
    END
  END q[457]
  PIN q[458]
    DIRECTION OUTPUT ;
    USE SIGNAL ;
    PORT
      LAYER M5 ;
        RECT  73.728 0 73.752 0.084 ;
    END
  END q[458]
  PIN q[459]
    DIRECTION OUTPUT ;
    USE SIGNAL ;
    PORT
      LAYER M5 ;
        RECT  74.448 0 74.472 0.084 ;
    END
  END q[459]
  PIN q[45]
    DIRECTION OUTPUT ;
    USE SIGNAL ;
    PORT
      LAYER M5 ;
        RECT  13.104 0 13.128 0.084 ;
    END
  END q[45]
  PIN q[460]
    DIRECTION OUTPUT ;
    USE SIGNAL ;
    PORT
      LAYER M5 ;
        RECT  74.016 0 74.04 0.084 ;
    END
  END q[460]
  PIN q[461]
    DIRECTION OUTPUT ;
    USE SIGNAL ;
    PORT
      LAYER M5 ;
        RECT  74.592 0 74.616 0.084 ;
    END
  END q[461]
  PIN q[462]
    DIRECTION OUTPUT ;
    USE SIGNAL ;
    PORT
      LAYER M5 ;
        RECT  74.304 0 74.328 0.084 ;
    END
  END q[462]
  PIN q[463]
    DIRECTION OUTPUT ;
    USE SIGNAL ;
    PORT
      LAYER M5 ;
        RECT  74.736 0 74.76 0.084 ;
    END
  END q[463]
  PIN q[464]
    DIRECTION OUTPUT ;
    USE SIGNAL ;
    PORT
      LAYER M5 ;
        RECT  74.88 0 74.904 0.084 ;
    END
  END q[464]
  PIN q[465]
    DIRECTION OUTPUT ;
    USE SIGNAL ;
    PORT
      LAYER M5 ;
        RECT  75.024 0 75.048 0.084 ;
    END
  END q[465]
  PIN q[466]
    DIRECTION OUTPUT ;
    USE SIGNAL ;
    PORT
      LAYER M5 ;
        RECT  75.168 0 75.192 0.084 ;
    END
  END q[466]
  PIN q[467]
    DIRECTION OUTPUT ;
    USE SIGNAL ;
    PORT
      LAYER M5 ;
        RECT  75.312 0 75.336 0.084 ;
    END
  END q[467]
  PIN q[468]
    DIRECTION OUTPUT ;
    USE SIGNAL ;
    PORT
      LAYER M5 ;
        RECT  75.456 0 75.48 0.084 ;
    END
  END q[468]
  PIN q[469]
    DIRECTION OUTPUT ;
    USE SIGNAL ;
    PORT
      LAYER M5 ;
        RECT  75.6 0 75.624 0.084 ;
    END
  END q[469]
  PIN q[46]
    DIRECTION OUTPUT ;
    USE SIGNAL ;
    PORT
      LAYER M5 ;
        RECT  13.248 0 13.272 0.084 ;
    END
  END q[46]
  PIN q[470]
    DIRECTION OUTPUT ;
    USE SIGNAL ;
    PORT
      LAYER M5 ;
        RECT  75.744 0 75.768 0.084 ;
    END
  END q[470]
  PIN q[471]
    DIRECTION OUTPUT ;
    USE SIGNAL ;
    PORT
      LAYER M5 ;
        RECT  75.888 0 75.912 0.084 ;
    END
  END q[471]
  PIN q[472]
    DIRECTION OUTPUT ;
    USE SIGNAL ;
    PORT
      LAYER M5 ;
        RECT  76.032 0 76.056 0.084 ;
    END
  END q[472]
  PIN q[473]
    DIRECTION OUTPUT ;
    USE SIGNAL ;
    PORT
      LAYER M5 ;
        RECT  76.176 0 76.2 0.084 ;
    END
  END q[473]
  PIN q[474]
    DIRECTION OUTPUT ;
    USE SIGNAL ;
    PORT
      LAYER M5 ;
        RECT  76.32 0 76.344 0.084 ;
    END
  END q[474]
  PIN q[475]
    DIRECTION OUTPUT ;
    USE SIGNAL ;
    PORT
      LAYER M5 ;
        RECT  76.464 0 76.488 0.084 ;
    END
  END q[475]
  PIN q[476]
    DIRECTION OUTPUT ;
    USE SIGNAL ;
    PORT
      LAYER M5 ;
        RECT  76.608 0 76.632 0.084 ;
    END
  END q[476]
  PIN q[477]
    DIRECTION OUTPUT ;
    USE SIGNAL ;
    PORT
      LAYER M5 ;
        RECT  76.896 0 76.92 0.084 ;
    END
  END q[477]
  PIN q[478]
    DIRECTION OUTPUT ;
    USE SIGNAL ;
    PORT
      LAYER M5 ;
        RECT  76.752 0 76.776 0.084 ;
    END
  END q[478]
  PIN q[479]
    DIRECTION OUTPUT ;
    USE SIGNAL ;
    PORT
      LAYER M5 ;
        RECT  77.184 0 77.208 0.084 ;
    END
  END q[479]
  PIN q[47]
    DIRECTION OUTPUT ;
    USE SIGNAL ;
    PORT
      LAYER M5 ;
        RECT  13.392 0 13.416 0.084 ;
    END
  END q[47]
  PIN q[480]
    DIRECTION OUTPUT ;
    USE SIGNAL ;
    PORT
      LAYER M5 ;
        RECT  77.04 0 77.064 0.084 ;
    END
  END q[480]
  PIN q[481]
    DIRECTION OUTPUT ;
    USE SIGNAL ;
    PORT
      LAYER M5 ;
        RECT  77.472 0 77.496 0.084 ;
    END
  END q[481]
  PIN q[482]
    DIRECTION OUTPUT ;
    USE SIGNAL ;
    PORT
      LAYER M5 ;
        RECT  77.328 0 77.352 0.084 ;
    END
  END q[482]
  PIN q[483]
    DIRECTION OUTPUT ;
    USE SIGNAL ;
    PORT
      LAYER M5 ;
        RECT  77.76 0 77.784 0.084 ;
    END
  END q[483]
  PIN q[484]
    DIRECTION OUTPUT ;
    USE SIGNAL ;
    PORT
      LAYER M5 ;
        RECT  77.616 0 77.64 0.084 ;
    END
  END q[484]
  PIN q[485]
    DIRECTION OUTPUT ;
    USE SIGNAL ;
    PORT
      LAYER M5 ;
        RECT  78.048 0 78.072 0.084 ;
    END
  END q[485]
  PIN q[486]
    DIRECTION OUTPUT ;
    USE SIGNAL ;
    PORT
      LAYER M5 ;
        RECT  77.904 0 77.928 0.084 ;
    END
  END q[486]
  PIN q[487]
    DIRECTION OUTPUT ;
    USE SIGNAL ;
    PORT
      LAYER M5 ;
        RECT  78.336 0 78.36 0.084 ;
    END
  END q[487]
  PIN q[488]
    DIRECTION OUTPUT ;
    USE SIGNAL ;
    PORT
      LAYER M5 ;
        RECT  78.192 0 78.216 0.084 ;
    END
  END q[488]
  PIN q[489]
    DIRECTION OUTPUT ;
    USE SIGNAL ;
    PORT
      LAYER M5 ;
        RECT  78.624 0 78.648 0.084 ;
    END
  END q[489]
  PIN q[48]
    DIRECTION OUTPUT ;
    USE SIGNAL ;
    PORT
      LAYER M5 ;
        RECT  13.536 0 13.56 0.084 ;
    END
  END q[48]
  PIN q[490]
    DIRECTION OUTPUT ;
    USE SIGNAL ;
    PORT
      LAYER M5 ;
        RECT  78.48 0 78.504 0.084 ;
    END
  END q[490]
  PIN q[491]
    DIRECTION OUTPUT ;
    USE SIGNAL ;
    PORT
      LAYER M5 ;
        RECT  78.912 0 78.936 0.084 ;
    END
  END q[491]
  PIN q[492]
    DIRECTION OUTPUT ;
    USE SIGNAL ;
    PORT
      LAYER M5 ;
        RECT  78.768 0 78.792 0.084 ;
    END
  END q[492]
  PIN q[493]
    DIRECTION OUTPUT ;
    USE SIGNAL ;
    PORT
      LAYER M5 ;
        RECT  79.344 0 79.368 0.084 ;
    END
  END q[493]
  PIN q[494]
    DIRECTION OUTPUT ;
    USE SIGNAL ;
    PORT
      LAYER M5 ;
        RECT  79.056 0 79.08 0.084 ;
    END
  END q[494]
  PIN q[495]
    DIRECTION OUTPUT ;
    USE SIGNAL ;
    PORT
      LAYER M5 ;
        RECT  79.632 0 79.656 0.084 ;
    END
  END q[495]
  PIN q[496]
    DIRECTION OUTPUT ;
    USE SIGNAL ;
    PORT
      LAYER M5 ;
        RECT  79.2 0 79.224 0.084 ;
    END
  END q[496]
  PIN q[497]
    DIRECTION OUTPUT ;
    USE SIGNAL ;
    PORT
      LAYER M5 ;
        RECT  79.92 0 79.944 0.084 ;
    END
  END q[497]
  PIN q[498]
    DIRECTION OUTPUT ;
    USE SIGNAL ;
    PORT
      LAYER M5 ;
        RECT  79.488 0 79.512 0.084 ;
    END
  END q[498]
  PIN q[499]
    DIRECTION OUTPUT ;
    USE SIGNAL ;
    PORT
      LAYER M5 ;
        RECT  80.352 0 80.376 0.084 ;
    END
  END q[499]
  PIN q[49]
    DIRECTION OUTPUT ;
    USE SIGNAL ;
    PORT
      LAYER M5 ;
        RECT  13.68 0 13.704 0.084 ;
    END
  END q[49]
  PIN q[4]
    DIRECTION OUTPUT ;
    USE SIGNAL ;
    PORT
      LAYER M5 ;
        RECT  7.2 0 7.224 0.084 ;
    END
  END q[4]
  PIN q[500]
    DIRECTION OUTPUT ;
    USE SIGNAL ;
    PORT
      LAYER M5 ;
        RECT  79.776 0 79.8 0.084 ;
    END
  END q[500]
  PIN q[501]
    DIRECTION OUTPUT ;
    USE SIGNAL ;
    PORT
      LAYER M5 ;
        RECT  80.496 0 80.52 0.084 ;
    END
  END q[501]
  PIN q[502]
    DIRECTION OUTPUT ;
    USE SIGNAL ;
    PORT
      LAYER M5 ;
        RECT  80.064 0 80.088 0.084 ;
    END
  END q[502]
  PIN q[503]
    DIRECTION OUTPUT ;
    USE SIGNAL ;
    PORT
      LAYER M5 ;
        RECT  80.784 0 80.808 0.084 ;
    END
  END q[503]
  PIN q[504]
    DIRECTION OUTPUT ;
    USE SIGNAL ;
    PORT
      LAYER M5 ;
        RECT  80.208 0 80.232 0.084 ;
    END
  END q[504]
  PIN q[505]
    DIRECTION OUTPUT ;
    USE SIGNAL ;
    PORT
      LAYER M5 ;
        RECT  81.072 0 81.096 0.084 ;
    END
  END q[505]
  PIN q[506]
    DIRECTION OUTPUT ;
    USE SIGNAL ;
    PORT
      LAYER M5 ;
        RECT  80.64 0 80.664 0.084 ;
    END
  END q[506]
  PIN q[507]
    DIRECTION OUTPUT ;
    USE SIGNAL ;
    PORT
      LAYER M5 ;
        RECT  81.504 0 81.528 0.084 ;
    END
  END q[507]
  PIN q[508]
    DIRECTION OUTPUT ;
    USE SIGNAL ;
    PORT
      LAYER M5 ;
        RECT  80.928 0 80.952 0.084 ;
    END
  END q[508]
  PIN q[509]
    DIRECTION OUTPUT ;
    USE SIGNAL ;
    PORT
      LAYER M5 ;
        RECT  81.648 0 81.672 0.084 ;
    END
  END q[509]
  PIN q[50]
    DIRECTION OUTPUT ;
    USE SIGNAL ;
    PORT
      LAYER M5 ;
        RECT  13.824 0 13.848 0.084 ;
    END
  END q[50]
  PIN q[510]
    DIRECTION OUTPUT ;
    USE SIGNAL ;
    PORT
      LAYER M5 ;
        RECT  81.216 0 81.24 0.084 ;
    END
  END q[510]
  PIN q[511]
    DIRECTION OUTPUT ;
    USE SIGNAL ;
    PORT
      LAYER M5 ;
        RECT  81.792 0 81.816 0.084 ;
    END
  END q[511]
  PIN q[512]
    DIRECTION OUTPUT ;
    USE SIGNAL ;
    PORT
      LAYER M5 ;
        RECT  81.36 0 81.384 0.084 ;
    END
  END q[512]
  PIN q[513]
    DIRECTION OUTPUT ;
    USE SIGNAL ;
    PORT
      LAYER M5 ;
        RECT  81.936 0 81.96 0.084 ;
    END
  END q[513]
  PIN q[514]
    DIRECTION OUTPUT ;
    USE SIGNAL ;
    PORT
      LAYER M5 ;
        RECT  82.08 0 82.104 0.084 ;
    END
  END q[514]
  PIN q[515]
    DIRECTION OUTPUT ;
    USE SIGNAL ;
    PORT
      LAYER M5 ;
        RECT  82.224 0 82.248 0.084 ;
    END
  END q[515]
  PIN q[516]
    DIRECTION OUTPUT ;
    USE SIGNAL ;
    PORT
      LAYER M5 ;
        RECT  82.368 0 82.392 0.084 ;
    END
  END q[516]
  PIN q[51]
    DIRECTION OUTPUT ;
    USE SIGNAL ;
    PORT
      LAYER M5 ;
        RECT  13.968 0 13.992 0.084 ;
    END
  END q[51]
  PIN q[52]
    DIRECTION OUTPUT ;
    USE SIGNAL ;
    PORT
      LAYER M5 ;
        RECT  14.112 0 14.136 0.084 ;
    END
  END q[52]
  PIN q[53]
    DIRECTION OUTPUT ;
    USE SIGNAL ;
    PORT
      LAYER M5 ;
        RECT  14.4 0 14.424 0.084 ;
    END
  END q[53]
  PIN q[54]
    DIRECTION OUTPUT ;
    USE SIGNAL ;
    PORT
      LAYER M5 ;
        RECT  14.256 0 14.28 0.084 ;
    END
  END q[54]
  PIN q[55]
    DIRECTION OUTPUT ;
    USE SIGNAL ;
    PORT
      LAYER M5 ;
        RECT  14.688 0 14.712 0.084 ;
    END
  END q[55]
  PIN q[56]
    DIRECTION OUTPUT ;
    USE SIGNAL ;
    PORT
      LAYER M5 ;
        RECT  14.544 0 14.568 0.084 ;
    END
  END q[56]
  PIN q[57]
    DIRECTION OUTPUT ;
    USE SIGNAL ;
    PORT
      LAYER M5 ;
        RECT  14.976 0 15 0.084 ;
    END
  END q[57]
  PIN q[58]
    DIRECTION OUTPUT ;
    USE SIGNAL ;
    PORT
      LAYER M5 ;
        RECT  14.832 0 14.856 0.084 ;
    END
  END q[58]
  PIN q[59]
    DIRECTION OUTPUT ;
    USE SIGNAL ;
    PORT
      LAYER M5 ;
        RECT  15.264 0 15.288 0.084 ;
    END
  END q[59]
  PIN q[5]
    DIRECTION OUTPUT ;
    USE SIGNAL ;
    PORT
      LAYER M5 ;
        RECT  7.344 0 7.368 0.084 ;
    END
  END q[5]
  PIN q[60]
    DIRECTION OUTPUT ;
    USE SIGNAL ;
    PORT
      LAYER M5 ;
        RECT  15.12 0 15.144 0.084 ;
    END
  END q[60]
  PIN q[61]
    DIRECTION OUTPUT ;
    USE SIGNAL ;
    PORT
      LAYER M5 ;
        RECT  15.408 0 15.432 0.084 ;
    END
  END q[61]
  PIN q[62]
    DIRECTION OUTPUT ;
    USE SIGNAL ;
    PORT
      LAYER M5 ;
        RECT  15.84 0 15.864 0.084 ;
    END
  END q[62]
  PIN q[63]
    DIRECTION OUTPUT ;
    USE SIGNAL ;
    PORT
      LAYER M5 ;
        RECT  15.552 0 15.576 0.084 ;
    END
  END q[63]
  PIN q[64]
    DIRECTION OUTPUT ;
    USE SIGNAL ;
    PORT
      LAYER M5 ;
        RECT  16.128 0 16.152 0.084 ;
    END
  END q[64]
  PIN q[65]
    DIRECTION OUTPUT ;
    USE SIGNAL ;
    PORT
      LAYER M5 ;
        RECT  15.696 0 15.72 0.084 ;
    END
  END q[65]
  PIN q[66]
    DIRECTION OUTPUT ;
    USE SIGNAL ;
    PORT
      LAYER M5 ;
        RECT  16.416 0 16.44 0.084 ;
    END
  END q[66]
  PIN q[67]
    DIRECTION OUTPUT ;
    USE SIGNAL ;
    PORT
      LAYER M5 ;
        RECT  15.984 0 16.008 0.084 ;
    END
  END q[67]
  PIN q[68]
    DIRECTION OUTPUT ;
    USE SIGNAL ;
    PORT
      LAYER M5 ;
        RECT  16.56 0 16.584 0.084 ;
    END
  END q[68]
  PIN q[69]
    DIRECTION OUTPUT ;
    USE SIGNAL ;
    PORT
      LAYER M5 ;
        RECT  16.272 0 16.296 0.084 ;
    END
  END q[69]
  PIN q[6]
    DIRECTION OUTPUT ;
    USE SIGNAL ;
    PORT
      LAYER M5 ;
        RECT  7.488 0 7.512 0.084 ;
    END
  END q[6]
  PIN q[70]
    DIRECTION OUTPUT ;
    USE SIGNAL ;
    PORT
      LAYER M5 ;
        RECT  16.848 0 16.872 0.084 ;
    END
  END q[70]
  PIN q[71]
    DIRECTION OUTPUT ;
    USE SIGNAL ;
    PORT
      LAYER M5 ;
        RECT  16.704 0 16.728 0.084 ;
    END
  END q[71]
  PIN q[72]
    DIRECTION OUTPUT ;
    USE SIGNAL ;
    PORT
      LAYER M5 ;
        RECT  17.136 0 17.16 0.084 ;
    END
  END q[72]
  PIN q[73]
    DIRECTION OUTPUT ;
    USE SIGNAL ;
    PORT
      LAYER M5 ;
        RECT  16.992 0 17.016 0.084 ;
    END
  END q[73]
  PIN q[74]
    DIRECTION OUTPUT ;
    USE SIGNAL ;
    PORT
      LAYER M5 ;
        RECT  17.424 0 17.448 0.084 ;
    END
  END q[74]
  PIN q[75]
    DIRECTION OUTPUT ;
    USE SIGNAL ;
    PORT
      LAYER M5 ;
        RECT  17.28 0 17.304 0.084 ;
    END
  END q[75]
  PIN q[76]
    DIRECTION OUTPUT ;
    USE SIGNAL ;
    PORT
      LAYER M5 ;
        RECT  17.712 0 17.736 0.084 ;
    END
  END q[76]
  PIN q[77]
    DIRECTION OUTPUT ;
    USE SIGNAL ;
    PORT
      LAYER M5 ;
        RECT  17.568 0 17.592 0.084 ;
    END
  END q[77]
  PIN q[78]
    DIRECTION OUTPUT ;
    USE SIGNAL ;
    PORT
      LAYER M5 ;
        RECT  18 0 18.024 0.084 ;
    END
  END q[78]
  PIN q[79]
    DIRECTION OUTPUT ;
    USE SIGNAL ;
    PORT
      LAYER M5 ;
        RECT  17.856 0 17.88 0.084 ;
    END
  END q[79]
  PIN q[7]
    DIRECTION OUTPUT ;
    USE SIGNAL ;
    PORT
      LAYER M5 ;
        RECT  7.632 0 7.656 0.084 ;
    END
  END q[7]
  PIN q[80]
    DIRECTION OUTPUT ;
    USE SIGNAL ;
    PORT
      LAYER M5 ;
        RECT  18.288 0 18.312 0.084 ;
    END
  END q[80]
  PIN q[81]
    DIRECTION OUTPUT ;
    USE SIGNAL ;
    PORT
      LAYER M5 ;
        RECT  18.144 0 18.168 0.084 ;
    END
  END q[81]
  PIN q[82]
    DIRECTION OUTPUT ;
    USE SIGNAL ;
    PORT
      LAYER M5 ;
        RECT  18.576 0 18.6 0.084 ;
    END
  END q[82]
  PIN q[83]
    DIRECTION OUTPUT ;
    USE SIGNAL ;
    PORT
      LAYER M5 ;
        RECT  18.432 0 18.456 0.084 ;
    END
  END q[83]
  PIN q[84]
    DIRECTION OUTPUT ;
    USE SIGNAL ;
    PORT
      LAYER M5 ;
        RECT  18.864 0 18.888 0.084 ;
    END
  END q[84]
  PIN q[85]
    DIRECTION OUTPUT ;
    USE SIGNAL ;
    PORT
      LAYER M5 ;
        RECT  18.72 0 18.744 0.084 ;
    END
  END q[85]
  PIN q[86]
    DIRECTION OUTPUT ;
    USE SIGNAL ;
    PORT
      LAYER M5 ;
        RECT  19.152 0 19.176 0.084 ;
    END
  END q[86]
  PIN q[87]
    DIRECTION OUTPUT ;
    USE SIGNAL ;
    PORT
      LAYER M5 ;
        RECT  19.008 0 19.032 0.084 ;
    END
  END q[87]
  PIN q[88]
    DIRECTION OUTPUT ;
    USE SIGNAL ;
    PORT
      LAYER M5 ;
        RECT  19.296 0 19.32 0.084 ;
    END
  END q[88]
  PIN q[89]
    DIRECTION OUTPUT ;
    USE SIGNAL ;
    PORT
      LAYER M5 ;
        RECT  19.44 0 19.464 0.084 ;
    END
  END q[89]
  PIN q[8]
    DIRECTION OUTPUT ;
    USE SIGNAL ;
    PORT
      LAYER M5 ;
        RECT  7.776 0 7.8 0.084 ;
    END
  END q[8]
  PIN q[90]
    DIRECTION OUTPUT ;
    USE SIGNAL ;
    PORT
      LAYER M5 ;
        RECT  19.584 0 19.608 0.084 ;
    END
  END q[90]
  PIN q[91]
    DIRECTION OUTPUT ;
    USE SIGNAL ;
    PORT
      LAYER M5 ;
        RECT  19.728 0 19.752 0.084 ;
    END
  END q[91]
  PIN q[92]
    DIRECTION OUTPUT ;
    USE SIGNAL ;
    PORT
      LAYER M5 ;
        RECT  19.872 0 19.896 0.084 ;
    END
  END q[92]
  PIN q[93]
    DIRECTION OUTPUT ;
    USE SIGNAL ;
    PORT
      LAYER M5 ;
        RECT  20.016 0 20.04 0.084 ;
    END
  END q[93]
  PIN q[94]
    DIRECTION OUTPUT ;
    USE SIGNAL ;
    PORT
      LAYER M5 ;
        RECT  20.16 0 20.184 0.084 ;
    END
  END q[94]
  PIN q[95]
    DIRECTION OUTPUT ;
    USE SIGNAL ;
    PORT
      LAYER M5 ;
        RECT  20.304 0 20.328 0.084 ;
    END
  END q[95]
  PIN q[96]
    DIRECTION OUTPUT ;
    USE SIGNAL ;
    PORT
      LAYER M5 ;
        RECT  20.448 0 20.472 0.084 ;
    END
  END q[96]
  PIN q[97]
    DIRECTION OUTPUT ;
    USE SIGNAL ;
    PORT
      LAYER M5 ;
        RECT  20.592 0 20.616 0.084 ;
    END
  END q[97]
  PIN q[98]
    DIRECTION OUTPUT ;
    USE SIGNAL ;
    PORT
      LAYER M5 ;
        RECT  20.736 0 20.76 0.084 ;
    END
  END q[98]
  PIN q[99]
    DIRECTION OUTPUT ;
    USE SIGNAL ;
    PORT
      LAYER M5 ;
        RECT  20.88 0 20.904 0.084 ;
    END
  END q[99]
  PIN q[9]
    DIRECTION OUTPUT ;
    USE SIGNAL ;
    PORT
      LAYER M5 ;
        RECT  8.064 0 8.088 0.084 ;
    END
  END q[9]
  PIN ready
    DIRECTION OUTPUT ;
    USE SIGNAL ;
    PORT
      LAYER M5 ;
        RECT  44.064 0 44.088 0.084 ;
    END
  END ready
  PIN rst_n
    DIRECTION INPUT ;
    USE SIGNAL ;
    PORT
      LAYER M5 ;
        RECT  43.92 0 43.944 0.084 ;
    END
  END rst_n
  PIN strap_k[0]
    DIRECTION INPUT ;
    USE SIGNAL ;
    PORT
      LAYER M5 ;
        RECT  44.352 0 44.376 0.084 ;
    END
  END strap_k[0]
  PIN strap_k[1]
    DIRECTION INPUT ;
    USE SIGNAL ;
    PORT
      LAYER M5 ;
        RECT  44.496 0 44.52 0.084 ;
    END
  END strap_k[1]
  PIN strap_k[2]
    DIRECTION INPUT ;
    USE SIGNAL ;
    PORT
      LAYER M5 ;
        RECT  44.64 0 44.664 0.084 ;
    END
  END strap_k[2]
  PIN strap_k[3]
    DIRECTION INPUT ;
    USE SIGNAL ;
    PORT
      LAYER M5 ;
        RECT  44.784 0 44.808 0.084 ;
    END
  END strap_k[3]
  PIN strap_k[4]
    DIRECTION INPUT ;
    USE SIGNAL ;
    PORT
      LAYER M5 ;
        RECT  44.928 0 44.952 0.084 ;
    END
  END strap_k[4]
  PIN strap_k[5]
    DIRECTION INPUT ;
    USE SIGNAL ;
    PORT
      LAYER M5 ;
        RECT  45.072 0 45.096 0.084 ;
    END
  END strap_k[5]
  PIN t_rst_n
    DIRECTION INPUT ;
    USE SIGNAL ;
    PORT
      LAYER M5 ;
        RECT  44.496 51.756 44.52 51.84 ;
    END
  END t_rst_n
  PIN VDD
    DIRECTION INOUT ;
    USE POWER ;
    PORT
      LAYER M5 ;
        RECT  84.276 4.311 84.396 47.529 ;
        RECT  79.956 4.311 80.076 47.529 ;
        RECT  75.636 4.311 75.756 47.529 ;
        RECT  71.316 4.311 71.436 47.529 ;
        RECT  66.996 4.311 67.116 47.529 ;
        RECT  62.676 4.311 62.796 47.529 ;
        RECT  58.356 4.311 58.476 47.529 ;
        RECT  54.036 4.311 54.156 47.529 ;
        RECT  49.716 4.311 49.836 47.529 ;
        RECT  45.396 4.311 45.516 47.529 ;
        RECT  41.076 4.311 41.196 47.529 ;
        RECT  36.756 4.311 36.876 47.529 ;
        RECT  32.436 4.311 32.556 47.529 ;
        RECT  28.116 4.311 28.236 47.529 ;
        RECT  23.796 4.311 23.916 47.529 ;
        RECT  19.476 4.311 19.596 47.529 ;
        RECT  15.156 4.311 15.276 47.529 ;
        RECT  10.836 4.311 10.956 47.529 ;
        RECT  6.516 4.311 6.636 47.529 ;
    END
  END VDD
  PIN VSS
    DIRECTION INOUT ;
    USE GROUND ;
    PORT
      LAYER M5 ;
        RECT  84.084 4.297 84.204 47.543 ;
        RECT  79.764 4.297 79.884 47.543 ;
        RECT  75.444 4.297 75.564 47.543 ;
        RECT  71.124 4.297 71.244 47.543 ;
        RECT  66.804 4.297 66.924 47.543 ;
        RECT  62.484 4.297 62.604 47.543 ;
        RECT  58.164 4.297 58.284 47.543 ;
        RECT  53.844 4.297 53.964 47.543 ;
        RECT  49.524 4.297 49.644 47.543 ;
        RECT  45.204 4.297 45.324 47.543 ;
        RECT  40.884 4.297 41.004 47.543 ;
        RECT  36.564 4.297 36.684 47.543 ;
        RECT  32.244 4.297 32.364 47.543 ;
        RECT  27.924 4.297 28.044 47.543 ;
        RECT  23.604 4.297 23.724 47.543 ;
        RECT  19.284 4.297 19.404 47.543 ;
        RECT  14.964 4.297 15.084 47.543 ;
        RECT  10.644 4.297 10.764 47.543 ;
        RECT  6.324 4.297 6.444 47.543 ;
    END
  END VSS
  OBS
    LAYER RVTN ;
     RECT  4.32 0 84.672 51.84 ;
    LAYER RVTP ;
     RECT  4.32 0 84.672 51.84 ;
    LAYER M1 ;
     RECT  4.32 0 84.672 51.84 ;
    LAYER M2 ;
     RECT  4.32 0 84.672 51.84 ;
    LAYER M3 ;
     RECT  4.32 0 84.672 51.84 ;
    LAYER M4 ;
     RECT  4.32 0 84.672 51.84 ;
    LAYER M5 ;
     RECT  4.32 0 84.672 51.84 ;
  END
END sle_cland_w517_n_1
END LIBRARY
